VERSION 5.8 ;
BUSBITCHARS "[]" ;
DIVIDERCHAR "/" ;
UNITS
    DATABASE MICRONS 1000 ;
END UNITS

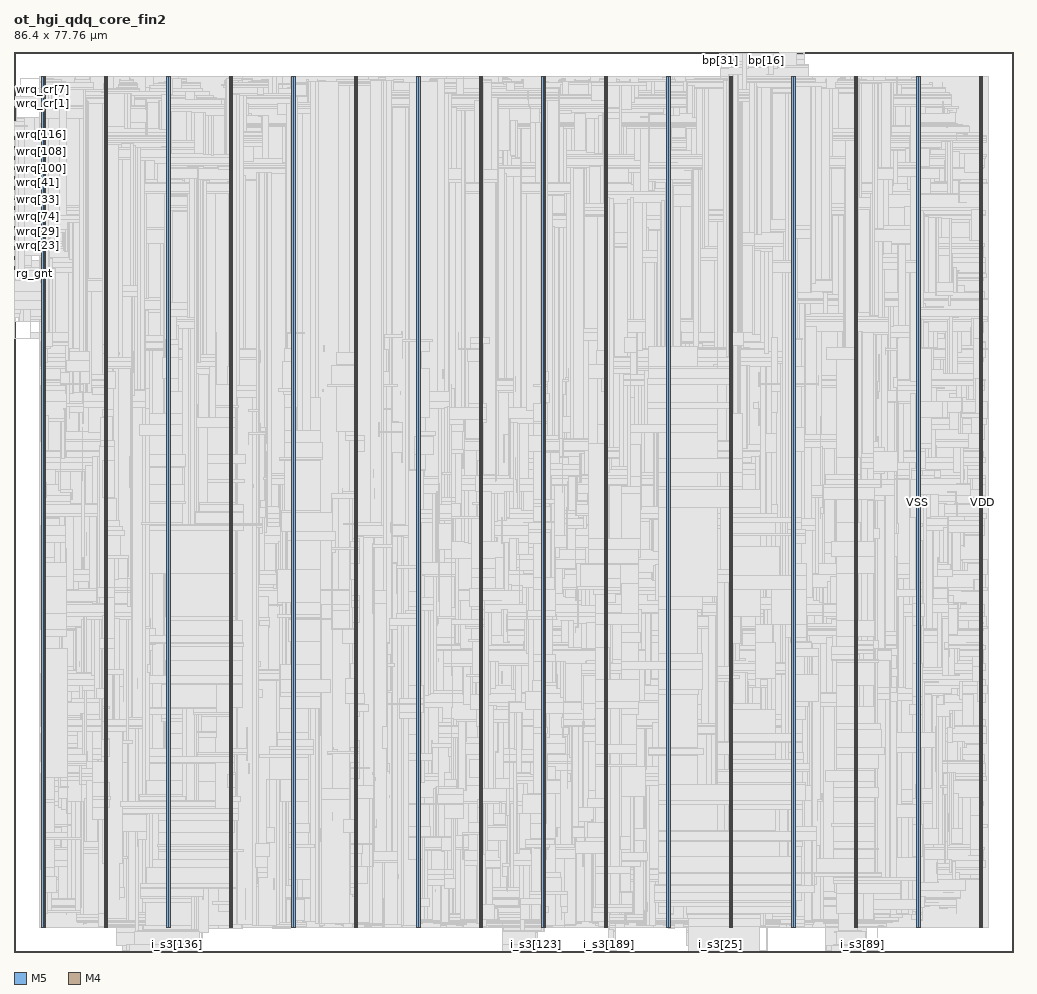
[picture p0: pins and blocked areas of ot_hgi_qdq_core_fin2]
MACRO ot_hgi_qdq_core_fin2
  FOREIGN ot_hgi_qdq_core_fin2 0 0 ;
  CLASS BLOCK ;
  SIZE 86.4 BY 77.76 ;
  PIN asm_rst_n
    DIRECTION OUTPUT ;
    USE SIGNAL ;
    PORT
      LAYER M5 ;
        RECT  63.408 77.676 63.432 77.76 ;
    END
  END asm_rst_n
  PIN bp[0]
    DIRECTION OUTPUT ;
    USE SIGNAL ;
    PORT
      LAYER M5 ;
        RECT  63.504 77.676 63.528 77.76 ;
    END
  END bp[0]
  PIN bp[10]
    DIRECTION OUTPUT ;
    USE SIGNAL ;
    PORT
      LAYER M5 ;
        RECT  64.464 77.676 64.488 77.76 ;
    END
  END bp[10]
  PIN bp[11]
    DIRECTION OUTPUT ;
    USE SIGNAL ;
    PORT
      LAYER M5 ;
        RECT  64.56 77.676 64.584 77.76 ;
    END
  END bp[11]
  PIN bp[12]
    DIRECTION OUTPUT ;
    USE SIGNAL ;
    PORT
      LAYER M5 ;
        RECT  64.656 77.676 64.68 77.76 ;
    END
  END bp[12]
  PIN bp[13]
    DIRECTION OUTPUT ;
    USE SIGNAL ;
    PORT
      LAYER M5 ;
        RECT  64.752 77.676 64.776 77.76 ;
    END
  END bp[13]
  PIN bp[14]
    DIRECTION OUTPUT ;
    USE SIGNAL ;
    PORT
      LAYER M5 ;
        RECT  64.848 77.676 64.872 77.76 ;
    END
  END bp[14]
  PIN bp[15]
    DIRECTION OUTPUT ;
    USE SIGNAL ;
    PORT
      LAYER M5 ;
        RECT  64.944 77.676 64.968 77.76 ;
    END
  END bp[15]
  PIN bp[16]
    DIRECTION OUTPUT ;
    USE SIGNAL ;
    PORT
      LAYER M5 ;
        RECT  65.04 77.676 65.064 77.76 ;
    END
  END bp[16]
  PIN bp[17]
    DIRECTION OUTPUT ;
    USE SIGNAL ;
    PORT
      LAYER M5 ;
        RECT  65.136 77.676 65.16 77.76 ;
    END
  END bp[17]
  PIN bp[18]
    DIRECTION OUTPUT ;
    USE SIGNAL ;
    PORT
      LAYER M5 ;
        RECT  65.232 77.676 65.256 77.76 ;
    END
  END bp[18]
  PIN bp[19]
    DIRECTION OUTPUT ;
    USE SIGNAL ;
    PORT
      LAYER M5 ;
        RECT  65.328 77.676 65.352 77.76 ;
    END
  END bp[19]
  PIN bp[1]
    DIRECTION OUTPUT ;
    USE SIGNAL ;
    PORT
      LAYER M5 ;
        RECT  63.6 77.676 63.624 77.76 ;
    END
  END bp[1]
  PIN bp[20]
    DIRECTION OUTPUT ;
    USE SIGNAL ;
    PORT
      LAYER M5 ;
        RECT  65.424 77.676 65.448 77.76 ;
    END
  END bp[20]
  PIN bp[21]
    DIRECTION OUTPUT ;
    USE SIGNAL ;
    PORT
      LAYER M5 ;
        RECT  65.52 77.676 65.544 77.76 ;
    END
  END bp[21]
  PIN bp[22]
    DIRECTION OUTPUT ;
    USE SIGNAL ;
    PORT
      LAYER M5 ;
        RECT  65.616 77.676 65.64 77.76 ;
    END
  END bp[22]
  PIN bp[23]
    DIRECTION OUTPUT ;
    USE SIGNAL ;
    PORT
      LAYER M5 ;
        RECT  65.712 77.676 65.736 77.76 ;
    END
  END bp[23]
  PIN bp[24]
    DIRECTION OUTPUT ;
    USE SIGNAL ;
    PORT
      LAYER M5 ;
        RECT  65.808 77.676 65.832 77.76 ;
    END
  END bp[24]
  PIN bp[25]
    DIRECTION OUTPUT ;
    USE SIGNAL ;
    PORT
      LAYER M5 ;
        RECT  65.904 77.676 65.928 77.76 ;
    END
  END bp[25]
  PIN bp[26]
    DIRECTION OUTPUT ;
    USE SIGNAL ;
    PORT
      LAYER M5 ;
        RECT  66 77.676 66.024 77.76 ;
    END
  END bp[26]
  PIN bp[27]
    DIRECTION OUTPUT ;
    USE SIGNAL ;
    PORT
      LAYER M5 ;
        RECT  66.096 77.676 66.12 77.76 ;
    END
  END bp[27]
  PIN bp[28]
    DIRECTION OUTPUT ;
    USE SIGNAL ;
    PORT
      LAYER M5 ;
        RECT  66.192 77.676 66.216 77.76 ;
    END
  END bp[28]
  PIN bp[29]
    DIRECTION OUTPUT ;
    USE SIGNAL ;
    PORT
      LAYER M5 ;
        RECT  66.288 77.676 66.312 77.76 ;
    END
  END bp[29]
  PIN bp[2]
    DIRECTION OUTPUT ;
    USE SIGNAL ;
    PORT
      LAYER M5 ;
        RECT  63.696 77.676 63.72 77.76 ;
    END
  END bp[2]
  PIN bp[30]
    DIRECTION OUTPUT ;
    USE SIGNAL ;
    PORT
      LAYER M5 ;
        RECT  66.384 77.676 66.408 77.76 ;
    END
  END bp[30]
  PIN bp[31]
    DIRECTION OUTPUT ;
    USE SIGNAL ;
    PORT
      LAYER M5 ;
        RECT  61.008 77.676 61.032 77.76 ;
    END
  END bp[31]
  PIN bp[32]
    DIRECTION OUTPUT ;
    USE SIGNAL ;
    PORT
      LAYER M5 ;
        RECT  61.104 77.676 61.128 77.76 ;
    END
  END bp[32]
  PIN bp[33]
    DIRECTION OUTPUT ;
    USE SIGNAL ;
    PORT
      LAYER M5 ;
        RECT  61.2 77.676 61.224 77.76 ;
    END
  END bp[33]
  PIN bp[34]
    DIRECTION OUTPUT ;
    USE SIGNAL ;
    PORT
      LAYER M5 ;
        RECT  61.296 77.676 61.32 77.76 ;
    END
  END bp[34]
  PIN bp[35]
    DIRECTION OUTPUT ;
    USE SIGNAL ;
    PORT
      LAYER M5 ;
        RECT  61.392 77.676 61.416 77.76 ;
    END
  END bp[35]
  PIN bp[36]
    DIRECTION OUTPUT ;
    USE SIGNAL ;
    PORT
      LAYER M5 ;
        RECT  61.488 77.676 61.512 77.76 ;
    END
  END bp[36]
  PIN bp[37]
    DIRECTION OUTPUT ;
    USE SIGNAL ;
    PORT
      LAYER M5 ;
        RECT  61.584 77.676 61.608 77.76 ;
    END
  END bp[37]
  PIN bp[38]
    DIRECTION OUTPUT ;
    USE SIGNAL ;
    PORT
      LAYER M5 ;
        RECT  61.68 77.676 61.704 77.76 ;
    END
  END bp[38]
  PIN bp[39]
    DIRECTION OUTPUT ;
    USE SIGNAL ;
    PORT
      LAYER M5 ;
        RECT  61.776 77.676 61.8 77.76 ;
    END
  END bp[39]
  PIN bp[3]
    DIRECTION OUTPUT ;
    USE SIGNAL ;
    PORT
      LAYER M5 ;
        RECT  63.792 77.676 63.816 77.76 ;
    END
  END bp[3]
  PIN bp[4]
    DIRECTION OUTPUT ;
    USE SIGNAL ;
    PORT
      LAYER M5 ;
        RECT  63.888 77.676 63.912 77.76 ;
    END
  END bp[4]
  PIN bp[5]
    DIRECTION OUTPUT ;
    USE SIGNAL ;
    PORT
      LAYER M5 ;
        RECT  63.984 77.676 64.008 77.76 ;
    END
  END bp[5]
  PIN bp[6]
    DIRECTION OUTPUT ;
    USE SIGNAL ;
    PORT
      LAYER M5 ;
        RECT  64.08 77.676 64.104 77.76 ;
    END
  END bp[6]
  PIN bp[7]
    DIRECTION OUTPUT ;
    USE SIGNAL ;
    PORT
      LAYER M5 ;
        RECT  64.176 77.676 64.2 77.76 ;
    END
  END bp[7]
  PIN bp[8]
    DIRECTION OUTPUT ;
    USE SIGNAL ;
    PORT
      LAYER M5 ;
        RECT  64.272 77.676 64.296 77.76 ;
    END
  END bp[8]
  PIN bp[9]
    DIRECTION OUTPUT ;
    USE SIGNAL ;
    PORT
      LAYER M5 ;
        RECT  64.368 77.676 64.392 77.76 ;
    END
  END bp[9]
  PIN bp_v
    DIRECTION OUTPUT ;
    USE SIGNAL ;
    PORT
      LAYER M5 ;
        RECT  61.872 77.676 61.896 77.76 ;
    END
  END bp_v
  PIN clk
    DIRECTION INPUT ;
    USE SIGNAL ;
    PORT
      LAYER M5 ;
        RECT  58.32 0 58.344 0.084 ;
    END
  END clk
  PIN i_abad
    DIRECTION INPUT ;
    USE SIGNAL ;
    PORT
      LAYER M5 ;
        RECT  61.968 77.676 61.992 77.76 ;
    END
  END i_abad
  PIN i_aidle
    DIRECTION INPUT ;
    USE SIGNAL ;
    PORT
      LAYER M5 ;
        RECT  62.064 77.676 62.088 77.76 ;
    END
  END i_aidle
  PIN i_fin
    DIRECTION INPUT ;
    USE SIGNAL ;
    PORT
      LAYER M5 ;
        RECT  62.16 77.676 62.184 77.76 ;
    END
  END i_fin
  PIN i_fire
    DIRECTION INPUT ;
    USE SIGNAL ;
    PORT
      LAYER M5 ;
        RECT  62.256 77.676 62.28 77.76 ;
    END
  END i_fire
  PIN i_nfault
    DIRECTION INPUT ;
    USE SIGNAL ;
    PORT
      LAYER M5 ;
        RECT  58.416 0 58.44 0.084 ;
    END
  END i_nfault
  PIN i_pop[0]
    DIRECTION INPUT ;
    USE SIGNAL ;
    PORT
      LAYER M5 ;
        RECT  62.352 77.676 62.376 77.76 ;
    END
  END i_pop[0]
  PIN i_pop[1]
    DIRECTION INPUT ;
    USE SIGNAL ;
    PORT
      LAYER M5 ;
        RECT  62.448 77.676 62.472 77.76 ;
    END
  END i_pop[1]
  PIN i_pop[2]
    DIRECTION INPUT ;
    USE SIGNAL ;
    PORT
      LAYER M5 ;
        RECT  62.544 77.676 62.568 77.76 ;
    END
  END i_pop[2]
  PIN i_pop[3]
    DIRECTION INPUT ;
    USE SIGNAL ;
    PORT
      LAYER M5 ;
        RECT  62.64 77.676 62.664 77.76 ;
    END
  END i_pop[3]
  PIN i_pop[4]
    DIRECTION INPUT ;
    USE SIGNAL ;
    PORT
      LAYER M5 ;
        RECT  62.736 77.676 62.76 77.76 ;
    END
  END i_pop[4]
  PIN i_pop[5]
    DIRECTION INPUT ;
    USE SIGNAL ;
    PORT
      LAYER M5 ;
        RECT  62.832 77.676 62.856 77.76 ;
    END
  END i_pop[5]
  PIN i_pop[6]
    DIRECTION INPUT ;
    USE SIGNAL ;
    PORT
      LAYER M5 ;
        RECT  62.928 77.676 62.952 77.76 ;
    END
  END i_pop[6]
  PIN i_pop[7]
    DIRECTION INPUT ;
    USE SIGNAL ;
    PORT
      LAYER M5 ;
        RECT  63.024 77.676 63.048 77.76 ;
    END
  END i_pop[7]
  PIN i_s1_v
    DIRECTION INPUT ;
    USE SIGNAL ;
    PORT
      LAYER M5 ;
        RECT  58.512 0 58.536 0.084 ;
    END
  END i_s1_v
  PIN i_s3[0]
    DIRECTION INPUT ;
    USE SIGNAL ;
    PORT
      LAYER M5 ;
        RECT  58.608 0 58.632 0.084 ;
    END
  END i_s3[0]
  PIN i_s3[100]
    DIRECTION INPUT ;
    USE SIGNAL ;
    PORT
      LAYER M5 ;
        RECT  42.864 0 42.888 0.084 ;
    END
  END i_s3[100]
  PIN i_s3[101]
    DIRECTION INPUT ;
    USE SIGNAL ;
    PORT
      LAYER M5 ;
        RECT  42.96 0 42.984 0.084 ;
    END
  END i_s3[101]
  PIN i_s3[102]
    DIRECTION INPUT ;
    USE SIGNAL ;
    PORT
      LAYER M5 ;
        RECT  43.056 0 43.08 0.084 ;
    END
  END i_s3[102]
  PIN i_s3[103]
    DIRECTION INPUT ;
    USE SIGNAL ;
    PORT
      LAYER M5 ;
        RECT  43.152 0 43.176 0.084 ;
    END
  END i_s3[103]
  PIN i_s3[104]
    DIRECTION INPUT ;
    USE SIGNAL ;
    PORT
      LAYER M5 ;
        RECT  43.248 0 43.272 0.084 ;
    END
  END i_s3[104]
  PIN i_s3[105]
    DIRECTION INPUT ;
    USE SIGNAL ;
    PORT
      LAYER M5 ;
        RECT  43.344 0 43.368 0.084 ;
    END
  END i_s3[105]
  PIN i_s3[106]
    DIRECTION INPUT ;
    USE SIGNAL ;
    PORT
      LAYER M5 ;
        RECT  43.44 0 43.464 0.084 ;
    END
  END i_s3[106]
  PIN i_s3[107]
    DIRECTION INPUT ;
    USE SIGNAL ;
    PORT
      LAYER M5 ;
        RECT  43.536 0 43.56 0.084 ;
    END
  END i_s3[107]
  PIN i_s3[108]
    DIRECTION INPUT ;
    USE SIGNAL ;
    PORT
      LAYER M5 ;
        RECT  43.632 0 43.656 0.084 ;
    END
  END i_s3[108]
  PIN i_s3[109]
    DIRECTION INPUT ;
    USE SIGNAL ;
    PORT
      LAYER M5 ;
        RECT  43.728 0 43.752 0.084 ;
    END
  END i_s3[109]
  PIN i_s3[10]
    DIRECTION INPUT ;
    USE SIGNAL ;
    PORT
      LAYER M5 ;
        RECT  59.568 0 59.592 0.084 ;
    END
  END i_s3[10]
  PIN i_s3[110]
    DIRECTION INPUT ;
    USE SIGNAL ;
    PORT
      LAYER M5 ;
        RECT  43.824 0 43.848 0.084 ;
    END
  END i_s3[110]
  PIN i_s3[111]
    DIRECTION INPUT ;
    USE SIGNAL ;
    PORT
      LAYER M5 ;
        RECT  43.92 0 43.944 0.084 ;
    END
  END i_s3[111]
  PIN i_s3[112]
    DIRECTION INPUT ;
    USE SIGNAL ;
    PORT
      LAYER M5 ;
        RECT  44.016 0 44.04 0.084 ;
    END
  END i_s3[112]
  PIN i_s3[113]
    DIRECTION INPUT ;
    USE SIGNAL ;
    PORT
      LAYER M5 ;
        RECT  44.112 0 44.136 0.084 ;
    END
  END i_s3[113]
  PIN i_s3[114]
    DIRECTION INPUT ;
    USE SIGNAL ;
    PORT
      LAYER M5 ;
        RECT  44.208 0 44.232 0.084 ;
    END
  END i_s3[114]
  PIN i_s3[115]
    DIRECTION INPUT ;
    USE SIGNAL ;
    PORT
      LAYER M5 ;
        RECT  44.304 0 44.328 0.084 ;
    END
  END i_s3[115]
  PIN i_s3[116]
    DIRECTION INPUT ;
    USE SIGNAL ;
    PORT
      LAYER M5 ;
        RECT  44.4 0 44.424 0.084 ;
    END
  END i_s3[116]
  PIN i_s3[117]
    DIRECTION INPUT ;
    USE SIGNAL ;
    PORT
      LAYER M5 ;
        RECT  44.496 0 44.52 0.084 ;
    END
  END i_s3[117]
  PIN i_s3[118]
    DIRECTION INPUT ;
    USE SIGNAL ;
    PORT
      LAYER M5 ;
        RECT  44.592 0 44.616 0.084 ;
    END
  END i_s3[118]
  PIN i_s3[119]
    DIRECTION INPUT ;
    USE SIGNAL ;
    PORT
      LAYER M5 ;
        RECT  44.688 0 44.712 0.084 ;
    END
  END i_s3[119]
  PIN i_s3[11]
    DIRECTION INPUT ;
    USE SIGNAL ;
    PORT
      LAYER M5 ;
        RECT  59.664 0 59.688 0.084 ;
    END
  END i_s3[11]
  PIN i_s3[120]
    DIRECTION INPUT ;
    USE SIGNAL ;
    PORT
      LAYER M5 ;
        RECT  44.784 0 44.808 0.084 ;
    END
  END i_s3[120]
  PIN i_s3[121]
    DIRECTION INPUT ;
    USE SIGNAL ;
    PORT
      LAYER M5 ;
        RECT  44.88 0 44.904 0.084 ;
    END
  END i_s3[121]
  PIN i_s3[122]
    DIRECTION INPUT ;
    USE SIGNAL ;
    PORT
      LAYER M5 ;
        RECT  44.976 0 45 0.084 ;
    END
  END i_s3[122]
  PIN i_s3[123]
    DIRECTION INPUT ;
    USE SIGNAL ;
    PORT
      LAYER M5 ;
        RECT  45.072 0 45.096 0.084 ;
    END
  END i_s3[123]
  PIN i_s3[124]
    DIRECTION INPUT ;
    USE SIGNAL ;
    PORT
      LAYER M5 ;
        RECT  45.168 0 45.192 0.084 ;
    END
  END i_s3[124]
  PIN i_s3[125]
    DIRECTION INPUT ;
    USE SIGNAL ;
    PORT
      LAYER M5 ;
        RECT  13.008 0 13.032 0.084 ;
    END
  END i_s3[125]
  PIN i_s3[126]
    DIRECTION INPUT ;
    USE SIGNAL ;
    PORT
      LAYER M5 ;
        RECT  13.104 0 13.128 0.084 ;
    END
  END i_s3[126]
  PIN i_s3[127]
    DIRECTION INPUT ;
    USE SIGNAL ;
    PORT
      LAYER M5 ;
        RECT  13.2 0 13.224 0.084 ;
    END
  END i_s3[127]
  PIN i_s3[128]
    DIRECTION INPUT ;
    USE SIGNAL ;
    PORT
      LAYER M5 ;
        RECT  13.296 0 13.32 0.084 ;
    END
  END i_s3[128]
  PIN i_s3[129]
    DIRECTION INPUT ;
    USE SIGNAL ;
    PORT
      LAYER M5 ;
        RECT  13.392 0 13.416 0.084 ;
    END
  END i_s3[129]
  PIN i_s3[12]
    DIRECTION INPUT ;
    USE SIGNAL ;
    PORT
      LAYER M5 ;
        RECT  59.76 0 59.784 0.084 ;
    END
  END i_s3[12]
  PIN i_s3[130]
    DIRECTION INPUT ;
    USE SIGNAL ;
    PORT
      LAYER M5 ;
        RECT  13.488 0 13.512 0.084 ;
    END
  END i_s3[130]
  PIN i_s3[131]
    DIRECTION INPUT ;
    USE SIGNAL ;
    PORT
      LAYER M5 ;
        RECT  13.584 0 13.608 0.084 ;
    END
  END i_s3[131]
  PIN i_s3[132]
    DIRECTION INPUT ;
    USE SIGNAL ;
    PORT
      LAYER M5 ;
        RECT  13.68 0 13.704 0.084 ;
    END
  END i_s3[132]
  PIN i_s3[133]
    DIRECTION INPUT ;
    USE SIGNAL ;
    PORT
      LAYER M5 ;
        RECT  13.776 0 13.8 0.084 ;
    END
  END i_s3[133]
  PIN i_s3[134]
    DIRECTION INPUT ;
    USE SIGNAL ;
    PORT
      LAYER M5 ;
        RECT  13.872 0 13.896 0.084 ;
    END
  END i_s3[134]
  PIN i_s3[135]
    DIRECTION INPUT ;
    USE SIGNAL ;
    PORT
      LAYER M5 ;
        RECT  13.968 0 13.992 0.084 ;
    END
  END i_s3[135]
  PIN i_s3[136]
    DIRECTION INPUT ;
    USE SIGNAL ;
    PORT
      LAYER M5 ;
        RECT  14.064 0 14.088 0.084 ;
    END
  END i_s3[136]
  PIN i_s3[137]
    DIRECTION INPUT ;
    USE SIGNAL ;
    PORT
      LAYER M5 ;
        RECT  14.16 0 14.184 0.084 ;
    END
  END i_s3[137]
  PIN i_s3[138]
    DIRECTION INPUT ;
    USE SIGNAL ;
    PORT
      LAYER M5 ;
        RECT  14.256 0 14.28 0.084 ;
    END
  END i_s3[138]
  PIN i_s3[139]
    DIRECTION INPUT ;
    USE SIGNAL ;
    PORT
      LAYER M5 ;
        RECT  14.352 0 14.376 0.084 ;
    END
  END i_s3[139]
  PIN i_s3[13]
    DIRECTION INPUT ;
    USE SIGNAL ;
    PORT
      LAYER M5 ;
        RECT  59.856 0 59.88 0.084 ;
    END
  END i_s3[13]
  PIN i_s3[140]
    DIRECTION INPUT ;
    USE SIGNAL ;
    PORT
      LAYER M5 ;
        RECT  14.448 0 14.472 0.084 ;
    END
  END i_s3[140]
  PIN i_s3[141]
    DIRECTION INPUT ;
    USE SIGNAL ;
    PORT
      LAYER M5 ;
        RECT  14.544 0 14.568 0.084 ;
    END
  END i_s3[141]
  PIN i_s3[142]
    DIRECTION INPUT ;
    USE SIGNAL ;
    PORT
      LAYER M5 ;
        RECT  14.64 0 14.664 0.084 ;
    END
  END i_s3[142]
  PIN i_s3[143]
    DIRECTION INPUT ;
    USE SIGNAL ;
    PORT
      LAYER M5 ;
        RECT  14.736 0 14.76 0.084 ;
    END
  END i_s3[143]
  PIN i_s3[144]
    DIRECTION INPUT ;
    USE SIGNAL ;
    PORT
      LAYER M5 ;
        RECT  14.832 0 14.856 0.084 ;
    END
  END i_s3[144]
  PIN i_s3[145]
    DIRECTION INPUT ;
    USE SIGNAL ;
    PORT
      LAYER M5 ;
        RECT  14.928 0 14.952 0.084 ;
    END
  END i_s3[145]
  PIN i_s3[146]
    DIRECTION INPUT ;
    USE SIGNAL ;
    PORT
      LAYER M5 ;
        RECT  15.024 0 15.048 0.084 ;
    END
  END i_s3[146]
  PIN i_s3[147]
    DIRECTION INPUT ;
    USE SIGNAL ;
    PORT
      LAYER M5 ;
        RECT  15.12 0 15.144 0.084 ;
    END
  END i_s3[147]
  PIN i_s3[148]
    DIRECTION INPUT ;
    USE SIGNAL ;
    PORT
      LAYER M5 ;
        RECT  15.216 0 15.24 0.084 ;
    END
  END i_s3[148]
  PIN i_s3[149]
    DIRECTION INPUT ;
    USE SIGNAL ;
    PORT
      LAYER M5 ;
        RECT  15.312 0 15.336 0.084 ;
    END
  END i_s3[149]
  PIN i_s3[14]
    DIRECTION INPUT ;
    USE SIGNAL ;
    PORT
      LAYER M5 ;
        RECT  59.952 0 59.976 0.084 ;
    END
  END i_s3[14]
  PIN i_s3[150]
    DIRECTION INPUT ;
    USE SIGNAL ;
    PORT
      LAYER M5 ;
        RECT  15.408 0 15.432 0.084 ;
    END
  END i_s3[150]
  PIN i_s3[151]
    DIRECTION INPUT ;
    USE SIGNAL ;
    PORT
      LAYER M5 ;
        RECT  15.504 0 15.528 0.084 ;
    END
  END i_s3[151]
  PIN i_s3[152]
    DIRECTION INPUT ;
    USE SIGNAL ;
    PORT
      LAYER M5 ;
        RECT  15.6 0 15.624 0.084 ;
    END
  END i_s3[152]
  PIN i_s3[153]
    DIRECTION INPUT ;
    USE SIGNAL ;
    PORT
      LAYER M5 ;
        RECT  15.696 0 15.72 0.084 ;
    END
  END i_s3[153]
  PIN i_s3[154]
    DIRECTION INPUT ;
    USE SIGNAL ;
    PORT
      LAYER M5 ;
        RECT  15.792 0 15.816 0.084 ;
    END
  END i_s3[154]
  PIN i_s3[155]
    DIRECTION INPUT ;
    USE SIGNAL ;
    PORT
      LAYER M5 ;
        RECT  15.888 0 15.912 0.084 ;
    END
  END i_s3[155]
  PIN i_s3[156]
    DIRECTION INPUT ;
    USE SIGNAL ;
    PORT
      LAYER M5 ;
        RECT  15.984 0 16.008 0.084 ;
    END
  END i_s3[156]
  PIN i_s3[157]
    DIRECTION INPUT ;
    USE SIGNAL ;
    PORT
      LAYER M5 ;
        RECT  9.936 0 9.96 0.084 ;
    END
  END i_s3[157]
  PIN i_s3[158]
    DIRECTION INPUT ;
    USE SIGNAL ;
    PORT
      LAYER M5 ;
        RECT  10.032 0 10.056 0.084 ;
    END
  END i_s3[158]
  PIN i_s3[159]
    DIRECTION INPUT ;
    USE SIGNAL ;
    PORT
      LAYER M5 ;
        RECT  10.128 0 10.152 0.084 ;
    END
  END i_s3[159]
  PIN i_s3[15]
    DIRECTION INPUT ;
    USE SIGNAL ;
    PORT
      LAYER M5 ;
        RECT  60.048 0 60.072 0.084 ;
    END
  END i_s3[15]
  PIN i_s3[160]
    DIRECTION INPUT ;
    USE SIGNAL ;
    PORT
      LAYER M5 ;
        RECT  10.224 0 10.248 0.084 ;
    END
  END i_s3[160]
  PIN i_s3[161]
    DIRECTION INPUT ;
    USE SIGNAL ;
    PORT
      LAYER M5 ;
        RECT  10.32 0 10.344 0.084 ;
    END
  END i_s3[161]
  PIN i_s3[162]
    DIRECTION INPUT ;
    USE SIGNAL ;
    PORT
      LAYER M5 ;
        RECT  10.416 0 10.44 0.084 ;
    END
  END i_s3[162]
  PIN i_s3[163]
    DIRECTION INPUT ;
    USE SIGNAL ;
    PORT
      LAYER M5 ;
        RECT  10.512 0 10.536 0.084 ;
    END
  END i_s3[163]
  PIN i_s3[164]
    DIRECTION INPUT ;
    USE SIGNAL ;
    PORT
      LAYER M5 ;
        RECT  10.608 0 10.632 0.084 ;
    END
  END i_s3[164]
  PIN i_s3[165]
    DIRECTION INPUT ;
    USE SIGNAL ;
    PORT
      LAYER M5 ;
        RECT  10.704 0 10.728 0.084 ;
    END
  END i_s3[165]
  PIN i_s3[166]
    DIRECTION INPUT ;
    USE SIGNAL ;
    PORT
      LAYER M5 ;
        RECT  10.8 0 10.824 0.084 ;
    END
  END i_s3[166]
  PIN i_s3[167]
    DIRECTION INPUT ;
    USE SIGNAL ;
    PORT
      LAYER M5 ;
        RECT  10.896 0 10.92 0.084 ;
    END
  END i_s3[167]
  PIN i_s3[168]
    DIRECTION INPUT ;
    USE SIGNAL ;
    PORT
      LAYER M5 ;
        RECT  10.992 0 11.016 0.084 ;
    END
  END i_s3[168]
  PIN i_s3[169]
    DIRECTION INPUT ;
    USE SIGNAL ;
    PORT
      LAYER M5 ;
        RECT  11.088 0 11.112 0.084 ;
    END
  END i_s3[169]
  PIN i_s3[16]
    DIRECTION INPUT ;
    USE SIGNAL ;
    PORT
      LAYER M5 ;
        RECT  60.144 0 60.168 0.084 ;
    END
  END i_s3[16]
  PIN i_s3[170]
    DIRECTION INPUT ;
    USE SIGNAL ;
    PORT
      LAYER M5 ;
        RECT  11.184 0 11.208 0.084 ;
    END
  END i_s3[170]
  PIN i_s3[171]
    DIRECTION INPUT ;
    USE SIGNAL ;
    PORT
      LAYER M5 ;
        RECT  11.28 0 11.304 0.084 ;
    END
  END i_s3[171]
  PIN i_s3[172]
    DIRECTION INPUT ;
    USE SIGNAL ;
    PORT
      LAYER M5 ;
        RECT  11.376 0 11.4 0.084 ;
    END
  END i_s3[172]
  PIN i_s3[173]
    DIRECTION INPUT ;
    USE SIGNAL ;
    PORT
      LAYER M5 ;
        RECT  11.472 0 11.496 0.084 ;
    END
  END i_s3[173]
  PIN i_s3[174]
    DIRECTION INPUT ;
    USE SIGNAL ;
    PORT
      LAYER M5 ;
        RECT  11.568 0 11.592 0.084 ;
    END
  END i_s3[174]
  PIN i_s3[175]
    DIRECTION INPUT ;
    USE SIGNAL ;
    PORT
      LAYER M5 ;
        RECT  11.664 0 11.688 0.084 ;
    END
  END i_s3[175]
  PIN i_s3[176]
    DIRECTION INPUT ;
    USE SIGNAL ;
    PORT
      LAYER M5 ;
        RECT  11.76 0 11.784 0.084 ;
    END
  END i_s3[176]
  PIN i_s3[177]
    DIRECTION INPUT ;
    USE SIGNAL ;
    PORT
      LAYER M5 ;
        RECT  11.856 0 11.88 0.084 ;
    END
  END i_s3[177]
  PIN i_s3[178]
    DIRECTION INPUT ;
    USE SIGNAL ;
    PORT
      LAYER M5 ;
        RECT  11.952 0 11.976 0.084 ;
    END
  END i_s3[178]
  PIN i_s3[179]
    DIRECTION INPUT ;
    USE SIGNAL ;
    PORT
      LAYER M5 ;
        RECT  12.048 0 12.072 0.084 ;
    END
  END i_s3[179]
  PIN i_s3[17]
    DIRECTION INPUT ;
    USE SIGNAL ;
    PORT
      LAYER M5 ;
        RECT  60.24 0 60.264 0.084 ;
    END
  END i_s3[17]
  PIN i_s3[180]
    DIRECTION INPUT ;
    USE SIGNAL ;
    PORT
      LAYER M5 ;
        RECT  12.144 0 12.168 0.084 ;
    END
  END i_s3[180]
  PIN i_s3[181]
    DIRECTION INPUT ;
    USE SIGNAL ;
    PORT
      LAYER M5 ;
        RECT  12.24 0 12.264 0.084 ;
    END
  END i_s3[181]
  PIN i_s3[182]
    DIRECTION INPUT ;
    USE SIGNAL ;
    PORT
      LAYER M5 ;
        RECT  12.336 0 12.36 0.084 ;
    END
  END i_s3[182]
  PIN i_s3[183]
    DIRECTION INPUT ;
    USE SIGNAL ;
    PORT
      LAYER M5 ;
        RECT  12.432 0 12.456 0.084 ;
    END
  END i_s3[183]
  PIN i_s3[184]
    DIRECTION INPUT ;
    USE SIGNAL ;
    PORT
      LAYER M5 ;
        RECT  12.528 0 12.552 0.084 ;
    END
  END i_s3[184]
  PIN i_s3[185]
    DIRECTION INPUT ;
    USE SIGNAL ;
    PORT
      LAYER M5 ;
        RECT  12.624 0 12.648 0.084 ;
    END
  END i_s3[185]
  PIN i_s3[186]
    DIRECTION INPUT ;
    USE SIGNAL ;
    PORT
      LAYER M5 ;
        RECT  12.72 0 12.744 0.084 ;
    END
  END i_s3[186]
  PIN i_s3[187]
    DIRECTION INPUT ;
    USE SIGNAL ;
    PORT
      LAYER M5 ;
        RECT  12.816 0 12.84 0.084 ;
    END
  END i_s3[187]
  PIN i_s3[188]
    DIRECTION INPUT ;
    USE SIGNAL ;
    PORT
      LAYER M5 ;
        RECT  12.912 0 12.936 0.084 ;
    END
  END i_s3[188]
  PIN i_s3[189]
    DIRECTION INPUT ;
    USE SIGNAL ;
    PORT
      LAYER M5 ;
        RECT  51.408 0 51.432 0.084 ;
    END
  END i_s3[189]
  PIN i_s3[18]
    DIRECTION INPUT ;
    USE SIGNAL ;
    PORT
      LAYER M5 ;
        RECT  60.336 0 60.36 0.084 ;
    END
  END i_s3[18]
  PIN i_s3[19]
    DIRECTION INPUT ;
    USE SIGNAL ;
    PORT
      LAYER M5 ;
        RECT  60.432 0 60.456 0.084 ;
    END
  END i_s3[19]
  PIN i_s3[1]
    DIRECTION INPUT ;
    USE SIGNAL ;
    PORT
      LAYER M5 ;
        RECT  58.704 0 58.728 0.084 ;
    END
  END i_s3[1]
  PIN i_s3[20]
    DIRECTION INPUT ;
    USE SIGNAL ;
    PORT
      LAYER M5 ;
        RECT  60.528 0 60.552 0.084 ;
    END
  END i_s3[20]
  PIN i_s3[21]
    DIRECTION INPUT ;
    USE SIGNAL ;
    PORT
      LAYER M5 ;
        RECT  60.624 0 60.648 0.084 ;
    END
  END i_s3[21]
  PIN i_s3[22]
    DIRECTION INPUT ;
    USE SIGNAL ;
    PORT
      LAYER M5 ;
        RECT  60.72 0 60.744 0.084 ;
    END
  END i_s3[22]
  PIN i_s3[23]
    DIRECTION INPUT ;
    USE SIGNAL ;
    PORT
      LAYER M5 ;
        RECT  60.816 0 60.84 0.084 ;
    END
  END i_s3[23]
  PIN i_s3[24]
    DIRECTION INPUT ;
    USE SIGNAL ;
    PORT
      LAYER M5 ;
        RECT  60.912 0 60.936 0.084 ;
    END
  END i_s3[24]
  PIN i_s3[25]
    DIRECTION INPUT ;
    USE SIGNAL ;
    PORT
      LAYER M5 ;
        RECT  61.008 0 61.032 0.084 ;
    END
  END i_s3[25]
  PIN i_s3[26]
    DIRECTION INPUT ;
    USE SIGNAL ;
    PORT
      LAYER M5 ;
        RECT  61.104 0 61.128 0.084 ;
    END
  END i_s3[26]
  PIN i_s3[27]
    DIRECTION INPUT ;
    USE SIGNAL ;
    PORT
      LAYER M5 ;
        RECT  61.2 0 61.224 0.084 ;
    END
  END i_s3[27]
  PIN i_s3[28]
    DIRECTION INPUT ;
    USE SIGNAL ;
    PORT
      LAYER M5 ;
        RECT  61.296 0 61.32 0.084 ;
    END
  END i_s3[28]
  PIN i_s3[29]
    DIRECTION INPUT ;
    USE SIGNAL ;
    PORT
      LAYER M5 ;
        RECT  61.392 0 61.416 0.084 ;
    END
  END i_s3[29]
  PIN i_s3[2]
    DIRECTION INPUT ;
    USE SIGNAL ;
    PORT
      LAYER M5 ;
        RECT  58.8 0 58.824 0.084 ;
    END
  END i_s3[2]
  PIN i_s3[30]
    DIRECTION INPUT ;
    USE SIGNAL ;
    PORT
      LAYER M5 ;
        RECT  61.488 0 61.512 0.084 ;
    END
  END i_s3[30]
  PIN i_s3[31]
    DIRECTION INPUT ;
    USE SIGNAL ;
    PORT
      LAYER M5 ;
        RECT  61.584 0 61.608 0.084 ;
    END
  END i_s3[31]
  PIN i_s3[32]
    DIRECTION INPUT ;
    USE SIGNAL ;
    PORT
      LAYER M5 ;
        RECT  61.68 0 61.704 0.084 ;
    END
  END i_s3[32]
  PIN i_s3[33]
    DIRECTION INPUT ;
    USE SIGNAL ;
    PORT
      LAYER M5 ;
        RECT  61.776 0 61.8 0.084 ;
    END
  END i_s3[33]
  PIN i_s3[34]
    DIRECTION INPUT ;
    USE SIGNAL ;
    PORT
      LAYER M5 ;
        RECT  61.872 0 61.896 0.084 ;
    END
  END i_s3[34]
  PIN i_s3[35]
    DIRECTION INPUT ;
    USE SIGNAL ;
    PORT
      LAYER M5 ;
        RECT  61.968 0 61.992 0.084 ;
    END
  END i_s3[35]
  PIN i_s3[36]
    DIRECTION INPUT ;
    USE SIGNAL ;
    PORT
      LAYER M5 ;
        RECT  62.064 0 62.088 0.084 ;
    END
  END i_s3[36]
  PIN i_s3[37]
    DIRECTION INPUT ;
    USE SIGNAL ;
    PORT
      LAYER M5 ;
        RECT  62.16 0 62.184 0.084 ;
    END
  END i_s3[37]
  PIN i_s3[38]
    DIRECTION INPUT ;
    USE SIGNAL ;
    PORT
      LAYER M5 ;
        RECT  62.256 0 62.28 0.084 ;
    END
  END i_s3[38]
  PIN i_s3[39]
    DIRECTION INPUT ;
    USE SIGNAL ;
    PORT
      LAYER M5 ;
        RECT  62.352 0 62.376 0.084 ;
    END
  END i_s3[39]
  PIN i_s3[3]
    DIRECTION INPUT ;
    USE SIGNAL ;
    PORT
      LAYER M5 ;
        RECT  58.896 0 58.92 0.084 ;
    END
  END i_s3[3]
  PIN i_s3[40]
    DIRECTION INPUT ;
    USE SIGNAL ;
    PORT
      LAYER M5 ;
        RECT  62.448 0 62.472 0.084 ;
    END
  END i_s3[40]
  PIN i_s3[41]
    DIRECTION INPUT ;
    USE SIGNAL ;
    PORT
      LAYER M5 ;
        RECT  62.544 0 62.568 0.084 ;
    END
  END i_s3[41]
  PIN i_s3[42]
    DIRECTION INPUT ;
    USE SIGNAL ;
    PORT
      LAYER M5 ;
        RECT  62.64 0 62.664 0.084 ;
    END
  END i_s3[42]
  PIN i_s3[43]
    DIRECTION INPUT ;
    USE SIGNAL ;
    PORT
      LAYER M5 ;
        RECT  62.736 0 62.76 0.084 ;
    END
  END i_s3[43]
  PIN i_s3[44]
    DIRECTION INPUT ;
    USE SIGNAL ;
    PORT
      LAYER M5 ;
        RECT  62.832 0 62.856 0.084 ;
    END
  END i_s3[44]
  PIN i_s3[45]
    DIRECTION INPUT ;
    USE SIGNAL ;
    PORT
      LAYER M5 ;
        RECT  62.928 0 62.952 0.084 ;
    END
  END i_s3[45]
  PIN i_s3[46]
    DIRECTION INPUT ;
    USE SIGNAL ;
    PORT
      LAYER M5 ;
        RECT  63.024 0 63.048 0.084 ;
    END
  END i_s3[46]
  PIN i_s3[47]
    DIRECTION INPUT ;
    USE SIGNAL ;
    PORT
      LAYER M5 ;
        RECT  63.12 0 63.144 0.084 ;
    END
  END i_s3[47]
  PIN i_s3[48]
    DIRECTION INPUT ;
    USE SIGNAL ;
    PORT
      LAYER M5 ;
        RECT  63.216 0 63.24 0.084 ;
    END
  END i_s3[48]
  PIN i_s3[49]
    DIRECTION INPUT ;
    USE SIGNAL ;
    PORT
      LAYER M5 ;
        RECT  63.312 0 63.336 0.084 ;
    END
  END i_s3[49]
  PIN i_s3[4]
    DIRECTION INPUT ;
    USE SIGNAL ;
    PORT
      LAYER M5 ;
        RECT  58.992 0 59.016 0.084 ;
    END
  END i_s3[4]
  PIN i_s3[50]
    DIRECTION INPUT ;
    USE SIGNAL ;
    PORT
      LAYER M5 ;
        RECT  63.408 0 63.432 0.084 ;
    END
  END i_s3[50]
  PIN i_s3[51]
    DIRECTION INPUT ;
    USE SIGNAL ;
    PORT
      LAYER M5 ;
        RECT  63.504 0 63.528 0.084 ;
    END
  END i_s3[51]
  PIN i_s3[52]
    DIRECTION INPUT ;
    USE SIGNAL ;
    PORT
      LAYER M5 ;
        RECT  63.6 0 63.624 0.084 ;
    END
  END i_s3[52]
  PIN i_s3[53]
    DIRECTION INPUT ;
    USE SIGNAL ;
    PORT
      LAYER M5 ;
        RECT  63.696 0 63.72 0.084 ;
    END
  END i_s3[53]
  PIN i_s3[54]
    DIRECTION INPUT ;
    USE SIGNAL ;
    PORT
      LAYER M5 ;
        RECT  63.792 0 63.816 0.084 ;
    END
  END i_s3[54]
  PIN i_s3[55]
    DIRECTION INPUT ;
    USE SIGNAL ;
    PORT
      LAYER M5 ;
        RECT  63.888 0 63.912 0.084 ;
    END
  END i_s3[55]
  PIN i_s3[56]
    DIRECTION INPUT ;
    USE SIGNAL ;
    PORT
      LAYER M5 ;
        RECT  63.984 0 64.008 0.084 ;
    END
  END i_s3[56]
  PIN i_s3[57]
    DIRECTION INPUT ;
    USE SIGNAL ;
    PORT
      LAYER M5 ;
        RECT  64.08 0 64.104 0.084 ;
    END
  END i_s3[57]
  PIN i_s3[58]
    DIRECTION INPUT ;
    USE SIGNAL ;
    PORT
      LAYER M5 ;
        RECT  64.176 0 64.2 0.084 ;
    END
  END i_s3[58]
  PIN i_s3[59]
    DIRECTION INPUT ;
    USE SIGNAL ;
    PORT
      LAYER M5 ;
        RECT  64.272 0 64.296 0.084 ;
    END
  END i_s3[59]
  PIN i_s3[5]
    DIRECTION INPUT ;
    USE SIGNAL ;
    PORT
      LAYER M5 ;
        RECT  59.088 0 59.112 0.084 ;
    END
  END i_s3[5]
  PIN i_s3[60]
    DIRECTION INPUT ;
    USE SIGNAL ;
    PORT
      LAYER M5 ;
        RECT  64.368 0 64.392 0.084 ;
    END
  END i_s3[60]
  PIN i_s3[61]
    DIRECTION INPUT ;
    USE SIGNAL ;
    PORT
      LAYER M5 ;
        RECT  70.608 0 70.632 0.084 ;
    END
  END i_s3[61]
  PIN i_s3[62]
    DIRECTION INPUT ;
    USE SIGNAL ;
    PORT
      LAYER M5 ;
        RECT  70.704 0 70.728 0.084 ;
    END
  END i_s3[62]
  PIN i_s3[63]
    DIRECTION INPUT ;
    USE SIGNAL ;
    PORT
      LAYER M5 ;
        RECT  70.8 0 70.824 0.084 ;
    END
  END i_s3[63]
  PIN i_s3[64]
    DIRECTION INPUT ;
    USE SIGNAL ;
    PORT
      LAYER M5 ;
        RECT  70.896 0 70.92 0.084 ;
    END
  END i_s3[64]
  PIN i_s3[65]
    DIRECTION INPUT ;
    USE SIGNAL ;
    PORT
      LAYER M5 ;
        RECT  70.992 0 71.016 0.084 ;
    END
  END i_s3[65]
  PIN i_s3[66]
    DIRECTION INPUT ;
    USE SIGNAL ;
    PORT
      LAYER M5 ;
        RECT  71.088 0 71.112 0.084 ;
    END
  END i_s3[66]
  PIN i_s3[67]
    DIRECTION INPUT ;
    USE SIGNAL ;
    PORT
      LAYER M5 ;
        RECT  71.184 0 71.208 0.084 ;
    END
  END i_s3[67]
  PIN i_s3[68]
    DIRECTION INPUT ;
    USE SIGNAL ;
    PORT
      LAYER M5 ;
        RECT  71.28 0 71.304 0.084 ;
    END
  END i_s3[68]
  PIN i_s3[69]
    DIRECTION INPUT ;
    USE SIGNAL ;
    PORT
      LAYER M5 ;
        RECT  71.376 0 71.4 0.084 ;
    END
  END i_s3[69]
  PIN i_s3[6]
    DIRECTION INPUT ;
    USE SIGNAL ;
    PORT
      LAYER M5 ;
        RECT  59.184 0 59.208 0.084 ;
    END
  END i_s3[6]
  PIN i_s3[70]
    DIRECTION INPUT ;
    USE SIGNAL ;
    PORT
      LAYER M5 ;
        RECT  71.472 0 71.496 0.084 ;
    END
  END i_s3[70]
  PIN i_s3[71]
    DIRECTION INPUT ;
    USE SIGNAL ;
    PORT
      LAYER M5 ;
        RECT  71.568 0 71.592 0.084 ;
    END
  END i_s3[71]
  PIN i_s3[72]
    DIRECTION INPUT ;
    USE SIGNAL ;
    PORT
      LAYER M5 ;
        RECT  71.664 0 71.688 0.084 ;
    END
  END i_s3[72]
  PIN i_s3[73]
    DIRECTION INPUT ;
    USE SIGNAL ;
    PORT
      LAYER M5 ;
        RECT  71.76 0 71.784 0.084 ;
    END
  END i_s3[73]
  PIN i_s3[74]
    DIRECTION INPUT ;
    USE SIGNAL ;
    PORT
      LAYER M5 ;
        RECT  71.856 0 71.88 0.084 ;
    END
  END i_s3[74]
  PIN i_s3[75]
    DIRECTION INPUT ;
    USE SIGNAL ;
    PORT
      LAYER M5 ;
        RECT  71.952 0 71.976 0.084 ;
    END
  END i_s3[75]
  PIN i_s3[76]
    DIRECTION INPUT ;
    USE SIGNAL ;
    PORT
      LAYER M5 ;
        RECT  72.048 0 72.072 0.084 ;
    END
  END i_s3[76]
  PIN i_s3[77]
    DIRECTION INPUT ;
    USE SIGNAL ;
    PORT
      LAYER M5 ;
        RECT  72.144 0 72.168 0.084 ;
    END
  END i_s3[77]
  PIN i_s3[78]
    DIRECTION INPUT ;
    USE SIGNAL ;
    PORT
      LAYER M5 ;
        RECT  72.24 0 72.264 0.084 ;
    END
  END i_s3[78]
  PIN i_s3[79]
    DIRECTION INPUT ;
    USE SIGNAL ;
    PORT
      LAYER M5 ;
        RECT  72.336 0 72.36 0.084 ;
    END
  END i_s3[79]
  PIN i_s3[7]
    DIRECTION INPUT ;
    USE SIGNAL ;
    PORT
      LAYER M5 ;
        RECT  59.28 0 59.304 0.084 ;
    END
  END i_s3[7]
  PIN i_s3[80]
    DIRECTION INPUT ;
    USE SIGNAL ;
    PORT
      LAYER M5 ;
        RECT  72.432 0 72.456 0.084 ;
    END
  END i_s3[80]
  PIN i_s3[81]
    DIRECTION INPUT ;
    USE SIGNAL ;
    PORT
      LAYER M5 ;
        RECT  72.528 0 72.552 0.084 ;
    END
  END i_s3[81]
  PIN i_s3[82]
    DIRECTION INPUT ;
    USE SIGNAL ;
    PORT
      LAYER M5 ;
        RECT  72.624 0 72.648 0.084 ;
    END
  END i_s3[82]
  PIN i_s3[83]
    DIRECTION INPUT ;
    USE SIGNAL ;
    PORT
      LAYER M5 ;
        RECT  72.72 0 72.744 0.084 ;
    END
  END i_s3[83]
  PIN i_s3[84]
    DIRECTION INPUT ;
    USE SIGNAL ;
    PORT
      LAYER M5 ;
        RECT  72.816 0 72.84 0.084 ;
    END
  END i_s3[84]
  PIN i_s3[85]
    DIRECTION INPUT ;
    USE SIGNAL ;
    PORT
      LAYER M5 ;
        RECT  72.912 0 72.936 0.084 ;
    END
  END i_s3[85]
  PIN i_s3[86]
    DIRECTION INPUT ;
    USE SIGNAL ;
    PORT
      LAYER M5 ;
        RECT  73.008 0 73.032 0.084 ;
    END
  END i_s3[86]
  PIN i_s3[87]
    DIRECTION INPUT ;
    USE SIGNAL ;
    PORT
      LAYER M5 ;
        RECT  73.104 0 73.128 0.084 ;
    END
  END i_s3[87]
  PIN i_s3[88]
    DIRECTION INPUT ;
    USE SIGNAL ;
    PORT
      LAYER M5 ;
        RECT  73.2 0 73.224 0.084 ;
    END
  END i_s3[88]
  PIN i_s3[89]
    DIRECTION INPUT ;
    USE SIGNAL ;
    PORT
      LAYER M5 ;
        RECT  73.296 0 73.32 0.084 ;
    END
  END i_s3[89]
  PIN i_s3[8]
    DIRECTION INPUT ;
    USE SIGNAL ;
    PORT
      LAYER M5 ;
        RECT  59.376 0 59.4 0.084 ;
    END
  END i_s3[8]
  PIN i_s3[90]
    DIRECTION INPUT ;
    USE SIGNAL ;
    PORT
      LAYER M5 ;
        RECT  73.392 0 73.416 0.084 ;
    END
  END i_s3[90]
  PIN i_s3[91]
    DIRECTION INPUT ;
    USE SIGNAL ;
    PORT
      LAYER M5 ;
        RECT  73.488 0 73.512 0.084 ;
    END
  END i_s3[91]
  PIN i_s3[92]
    DIRECTION INPUT ;
    USE SIGNAL ;
    PORT
      LAYER M5 ;
        RECT  73.584 0 73.608 0.084 ;
    END
  END i_s3[92]
  PIN i_s3[93]
    DIRECTION INPUT ;
    USE SIGNAL ;
    PORT
      LAYER M5 ;
        RECT  42.192 0 42.216 0.084 ;
    END
  END i_s3[93]
  PIN i_s3[94]
    DIRECTION INPUT ;
    USE SIGNAL ;
    PORT
      LAYER M5 ;
        RECT  42.288 0 42.312 0.084 ;
    END
  END i_s3[94]
  PIN i_s3[95]
    DIRECTION INPUT ;
    USE SIGNAL ;
    PORT
      LAYER M5 ;
        RECT  42.384 0 42.408 0.084 ;
    END
  END i_s3[95]
  PIN i_s3[96]
    DIRECTION INPUT ;
    USE SIGNAL ;
    PORT
      LAYER M5 ;
        RECT  42.48 0 42.504 0.084 ;
    END
  END i_s3[96]
  PIN i_s3[97]
    DIRECTION INPUT ;
    USE SIGNAL ;
    PORT
      LAYER M5 ;
        RECT  42.576 0 42.6 0.084 ;
    END
  END i_s3[97]
  PIN i_s3[98]
    DIRECTION INPUT ;
    USE SIGNAL ;
    PORT
      LAYER M5 ;
        RECT  42.672 0 42.696 0.084 ;
    END
  END i_s3[98]
  PIN i_s3[99]
    DIRECTION INPUT ;
    USE SIGNAL ;
    PORT
      LAYER M5 ;
        RECT  42.768 0 42.792 0.084 ;
    END
  END i_s3[99]
  PIN i_s3[9]
    DIRECTION INPUT ;
    USE SIGNAL ;
    PORT
      LAYER M5 ;
        RECT  59.472 0 59.496 0.084 ;
    END
  END i_s3[9]
  PIN i_s3_v
    DIRECTION INPUT ;
    USE SIGNAL ;
    PORT
      LAYER M5 ;
        RECT  51.504 0 51.528 0.084 ;
    END
  END i_s3_v
  PIN i_wbad
    DIRECTION INPUT ;
    USE SIGNAL ;
    PORT
      LAYER M5 ;
        RECT  63.12 77.676 63.144 77.76 ;
    END
  END i_wbad
  PIN i_widle
    DIRECTION INPUT ;
    USE SIGNAL ;
    PORT
      LAYER M5 ;
        RECT  63.216 77.676 63.24 77.76 ;
    END
  END i_widle
  PIN o_act
    DIRECTION OUTPUT ;
    USE SIGNAL ;
    PORT
      LAYER M5 ;
        RECT  63.312 77.676 63.336 77.76 ;
    END
  END o_act
  PIN ret[0]
    DIRECTION OUTPUT ;
    USE SIGNAL ;
    PORT
      LAYER M5 ;
        RECT  51.6 0 51.624 0.084 ;
    END
  END ret[0]
  PIN ret[1]
    DIRECTION OUTPUT ;
    USE SIGNAL ;
    PORT
      LAYER M5 ;
        RECT  51.696 0 51.72 0.084 ;
    END
  END ret[1]
  PIN ret[2]
    DIRECTION OUTPUT ;
    USE SIGNAL ;
    PORT
      LAYER M5 ;
        RECT  51.792 0 51.816 0.084 ;
    END
  END ret[2]
  PIN rg_gnt
    DIRECTION INPUT ;
    USE SIGNAL ;
    PORT
      LAYER M4 ;
        RECT  0 58.608 0.084 58.632 ;
    END
  END rg_gnt
  PIN rg_req
    DIRECTION OUTPUT ;
    USE SIGNAL ;
    PORT
      LAYER M4 ;
        RECT  0 58.704 0.084 58.728 ;
    END
  END rg_req
  PIN rst_n
    DIRECTION INPUT ;
    USE SIGNAL ;
    PORT
      LAYER M5 ;
        RECT  51.888 0 51.912 0.084 ;
    END
  END rst_n
  PIN wrq[0]
    DIRECTION OUTPUT ;
    USE SIGNAL ;
    PORT
      LAYER M4 ;
        RECT  0 58.8 0.084 58.824 ;
    END
  END wrq[0]
  PIN wrq[100]
    DIRECTION OUTPUT ;
    USE SIGNAL ;
    PORT
      LAYER M4 ;
        RECT  0 68.4 0.084 68.424 ;
    END
  END wrq[100]
  PIN wrq[101]
    DIRECTION OUTPUT ;
    USE SIGNAL ;
    PORT
      LAYER M4 ;
        RECT  0 68.496 0.084 68.52 ;
    END
  END wrq[101]
  PIN wrq[102]
    DIRECTION OUTPUT ;
    USE SIGNAL ;
    PORT
      LAYER M4 ;
        RECT  0 68.592 0.084 68.616 ;
    END
  END wrq[102]
  PIN wrq[103]
    DIRECTION OUTPUT ;
    USE SIGNAL ;
    PORT
      LAYER M4 ;
        RECT  0 68.688 0.084 68.712 ;
    END
  END wrq[103]
  PIN wrq[104]
    DIRECTION OUTPUT ;
    USE SIGNAL ;
    PORT
      LAYER M4 ;
        RECT  0 68.784 0.084 68.808 ;
    END
  END wrq[104]
  PIN wrq[105]
    DIRECTION OUTPUT ;
    USE SIGNAL ;
    PORT
      LAYER M4 ;
        RECT  0 68.88 0.084 68.904 ;
    END
  END wrq[105]
  PIN wrq[106]
    DIRECTION OUTPUT ;
    USE SIGNAL ;
    PORT
      LAYER M4 ;
        RECT  0 68.976 0.084 69 ;
    END
  END wrq[106]
  PIN wrq[107]
    DIRECTION OUTPUT ;
    USE SIGNAL ;
    PORT
      LAYER M4 ;
        RECT  0 69.072 0.084 69.096 ;
    END
  END wrq[107]
  PIN wrq[108]
    DIRECTION OUTPUT ;
    USE SIGNAL ;
    PORT
      LAYER M4 ;
        RECT  0 69.168 0.084 69.192 ;
    END
  END wrq[108]
  PIN wrq[109]
    DIRECTION OUTPUT ;
    USE SIGNAL ;
    PORT
      LAYER M4 ;
        RECT  0 69.264 0.084 69.288 ;
    END
  END wrq[109]
  PIN wrq[10]
    DIRECTION OUTPUT ;
    USE SIGNAL ;
    PORT
      LAYER M4 ;
        RECT  0 59.76 0.084 59.784 ;
    END
  END wrq[10]
  PIN wrq[110]
    DIRECTION OUTPUT ;
    USE SIGNAL ;
    PORT
      LAYER M4 ;
        RECT  0 69.36 0.084 69.384 ;
    END
  END wrq[110]
  PIN wrq[111]
    DIRECTION OUTPUT ;
    USE SIGNAL ;
    PORT
      LAYER M4 ;
        RECT  0 69.456 0.084 69.48 ;
    END
  END wrq[111]
  PIN wrq[112]
    DIRECTION OUTPUT ;
    USE SIGNAL ;
    PORT
      LAYER M4 ;
        RECT  0 69.552 0.084 69.576 ;
    END
  END wrq[112]
  PIN wrq[113]
    DIRECTION OUTPUT ;
    USE SIGNAL ;
    PORT
      LAYER M4 ;
        RECT  0 69.648 0.084 69.672 ;
    END
  END wrq[113]
  PIN wrq[114]
    DIRECTION OUTPUT ;
    USE SIGNAL ;
    PORT
      LAYER M4 ;
        RECT  0 69.744 0.084 69.768 ;
    END
  END wrq[114]
  PIN wrq[115]
    DIRECTION OUTPUT ;
    USE SIGNAL ;
    PORT
      LAYER M4 ;
        RECT  0 69.84 0.084 69.864 ;
    END
  END wrq[115]
  PIN wrq[116]
    DIRECTION OUTPUT ;
    USE SIGNAL ;
    PORT
      LAYER M4 ;
        RECT  0 69.936 0.084 69.96 ;
    END
  END wrq[116]
  PIN wrq[117]
    DIRECTION OUTPUT ;
    USE SIGNAL ;
    PORT
      LAYER M4 ;
        RECT  0 70.032 0.084 70.056 ;
    END
  END wrq[117]
  PIN wrq[118]
    DIRECTION OUTPUT ;
    USE SIGNAL ;
    PORT
      LAYER M4 ;
        RECT  0 70.128 0.084 70.152 ;
    END
  END wrq[118]
  PIN wrq[119]
    DIRECTION OUTPUT ;
    USE SIGNAL ;
    PORT
      LAYER M4 ;
        RECT  0 70.224 0.084 70.248 ;
    END
  END wrq[119]
  PIN wrq[11]
    DIRECTION OUTPUT ;
    USE SIGNAL ;
    PORT
      LAYER M4 ;
        RECT  0 59.856 0.084 59.88 ;
    END
  END wrq[11]
  PIN wrq[120]
    DIRECTION OUTPUT ;
    USE SIGNAL ;
    PORT
      LAYER M4 ;
        RECT  0 70.32 0.084 70.344 ;
    END
  END wrq[120]
  PIN wrq[121]
    DIRECTION OUTPUT ;
    USE SIGNAL ;
    PORT
      LAYER M4 ;
        RECT  0 70.416 0.084 70.44 ;
    END
  END wrq[121]
  PIN wrq[122]
    DIRECTION OUTPUT ;
    USE SIGNAL ;
    PORT
      LAYER M4 ;
        RECT  0 70.512 0.084 70.536 ;
    END
  END wrq[122]
  PIN wrq[123]
    DIRECTION OUTPUT ;
    USE SIGNAL ;
    PORT
      LAYER M4 ;
        RECT  0 70.608 0.084 70.632 ;
    END
  END wrq[123]
  PIN wrq[124]
    DIRECTION OUTPUT ;
    USE SIGNAL ;
    PORT
      LAYER M4 ;
        RECT  0 70.704 0.084 70.728 ;
    END
  END wrq[124]
  PIN wrq[125]
    DIRECTION OUTPUT ;
    USE SIGNAL ;
    PORT
      LAYER M4 ;
        RECT  0 70.8 0.084 70.824 ;
    END
  END wrq[125]
  PIN wrq[126]
    DIRECTION OUTPUT ;
    USE SIGNAL ;
    PORT
      LAYER M4 ;
        RECT  0 73.008 0.084 73.032 ;
    END
  END wrq[126]
  PIN wrq[127]
    DIRECTION OUTPUT ;
    USE SIGNAL ;
    PORT
      LAYER M4 ;
        RECT  0 73.104 0.084 73.128 ;
    END
  END wrq[127]
  PIN wrq[12]
    DIRECTION OUTPUT ;
    USE SIGNAL ;
    PORT
      LAYER M4 ;
        RECT  0 59.952 0.084 59.976 ;
    END
  END wrq[12]
  PIN wrq[13]
    DIRECTION OUTPUT ;
    USE SIGNAL ;
    PORT
      LAYER M4 ;
        RECT  0 60.048 0.084 60.072 ;
    END
  END wrq[13]
  PIN wrq[14]
    DIRECTION OUTPUT ;
    USE SIGNAL ;
    PORT
      LAYER M4 ;
        RECT  0 60.144 0.084 60.168 ;
    END
  END wrq[14]
  PIN wrq[15]
    DIRECTION OUTPUT ;
    USE SIGNAL ;
    PORT
      LAYER M4 ;
        RECT  0 60.24 0.084 60.264 ;
    END
  END wrq[15]
  PIN wrq[16]
    DIRECTION OUTPUT ;
    USE SIGNAL ;
    PORT
      LAYER M4 ;
        RECT  0 60.336 0.084 60.36 ;
    END
  END wrq[16]
  PIN wrq[17]
    DIRECTION OUTPUT ;
    USE SIGNAL ;
    PORT
      LAYER M4 ;
        RECT  0 60.432 0.084 60.456 ;
    END
  END wrq[17]
  PIN wrq[18]
    DIRECTION OUTPUT ;
    USE SIGNAL ;
    PORT
      LAYER M4 ;
        RECT  0 60.528 0.084 60.552 ;
    END
  END wrq[18]
  PIN wrq[19]
    DIRECTION OUTPUT ;
    USE SIGNAL ;
    PORT
      LAYER M4 ;
        RECT  0 60.624 0.084 60.648 ;
    END
  END wrq[19]
  PIN wrq[1]
    DIRECTION OUTPUT ;
    USE SIGNAL ;
    PORT
      LAYER M4 ;
        RECT  0 58.896 0.084 58.92 ;
    END
  END wrq[1]
  PIN wrq[20]
    DIRECTION OUTPUT ;
    USE SIGNAL ;
    PORT
      LAYER M4 ;
        RECT  0 60.72 0.084 60.744 ;
    END
  END wrq[20]
  PIN wrq[21]
    DIRECTION OUTPUT ;
    USE SIGNAL ;
    PORT
      LAYER M4 ;
        RECT  0 60.816 0.084 60.84 ;
    END
  END wrq[21]
  PIN wrq[22]
    DIRECTION OUTPUT ;
    USE SIGNAL ;
    PORT
      LAYER M4 ;
        RECT  0 60.912 0.084 60.936 ;
    END
  END wrq[22]
  PIN wrq[23]
    DIRECTION OUTPUT ;
    USE SIGNAL ;
    PORT
      LAYER M4 ;
        RECT  0 61.008 0.084 61.032 ;
    END
  END wrq[23]
  PIN wrq[24]
    DIRECTION OUTPUT ;
    USE SIGNAL ;
    PORT
      LAYER M4 ;
        RECT  0 61.104 0.084 61.128 ;
    END
  END wrq[24]
  PIN wrq[25]
    DIRECTION OUTPUT ;
    USE SIGNAL ;
    PORT
      LAYER M4 ;
        RECT  0 61.2 0.084 61.224 ;
    END
  END wrq[25]
  PIN wrq[26]
    DIRECTION OUTPUT ;
    USE SIGNAL ;
    PORT
      LAYER M4 ;
        RECT  0 61.296 0.084 61.32 ;
    END
  END wrq[26]
  PIN wrq[27]
    DIRECTION OUTPUT ;
    USE SIGNAL ;
    PORT
      LAYER M4 ;
        RECT  0 61.392 0.084 61.416 ;
    END
  END wrq[27]
  PIN wrq[28]
    DIRECTION OUTPUT ;
    USE SIGNAL ;
    PORT
      LAYER M4 ;
        RECT  0 61.488 0.084 61.512 ;
    END
  END wrq[28]
  PIN wrq[29]
    DIRECTION OUTPUT ;
    USE SIGNAL ;
    PORT
      LAYER M4 ;
        RECT  0 61.584 0.084 61.608 ;
    END
  END wrq[29]
  PIN wrq[2]
    DIRECTION OUTPUT ;
    USE SIGNAL ;
    PORT
      LAYER M4 ;
        RECT  0 58.992 0.084 59.016 ;
    END
  END wrq[2]
  PIN wrq[30]
    DIRECTION OUTPUT ;
    USE SIGNAL ;
    PORT
      LAYER M4 ;
        RECT  0 64.752 0.084 64.776 ;
    END
  END wrq[30]
  PIN wrq[31]
    DIRECTION OUTPUT ;
    USE SIGNAL ;
    PORT
      LAYER M4 ;
        RECT  0 64.848 0.084 64.872 ;
    END
  END wrq[31]
  PIN wrq[32]
    DIRECTION OUTPUT ;
    USE SIGNAL ;
    PORT
      LAYER M4 ;
        RECT  0 64.944 0.084 64.968 ;
    END
  END wrq[32]
  PIN wrq[33]
    DIRECTION OUTPUT ;
    USE SIGNAL ;
    PORT
      LAYER M4 ;
        RECT  0 65.04 0.084 65.064 ;
    END
  END wrq[33]
  PIN wrq[34]
    DIRECTION OUTPUT ;
    USE SIGNAL ;
    PORT
      LAYER M4 ;
        RECT  0 65.136 0.084 65.16 ;
    END
  END wrq[34]
  PIN wrq[35]
    DIRECTION OUTPUT ;
    USE SIGNAL ;
    PORT
      LAYER M4 ;
        RECT  0 65.232 0.084 65.256 ;
    END
  END wrq[35]
  PIN wrq[36]
    DIRECTION OUTPUT ;
    USE SIGNAL ;
    PORT
      LAYER M4 ;
        RECT  0 65.328 0.084 65.352 ;
    END
  END wrq[36]
  PIN wrq[37]
    DIRECTION OUTPUT ;
    USE SIGNAL ;
    PORT
      LAYER M4 ;
        RECT  0 65.424 0.084 65.448 ;
    END
  END wrq[37]
  PIN wrq[38]
    DIRECTION OUTPUT ;
    USE SIGNAL ;
    PORT
      LAYER M4 ;
        RECT  0 65.52 0.084 65.544 ;
    END
  END wrq[38]
  PIN wrq[39]
    DIRECTION OUTPUT ;
    USE SIGNAL ;
    PORT
      LAYER M4 ;
        RECT  0 65.616 0.084 65.64 ;
    END
  END wrq[39]
  PIN wrq[3]
    DIRECTION OUTPUT ;
    USE SIGNAL ;
    PORT
      LAYER M4 ;
        RECT  0 59.088 0.084 59.112 ;
    END
  END wrq[3]
  PIN wrq[40]
    DIRECTION OUTPUT ;
    USE SIGNAL ;
    PORT
      LAYER M4 ;
        RECT  0 65.712 0.084 65.736 ;
    END
  END wrq[40]
  PIN wrq[41]
    DIRECTION OUTPUT ;
    USE SIGNAL ;
    PORT
      LAYER M4 ;
        RECT  0 65.808 0.084 65.832 ;
    END
  END wrq[41]
  PIN wrq[42]
    DIRECTION OUTPUT ;
    USE SIGNAL ;
    PORT
      LAYER M4 ;
        RECT  0 65.904 0.084 65.928 ;
    END
  END wrq[42]
  PIN wrq[43]
    DIRECTION OUTPUT ;
    USE SIGNAL ;
    PORT
      LAYER M4 ;
        RECT  0 66 0.084 66.024 ;
    END
  END wrq[43]
  PIN wrq[44]
    DIRECTION OUTPUT ;
    USE SIGNAL ;
    PORT
      LAYER M4 ;
        RECT  0 66.096 0.084 66.12 ;
    END
  END wrq[44]
  PIN wrq[45]
    DIRECTION OUTPUT ;
    USE SIGNAL ;
    PORT
      LAYER M4 ;
        RECT  0 66.192 0.084 66.216 ;
    END
  END wrq[45]
  PIN wrq[46]
    DIRECTION OUTPUT ;
    USE SIGNAL ;
    PORT
      LAYER M4 ;
        RECT  0 66.288 0.084 66.312 ;
    END
  END wrq[46]
  PIN wrq[47]
    DIRECTION OUTPUT ;
    USE SIGNAL ;
    PORT
      LAYER M4 ;
        RECT  0 66.384 0.084 66.408 ;
    END
  END wrq[47]
  PIN wrq[48]
    DIRECTION OUTPUT ;
    USE SIGNAL ;
    PORT
      LAYER M4 ;
        RECT  0 66.48 0.084 66.504 ;
    END
  END wrq[48]
  PIN wrq[49]
    DIRECTION OUTPUT ;
    USE SIGNAL ;
    PORT
      LAYER M4 ;
        RECT  0 66.576 0.084 66.6 ;
    END
  END wrq[49]
  PIN wrq[4]
    DIRECTION OUTPUT ;
    USE SIGNAL ;
    PORT
      LAYER M4 ;
        RECT  0 59.184 0.084 59.208 ;
    END
  END wrq[4]
  PIN wrq[50]
    DIRECTION OUTPUT ;
    USE SIGNAL ;
    PORT
      LAYER M4 ;
        RECT  0 66.672 0.084 66.696 ;
    END
  END wrq[50]
  PIN wrq[51]
    DIRECTION OUTPUT ;
    USE SIGNAL ;
    PORT
      LAYER M4 ;
        RECT  0 66.768 0.084 66.792 ;
    END
  END wrq[51]
  PIN wrq[52]
    DIRECTION OUTPUT ;
    USE SIGNAL ;
    PORT
      LAYER M4 ;
        RECT  0 66.864 0.084 66.888 ;
    END
  END wrq[52]
  PIN wrq[53]
    DIRECTION OUTPUT ;
    USE SIGNAL ;
    PORT
      LAYER M4 ;
        RECT  0 66.96 0.084 66.984 ;
    END
  END wrq[53]
  PIN wrq[54]
    DIRECTION OUTPUT ;
    USE SIGNAL ;
    PORT
      LAYER M4 ;
        RECT  0 67.056 0.084 67.08 ;
    END
  END wrq[54]
  PIN wrq[55]
    DIRECTION OUTPUT ;
    USE SIGNAL ;
    PORT
      LAYER M4 ;
        RECT  0 67.152 0.084 67.176 ;
    END
  END wrq[55]
  PIN wrq[56]
    DIRECTION OUTPUT ;
    USE SIGNAL ;
    PORT
      LAYER M4 ;
        RECT  0 67.248 0.084 67.272 ;
    END
  END wrq[56]
  PIN wrq[57]
    DIRECTION OUTPUT ;
    USE SIGNAL ;
    PORT
      LAYER M4 ;
        RECT  0 67.344 0.084 67.368 ;
    END
  END wrq[57]
  PIN wrq[58]
    DIRECTION OUTPUT ;
    USE SIGNAL ;
    PORT
      LAYER M4 ;
        RECT  0 67.44 0.084 67.464 ;
    END
  END wrq[58]
  PIN wrq[59]
    DIRECTION OUTPUT ;
    USE SIGNAL ;
    PORT
      LAYER M4 ;
        RECT  0 67.536 0.084 67.56 ;
    END
  END wrq[59]
  PIN wrq[5]
    DIRECTION OUTPUT ;
    USE SIGNAL ;
    PORT
      LAYER M4 ;
        RECT  0 59.28 0.084 59.304 ;
    END
  END wrq[5]
  PIN wrq[60]
    DIRECTION OUTPUT ;
    USE SIGNAL ;
    PORT
      LAYER M4 ;
        RECT  0 67.632 0.084 67.656 ;
    END
  END wrq[60]
  PIN wrq[61]
    DIRECTION OUTPUT ;
    USE SIGNAL ;
    PORT
      LAYER M4 ;
        RECT  0 67.728 0.084 67.752 ;
    END
  END wrq[61]
  PIN wrq[62]
    DIRECTION OUTPUT ;
    USE SIGNAL ;
    PORT
      LAYER M4 ;
        RECT  0 61.68 0.084 61.704 ;
    END
  END wrq[62]
  PIN wrq[63]
    DIRECTION OUTPUT ;
    USE SIGNAL ;
    PORT
      LAYER M4 ;
        RECT  0 61.776 0.084 61.8 ;
    END
  END wrq[63]
  PIN wrq[64]
    DIRECTION OUTPUT ;
    USE SIGNAL ;
    PORT
      LAYER M4 ;
        RECT  0 61.872 0.084 61.896 ;
    END
  END wrq[64]
  PIN wrq[65]
    DIRECTION OUTPUT ;
    USE SIGNAL ;
    PORT
      LAYER M4 ;
        RECT  0 61.968 0.084 61.992 ;
    END
  END wrq[65]
  PIN wrq[66]
    DIRECTION OUTPUT ;
    USE SIGNAL ;
    PORT
      LAYER M4 ;
        RECT  0 62.064 0.084 62.088 ;
    END
  END wrq[66]
  PIN wrq[67]
    DIRECTION OUTPUT ;
    USE SIGNAL ;
    PORT
      LAYER M4 ;
        RECT  0 62.16 0.084 62.184 ;
    END
  END wrq[67]
  PIN wrq[68]
    DIRECTION OUTPUT ;
    USE SIGNAL ;
    PORT
      LAYER M4 ;
        RECT  0 62.256 0.084 62.28 ;
    END
  END wrq[68]
  PIN wrq[69]
    DIRECTION OUTPUT ;
    USE SIGNAL ;
    PORT
      LAYER M4 ;
        RECT  0 62.352 0.084 62.376 ;
    END
  END wrq[69]
  PIN wrq[6]
    DIRECTION OUTPUT ;
    USE SIGNAL ;
    PORT
      LAYER M4 ;
        RECT  0 59.376 0.084 59.4 ;
    END
  END wrq[6]
  PIN wrq[70]
    DIRECTION OUTPUT ;
    USE SIGNAL ;
    PORT
      LAYER M4 ;
        RECT  0 62.448 0.084 62.472 ;
    END
  END wrq[70]
  PIN wrq[71]
    DIRECTION OUTPUT ;
    USE SIGNAL ;
    PORT
      LAYER M4 ;
        RECT  0 62.544 0.084 62.568 ;
    END
  END wrq[71]
  PIN wrq[72]
    DIRECTION OUTPUT ;
    USE SIGNAL ;
    PORT
      LAYER M4 ;
        RECT  0 62.64 0.084 62.664 ;
    END
  END wrq[72]
  PIN wrq[73]
    DIRECTION OUTPUT ;
    USE SIGNAL ;
    PORT
      LAYER M4 ;
        RECT  0 62.736 0.084 62.76 ;
    END
  END wrq[73]
  PIN wrq[74]
    DIRECTION OUTPUT ;
    USE SIGNAL ;
    PORT
      LAYER M4 ;
        RECT  0 62.832 0.084 62.856 ;
    END
  END wrq[74]
  PIN wrq[75]
    DIRECTION OUTPUT ;
    USE SIGNAL ;
    PORT
      LAYER M4 ;
        RECT  0 62.928 0.084 62.952 ;
    END
  END wrq[75]
  PIN wrq[76]
    DIRECTION OUTPUT ;
    USE SIGNAL ;
    PORT
      LAYER M4 ;
        RECT  0 63.024 0.084 63.048 ;
    END
  END wrq[76]
  PIN wrq[77]
    DIRECTION OUTPUT ;
    USE SIGNAL ;
    PORT
      LAYER M4 ;
        RECT  0 63.12 0.084 63.144 ;
    END
  END wrq[77]
  PIN wrq[78]
    DIRECTION OUTPUT ;
    USE SIGNAL ;
    PORT
      LAYER M4 ;
        RECT  0 63.216 0.084 63.24 ;
    END
  END wrq[78]
  PIN wrq[79]
    DIRECTION OUTPUT ;
    USE SIGNAL ;
    PORT
      LAYER M4 ;
        RECT  0 63.312 0.084 63.336 ;
    END
  END wrq[79]
  PIN wrq[7]
    DIRECTION OUTPUT ;
    USE SIGNAL ;
    PORT
      LAYER M4 ;
        RECT  0 59.472 0.084 59.496 ;
    END
  END wrq[7]
  PIN wrq[80]
    DIRECTION OUTPUT ;
    USE SIGNAL ;
    PORT
      LAYER M4 ;
        RECT  0 63.408 0.084 63.432 ;
    END
  END wrq[80]
  PIN wrq[81]
    DIRECTION OUTPUT ;
    USE SIGNAL ;
    PORT
      LAYER M4 ;
        RECT  0 63.504 0.084 63.528 ;
    END
  END wrq[81]
  PIN wrq[82]
    DIRECTION OUTPUT ;
    USE SIGNAL ;
    PORT
      LAYER M4 ;
        RECT  0 63.6 0.084 63.624 ;
    END
  END wrq[82]
  PIN wrq[83]
    DIRECTION OUTPUT ;
    USE SIGNAL ;
    PORT
      LAYER M4 ;
        RECT  0 63.696 0.084 63.72 ;
    END
  END wrq[83]
  PIN wrq[84]
    DIRECTION OUTPUT ;
    USE SIGNAL ;
    PORT
      LAYER M4 ;
        RECT  0 63.792 0.084 63.816 ;
    END
  END wrq[84]
  PIN wrq[85]
    DIRECTION OUTPUT ;
    USE SIGNAL ;
    PORT
      LAYER M4 ;
        RECT  0 63.888 0.084 63.912 ;
    END
  END wrq[85]
  PIN wrq[86]
    DIRECTION OUTPUT ;
    USE SIGNAL ;
    PORT
      LAYER M4 ;
        RECT  0 63.984 0.084 64.008 ;
    END
  END wrq[86]
  PIN wrq[87]
    DIRECTION OUTPUT ;
    USE SIGNAL ;
    PORT
      LAYER M4 ;
        RECT  0 64.08 0.084 64.104 ;
    END
  END wrq[87]
  PIN wrq[88]
    DIRECTION OUTPUT ;
    USE SIGNAL ;
    PORT
      LAYER M4 ;
        RECT  0 64.176 0.084 64.2 ;
    END
  END wrq[88]
  PIN wrq[89]
    DIRECTION OUTPUT ;
    USE SIGNAL ;
    PORT
      LAYER M4 ;
        RECT  0 64.272 0.084 64.296 ;
    END
  END wrq[89]
  PIN wrq[8]
    DIRECTION OUTPUT ;
    USE SIGNAL ;
    PORT
      LAYER M4 ;
        RECT  0 59.568 0.084 59.592 ;
    END
  END wrq[8]
  PIN wrq[90]
    DIRECTION OUTPUT ;
    USE SIGNAL ;
    PORT
      LAYER M4 ;
        RECT  0 64.368 0.084 64.392 ;
    END
  END wrq[90]
  PIN wrq[91]
    DIRECTION OUTPUT ;
    USE SIGNAL ;
    PORT
      LAYER M4 ;
        RECT  0 64.464 0.084 64.488 ;
    END
  END wrq[91]
  PIN wrq[92]
    DIRECTION OUTPUT ;
    USE SIGNAL ;
    PORT
      LAYER M4 ;
        RECT  0 64.56 0.084 64.584 ;
    END
  END wrq[92]
  PIN wrq[93]
    DIRECTION OUTPUT ;
    USE SIGNAL ;
    PORT
      LAYER M4 ;
        RECT  0 64.656 0.084 64.68 ;
    END
  END wrq[93]
  PIN wrq[94]
    DIRECTION OUTPUT ;
    USE SIGNAL ;
    PORT
      LAYER M4 ;
        RECT  0 67.824 0.084 67.848 ;
    END
  END wrq[94]
  PIN wrq[95]
    DIRECTION OUTPUT ;
    USE SIGNAL ;
    PORT
      LAYER M4 ;
        RECT  0 67.92 0.084 67.944 ;
    END
  END wrq[95]
  PIN wrq[96]
    DIRECTION OUTPUT ;
    USE SIGNAL ;
    PORT
      LAYER M4 ;
        RECT  0 68.016 0.084 68.04 ;
    END
  END wrq[96]
  PIN wrq[97]
    DIRECTION OUTPUT ;
    USE SIGNAL ;
    PORT
      LAYER M4 ;
        RECT  0 68.112 0.084 68.136 ;
    END
  END wrq[97]
  PIN wrq[98]
    DIRECTION OUTPUT ;
    USE SIGNAL ;
    PORT
      LAYER M4 ;
        RECT  0 68.208 0.084 68.232 ;
    END
  END wrq[98]
  PIN wrq[99]
    DIRECTION OUTPUT ;
    USE SIGNAL ;
    PORT
      LAYER M4 ;
        RECT  0 68.304 0.084 68.328 ;
    END
  END wrq[99]
  PIN wrq[9]
    DIRECTION OUTPUT ;
    USE SIGNAL ;
    PORT
      LAYER M4 ;
        RECT  0 59.664 0.084 59.688 ;
    END
  END wrq[9]
  PIN wrq_cr[0]
    DIRECTION INPUT ;
    USE SIGNAL ;
    PORT
      LAYER M4 ;
        RECT  0 73.2 0.084 73.224 ;
    END
  END wrq_cr[0]
  PIN wrq_cr[1]
    DIRECTION INPUT ;
    USE SIGNAL ;
    PORT
      LAYER M4 ;
        RECT  0 73.296 0.084 73.32 ;
    END
  END wrq_cr[1]
  PIN wrq_cr[2]
    DIRECTION INPUT ;
    USE SIGNAL ;
    PORT
      LAYER M4 ;
        RECT  0 73.392 0.084 73.416 ;
    END
  END wrq_cr[2]
  PIN wrq_cr[3]
    DIRECTION INPUT ;
    USE SIGNAL ;
    PORT
      LAYER M4 ;
        RECT  0 73.488 0.084 73.512 ;
    END
  END wrq_cr[3]
  PIN wrq_cr[4]
    DIRECTION INPUT ;
    USE SIGNAL ;
    PORT
      LAYER M4 ;
        RECT  0 73.584 0.084 73.608 ;
    END
  END wrq_cr[4]
  PIN wrq_cr[5]
    DIRECTION INPUT ;
    USE SIGNAL ;
    PORT
      LAYER M4 ;
        RECT  0 73.68 0.084 73.704 ;
    END
  END wrq_cr[5]
  PIN wrq_cr[6]
    DIRECTION INPUT ;
    USE SIGNAL ;
    PORT
      LAYER M4 ;
        RECT  0 73.776 0.084 73.8 ;
    END
  END wrq_cr[6]
  PIN wrq_cr[7]
    DIRECTION INPUT ;
    USE SIGNAL ;
    PORT
      LAYER M4 ;
        RECT  0 73.872 0.084 73.896 ;
    END
  END wrq_cr[7]
  PIN VDD
    DIRECTION INOUT ;
    USE POWER ;
    PORT
      LAYER M5 ;
        RECT  83.592 2.151 83.712 75.609 ;
        RECT  78.192 2.151 78.312 75.609 ;
        RECT  72.792 2.151 72.912 75.609 ;
        RECT  67.392 2.151 67.512 75.609 ;
        RECT  61.992 2.151 62.112 75.609 ;
        RECT  56.592 2.151 56.712 75.609 ;
        RECT  51.192 2.151 51.312 75.609 ;
        RECT  45.792 2.151 45.912 75.609 ;
        RECT  40.392 2.151 40.512 75.609 ;
        RECT  34.992 2.151 35.112 75.609 ;
        RECT  29.592 2.151 29.712 75.609 ;
        RECT  24.192 2.151 24.312 75.609 ;
        RECT  18.792 2.151 18.912 75.609 ;
        RECT  13.392 2.151 13.512 75.609 ;
        RECT  7.992 2.151 8.112 75.609 ;
        RECT  2.592 2.151 2.712 75.609 ;
    END
  END VDD
  PIN VSS
    DIRECTION INOUT ;
    USE GROUND ;
    PORT
      LAYER M5 ;
        RECT  83.4 2.137 83.52 75.623 ;
        RECT  78 2.137 78.12 75.623 ;
        RECT  72.6 2.137 72.72 75.623 ;
        RECT  67.2 2.137 67.32 75.623 ;
        RECT  61.8 2.137 61.92 75.623 ;
        RECT  56.4 2.137 56.52 75.623 ;
        RECT  51 2.137 51.12 75.623 ;
        RECT  45.6 2.137 45.72 75.623 ;
        RECT  40.2 2.137 40.32 75.623 ;
        RECT  34.8 2.137 34.92 75.623 ;
        RECT  29.4 2.137 29.52 75.623 ;
        RECT  24 2.137 24.12 75.623 ;
        RECT  18.6 2.137 18.72 75.623 ;
        RECT  13.2 2.137 13.32 75.623 ;
        RECT  7.8 2.137 7.92 75.623 ;
        RECT  2.4 2.137 2.52 75.623 ;
    END
  END VSS
  # OT_OBS_CLOSED layer=M5 d_um=1.536 added=753
  OBS
    LAYER RVTN ;
     RECT  2.16 2.16 84.24 2.295 ;
     RECT  2.16 2.565 84.24 2.835 ;
     RECT  2.16 3.105 84.24 3.375 ;
     RECT  2.16 3.645 84.24 3.915 ;
     RECT  2.16 4.185 84.24 4.455 ;
     RECT  2.16 4.725 84.24 4.995 ;
     RECT  2.16 5.265 84.24 5.535 ;
     RECT  2.16 5.805 84.24 6.075 ;
     RECT  2.16 6.345 84.24 6.615 ;
     RECT  2.16 6.885 84.24 7.155 ;
     RECT  2.16 7.425 84.24 7.695 ;
     RECT  2.16 7.965 84.24 8.235 ;
     RECT  2.16 8.505 84.24 8.775 ;
     RECT  2.16 9.045 84.24 9.315 ;
     RECT  2.16 9.585 84.24 9.855 ;
     RECT  2.16 10.125 84.24 10.395 ;
     RECT  2.16 10.665 84.24 10.935 ;
     RECT  2.16 11.205 84.24 11.475 ;
     RECT  2.16 11.745 84.24 12.015 ;
     RECT  2.16 12.285 84.24 12.555 ;
     RECT  2.16 12.825 84.24 13.095 ;
     RECT  2.16 13.365 84.24 13.635 ;
     RECT  2.16 13.905 84.24 14.175 ;
     RECT  2.16 14.445 84.24 14.715 ;
     RECT  2.16 14.985 84.24 15.255 ;
     RECT  2.16 15.525 84.24 15.795 ;
     RECT  2.16 16.065 84.24 16.335 ;
     RECT  2.16 16.605 84.24 16.875 ;
     RECT  2.16 17.145 84.24 17.415 ;
     RECT  2.16 17.685 84.24 17.955 ;
     RECT  2.16 18.225 84.24 18.495 ;
     RECT  2.16 18.765 84.24 19.035 ;
     RECT  2.16 19.305 84.24 19.575 ;
     RECT  2.16 19.845 84.24 20.115 ;
     RECT  2.16 20.385 84.24 20.655 ;
     RECT  2.16 20.925 84.24 21.195 ;
     RECT  2.16 21.465 84.24 21.735 ;
     RECT  2.16 22.005 84.24 22.275 ;
     RECT  2.16 22.545 84.24 22.815 ;
     RECT  2.16 23.085 84.24 23.355 ;
     RECT  2.16 23.625 84.24 23.895 ;
     RECT  2.16 24.165 84.24 24.435 ;
     RECT  2.16 24.705 84.24 24.975 ;
     RECT  2.16 25.245 84.24 25.515 ;
     RECT  2.16 25.785 84.24 26.055 ;
     RECT  2.16 26.325 84.24 26.595 ;
     RECT  2.16 26.865 84.24 27.135 ;
     RECT  2.16 27.405 84.24 27.675 ;
     RECT  2.16 27.945 84.24 28.215 ;
     RECT  2.16 28.485 84.24 28.755 ;
     RECT  2.16 29.025 84.24 29.295 ;
     RECT  2.16 29.565 84.24 29.835 ;
     RECT  2.16 30.105 84.24 30.375 ;
     RECT  2.16 30.645 84.24 30.915 ;
     RECT  2.16 31.185 84.24 31.455 ;
     RECT  2.16 31.725 84.24 31.995 ;
     RECT  2.16 32.265 84.24 32.535 ;
     RECT  2.16 32.805 84.24 33.075 ;
     RECT  2.16 33.345 84.24 33.615 ;
     RECT  2.16 33.885 84.24 34.155 ;
     RECT  2.16 34.425 84.24 34.695 ;
     RECT  2.16 34.965 84.24 35.235 ;
     RECT  2.16 35.505 84.24 35.775 ;
     RECT  2.16 36.045 84.24 36.315 ;
     RECT  2.16 36.585 84.24 36.855 ;
     RECT  2.16 37.125 84.24 37.395 ;
     RECT  2.16 37.665 84.24 37.935 ;
     RECT  2.16 38.205 84.24 38.475 ;
     RECT  2.16 38.745 84.24 39.015 ;
     RECT  2.16 39.285 84.24 39.555 ;
     RECT  2.16 39.825 84.24 40.095 ;
     RECT  2.16 40.365 84.24 40.635 ;
     RECT  2.16 40.905 84.24 41.175 ;
     RECT  2.16 41.445 84.24 41.715 ;
     RECT  2.16 41.985 84.24 42.255 ;
     RECT  2.16 42.525 84.24 42.795 ;
     RECT  2.16 43.065 84.24 43.335 ;
     RECT  2.16 43.605 84.24 43.875 ;
     RECT  2.16 44.145 84.24 44.415 ;
     RECT  2.16 44.685 84.24 44.955 ;
     RECT  2.16 45.225 84.24 45.495 ;
     RECT  2.16 45.765 84.24 46.035 ;
     RECT  2.16 46.305 84.24 46.575 ;
     RECT  2.16 46.845 84.24 47.115 ;
     RECT  2.16 47.385 84.24 47.655 ;
     RECT  2.16 47.925 84.24 48.195 ;
     RECT  2.16 48.465 84.24 48.735 ;
     RECT  2.16 49.005 84.24 49.275 ;
     RECT  2.16 49.545 84.24 49.815 ;
     RECT  2.16 50.085 84.24 50.355 ;
     RECT  2.16 50.625 84.24 50.895 ;
     RECT  2.16 51.165 84.24 51.435 ;
     RECT  2.16 51.705 84.24 51.975 ;
     RECT  2.16 52.245 84.24 52.515 ;
     RECT  2.16 52.785 84.24 53.055 ;
     RECT  2.16 53.325 84.24 53.595 ;
     RECT  2.16 53.865 84.24 54.135 ;
     RECT  2.16 54.405 84.24 54.675 ;
     RECT  2.16 54.945 84.24 55.215 ;
     RECT  2.16 55.485 84.24 55.755 ;
     RECT  2.16 56.025 84.24 56.295 ;
     RECT  2.16 56.565 84.24 56.835 ;
     RECT  2.16 57.105 84.24 57.375 ;
     RECT  2.16 57.645 84.24 57.915 ;
     RECT  2.16 58.185 84.24 58.455 ;
     RECT  2.16 58.725 84.24 58.995 ;
     RECT  2.16 59.265 84.24 59.535 ;
     RECT  2.16 59.805 84.24 60.075 ;
     RECT  2.16 60.345 84.24 60.615 ;
     RECT  2.16 60.885 84.24 61.155 ;
     RECT  2.16 61.425 84.24 61.695 ;
     RECT  2.16 61.965 84.24 62.235 ;
     RECT  2.16 62.505 84.24 62.775 ;
     RECT  2.16 63.045 84.24 63.315 ;
     RECT  2.16 63.585 84.24 63.855 ;
     RECT  2.16 64.125 84.24 64.395 ;
     RECT  2.16 64.665 84.24 64.935 ;
     RECT  2.16 65.205 84.24 65.475 ;
     RECT  2.16 65.745 84.24 66.015 ;
     RECT  2.16 66.285 84.24 66.555 ;
     RECT  2.16 66.825 84.24 67.095 ;
     RECT  2.16 67.365 84.24 67.635 ;
     RECT  2.16 67.905 84.24 68.175 ;
     RECT  2.16 68.445 84.24 68.715 ;
     RECT  2.16 68.985 84.24 69.255 ;
     RECT  2.16 69.525 84.24 69.795 ;
     RECT  2.16 70.065 84.24 70.335 ;
     RECT  2.16 70.605 84.24 70.875 ;
     RECT  2.16 71.145 84.24 71.415 ;
     RECT  2.16 71.685 84.24 71.955 ;
     RECT  2.16 72.225 84.24 72.495 ;
     RECT  2.16 72.765 84.24 73.035 ;
     RECT  2.16 73.305 84.24 73.575 ;
     RECT  2.16 73.845 84.24 74.115 ;
     RECT  2.16 74.385 84.24 74.655 ;
     RECT  2.16 74.925 84.24 75.195 ;
     RECT  2.16 75.465 84.24 75.6 ;
    LAYER RVTP ;
     RECT  2.16 2.295 84.24 2.565 ;
     RECT  2.16 2.835 84.24 3.105 ;
     RECT  2.16 3.375 84.24 3.645 ;
     RECT  2.16 3.915 84.24 4.185 ;
     RECT  2.16 4.455 84.24 4.725 ;
     RECT  2.16 4.995 84.24 5.265 ;
     RECT  2.16 5.535 84.24 5.805 ;
     RECT  2.16 6.075 84.24 6.345 ;
     RECT  2.16 6.615 84.24 6.885 ;
     RECT  2.16 7.155 84.24 7.425 ;
     RECT  2.16 7.695 84.24 7.965 ;
     RECT  2.16 8.235 84.24 8.505 ;
     RECT  2.16 8.775 84.24 9.045 ;
     RECT  2.16 9.315 84.24 9.585 ;
     RECT  2.16 9.855 84.24 10.125 ;
     RECT  2.16 10.395 84.24 10.665 ;
     RECT  2.16 10.935 84.24 11.205 ;
     RECT  2.16 11.475 84.24 11.745 ;
     RECT  2.16 12.015 84.24 12.285 ;
     RECT  2.16 12.555 84.24 12.825 ;
     RECT  2.16 13.095 84.24 13.365 ;
     RECT  2.16 13.635 84.24 13.905 ;
     RECT  2.16 14.175 84.24 14.445 ;
     RECT  2.16 14.715 84.24 14.985 ;
     RECT  2.16 15.255 84.24 15.525 ;
     RECT  2.16 15.795 84.24 16.065 ;
     RECT  2.16 16.335 84.24 16.605 ;
     RECT  2.16 16.875 84.24 17.145 ;
     RECT  2.16 17.415 84.24 17.685 ;
     RECT  2.16 17.955 84.24 18.225 ;
     RECT  2.16 18.495 84.24 18.765 ;
     RECT  2.16 19.035 84.24 19.305 ;
     RECT  2.16 19.575 84.24 19.845 ;
     RECT  2.16 20.115 84.24 20.385 ;
     RECT  2.16 20.655 84.24 20.925 ;
     RECT  2.16 21.195 84.24 21.465 ;
     RECT  2.16 21.735 84.24 22.005 ;
     RECT  2.16 22.275 84.24 22.545 ;
     RECT  2.16 22.815 84.24 23.085 ;
     RECT  2.16 23.355 84.24 23.625 ;
     RECT  2.16 23.895 84.24 24.165 ;
     RECT  2.16 24.435 84.24 24.705 ;
     RECT  2.16 24.975 84.24 25.245 ;
     RECT  2.16 25.515 84.24 25.785 ;
     RECT  2.16 26.055 84.24 26.325 ;
     RECT  2.16 26.595 84.24 26.865 ;
     RECT  2.16 27.135 84.24 27.405 ;
     RECT  2.16 27.675 84.24 27.945 ;
     RECT  2.16 28.215 84.24 28.485 ;
     RECT  2.16 28.755 84.24 29.025 ;
     RECT  2.16 29.295 84.24 29.565 ;
     RECT  2.16 29.835 84.24 30.105 ;
     RECT  2.16 30.375 84.24 30.645 ;
     RECT  2.16 30.915 84.24 31.185 ;
     RECT  2.16 31.455 84.24 31.725 ;
     RECT  2.16 31.995 84.24 32.265 ;
     RECT  2.16 32.535 84.24 32.805 ;
     RECT  2.16 33.075 84.24 33.345 ;
     RECT  2.16 33.615 84.24 33.885 ;
     RECT  2.16 34.155 84.24 34.425 ;
     RECT  2.16 34.695 84.24 34.965 ;
     RECT  2.16 35.235 84.24 35.505 ;
     RECT  2.16 35.775 84.24 36.045 ;
     RECT  2.16 36.315 84.24 36.585 ;
     RECT  2.16 36.855 84.24 37.125 ;
     RECT  2.16 37.395 84.24 37.665 ;
     RECT  2.16 37.935 84.24 38.205 ;
     RECT  2.16 38.475 84.24 38.745 ;
     RECT  2.16 39.015 84.24 39.285 ;
     RECT  2.16 39.555 84.24 39.825 ;
     RECT  2.16 40.095 84.24 40.365 ;
     RECT  2.16 40.635 84.24 40.905 ;
     RECT  2.16 41.175 84.24 41.445 ;
     RECT  2.16 41.715 84.24 41.985 ;
     RECT  2.16 42.255 84.24 42.525 ;
     RECT  2.16 42.795 84.24 43.065 ;
     RECT  2.16 43.335 84.24 43.605 ;
     RECT  2.16 43.875 84.24 44.145 ;
     RECT  2.16 44.415 84.24 44.685 ;
     RECT  2.16 44.955 84.24 45.225 ;
     RECT  2.16 45.495 84.24 45.765 ;
     RECT  2.16 46.035 84.24 46.305 ;
     RECT  2.16 46.575 84.24 46.845 ;
     RECT  2.16 47.115 84.24 47.385 ;
     RECT  2.16 47.655 84.24 47.925 ;
     RECT  2.16 48.195 84.24 48.465 ;
     RECT  2.16 48.735 84.24 49.005 ;
     RECT  2.16 49.275 84.24 49.545 ;
     RECT  2.16 49.815 84.24 50.085 ;
     RECT  2.16 50.355 84.24 50.625 ;
     RECT  2.16 50.895 84.24 51.165 ;
     RECT  2.16 51.435 84.24 51.705 ;
     RECT  2.16 51.975 84.24 52.245 ;
     RECT  2.16 52.515 84.24 52.785 ;
     RECT  2.16 53.055 84.24 53.325 ;
     RECT  2.16 53.595 84.24 53.865 ;
     RECT  2.16 54.135 84.24 54.405 ;
     RECT  2.16 54.675 84.24 54.945 ;
     RECT  2.16 55.215 84.24 55.485 ;
     RECT  2.16 55.755 84.24 56.025 ;
     RECT  2.16 56.295 84.24 56.565 ;
     RECT  2.16 56.835 84.24 57.105 ;
     RECT  2.16 57.375 84.24 57.645 ;
     RECT  2.16 57.915 84.24 58.185 ;
     RECT  2.16 58.455 84.24 58.725 ;
     RECT  2.16 58.995 84.24 59.265 ;
     RECT  2.16 59.535 84.24 59.805 ;
     RECT  2.16 60.075 84.24 60.345 ;
     RECT  2.16 60.615 84.24 60.885 ;
     RECT  2.16 61.155 84.24 61.425 ;
     RECT  2.16 61.695 84.24 61.965 ;
     RECT  2.16 62.235 84.24 62.505 ;
     RECT  2.16 62.775 84.24 63.045 ;
     RECT  2.16 63.315 84.24 63.585 ;
     RECT  2.16 63.855 84.24 64.125 ;
     RECT  2.16 64.395 84.24 64.665 ;
     RECT  2.16 64.935 84.24 65.205 ;
     RECT  2.16 65.475 84.24 65.745 ;
     RECT  2.16 66.015 84.24 66.285 ;
     RECT  2.16 66.555 84.24 66.825 ;
     RECT  2.16 67.095 84.24 67.365 ;
     RECT  2.16 67.635 84.24 67.905 ;
     RECT  2.16 68.175 84.24 68.445 ;
     RECT  2.16 68.715 84.24 68.985 ;
     RECT  2.16 69.255 84.24 69.525 ;
     RECT  2.16 69.795 84.24 70.065 ;
     RECT  2.16 70.335 84.24 70.605 ;
     RECT  2.16 70.875 84.24 71.145 ;
     RECT  2.16 71.415 84.24 71.685 ;
     RECT  2.16 71.955 84.24 72.225 ;
     RECT  2.16 72.495 84.24 72.765 ;
     RECT  2.16 73.035 84.24 73.305 ;
     RECT  2.16 73.575 84.24 73.845 ;
     RECT  2.16 74.115 84.24 74.385 ;
     RECT  2.16 74.655 84.24 74.925 ;
     RECT  2.16 75.195 84.24 75.465 ;
    LAYER M1 ;
     RECT  2.16 2.151 84.24 75.609 ;
    LAYER M2 ;
     RECT  0.067 59.274 0.103 59.292 ;
     RECT  0.031 71.766 0.103 71.784 ;
     RECT  0.031 68.526 0.131 68.544 ;
     RECT  0.103 58.896 0.139 59.292 ;
     RECT  0.103 60.966 0.139 60.984 ;
     RECT  0.103 62.406 0.139 62.424 ;
     RECT  0.103 63.252 0.139 63.27 ;
     RECT  0.103 64.026 0.139 64.044 ;
     RECT  0.103 69.534 0.139 69.552 ;
     RECT  0.139 60.966 0.175 62.424 ;
     RECT  0.139 63.216 0.175 64.044 ;
     RECT  0.103 65.826 0.203 66.429 ;
     RECT  0.175 56.916 0.211 56.934 ;
     RECT  0.103 71.586 0.211 71.784 ;
     RECT  0.175 60.966 0.239 64.386 ;
     RECT  0.203 65.826 0.239 65.844 ;
     RECT  0.211 56.376 0.247 56.934 ;
     RECT  0.211 71.586 0.247 72.144 ;
     RECT  0.139 58.698 0.319 59.292 ;
     RECT  0.247 56.376 0.355 57.294 ;
     RECT  0.067 54.486 0.427 54.504 ;
     RECT  0.427 54.486 0.499 54.864 ;
     RECT  0.355 55.656 0.499 57.294 ;
     RECT  0.319 58.122 0.535 59.292 ;
     RECT  0.535 58.122 0.571 59.526 ;
     RECT  0.247 71.316 0.571 72.144 ;
     RECT  0.499 54.486 0.859 57.294 ;
     RECT  0.571 58.122 0.859 59.724 ;
     RECT  0.031 52.992 1.435 53.01 ;
     RECT  0.239 60.966 1.723 61.569 ;
     RECT  1.723 68.076 1.759 68.094 ;
     RECT  0.139 69.534 1.759 69.984 ;
     RECT  0.571 70.92 1.759 72.144 ;
     RECT  1.759 68.076 1.867 68.634 ;
     RECT  1.867 67.878 2.155 68.634 ;
     RECT  1.435 52.992 2.16 53.514 ;
     RECT  0.859 54.486 2.16 59.724 ;
     RECT  1.723 60.786 2.16 61.569 ;
     RECT  0.239 62.316 2.16 64.386 ;
     RECT  2.155 67.806 2.16 68.634 ;
     RECT  1.759 69.534 2.16 72.144 ;
     RECT  0.175 72.936 2.16 72.954 ;
     RECT  2.155 74.628 2.16 74.646 ;
     RECT  0.535 75.474 2.16 75.492 ;
     RECT  2.16 2.151 8.563 75.609 ;
     RECT  8.563 2.106 9.959 75.609 ;
     RECT  9.959 2.151 11.371 75.609 ;
     RECT  11.371 2.106 12.047 75.609 ;
     RECT  12.047 2.151 14.215 75.609 ;
     RECT  16.195 1.152 16.295 1.17 ;
     RECT  14.215 2.034 19.715 75.609 ;
     RECT  19.715 2.106 22.315 75.609 ;
     RECT  22.315 2.07 22.675 75.609 ;
     RECT  22.675 2.034 23.171 75.609 ;
     RECT  23.171 2.07 23.855 75.609 ;
     RECT  23.855 2.106 38.795 75.609 ;
     RECT  38.795 2.151 41.827 75.609 ;
     RECT  41.827 2.106 42.187 75.609 ;
     RECT  42.187 2.106 42.287 75.654 ;
     RECT  42.287 2.151 42.647 75.654 ;
     RECT  45.103 1.152 45.203 1.17 ;
     RECT  42.647 2.151 56.371 75.609 ;
     RECT  56.371 2.106 56.551 75.609 ;
     RECT  56.551 2.07 56.587 75.609 ;
     RECT  56.587 2.034 56.903 75.609 ;
     RECT  56.903 2.07 57.083 75.609 ;
     RECT  57.083 2.106 57.983 75.609 ;
     RECT  57.983 2.151 61.735 75.609 ;
     RECT  61.735 2.151 62.203 75.654 ;
     RECT  62.203 2.106 62.555 75.654 ;
     RECT  62.555 2.151 62.843 75.654 ;
     RECT  62.843 2.151 65.731 75.609 ;
     RECT  65.731 2.106 66.119 75.609 ;
     RECT  66.119 2.151 66.775 75.609 ;
     RECT  66.775 2.151 67.919 75.654 ;
     RECT  67.919 2.151 69.007 75.609 ;
     RECT  69.007 2.151 72.247 75.654 ;
     RECT  72.247 2.106 72.563 75.654 ;
     RECT  72.563 2.151 73.247 75.654 ;
     RECT  73.247 2.151 74.299 75.609 ;
     RECT  74.299 2.106 75.335 75.609 ;
     RECT  75.335 2.151 84.24 75.609 ;
    LAYER M3 ;
     RECT  13.68 0.091 13.698 0.139 ;
     RECT  14.688 0.091 14.706 0.139 ;
     RECT  45.108 0.091 45.126 0.139 ;
     RECT  58.716 0.091 59.31 0.139 ;
     RECT  72.936 0.091 73.638 0.187 ;
     RECT  70.128 0.139 70.146 0.427 ;
     RECT  71.388 0.091 71.982 0.427 ;
     RECT  9.36 0.091 9.378 0.475 ;
     RECT  10.26 0.427 10.278 0.475 ;
     RECT  11.016 0.091 11.034 0.475 ;
     RECT  9.36 0.475 10.278 0.523 ;
     RECT  11.016 0.475 11.574 0.523 ;
     RECT  12.348 0.091 12.582 0.523 ;
     RECT  58.716 0.139 59.382 0.523 ;
     RECT  60.696 0.091 61.038 0.523 ;
     RECT  62.028 0.091 62.046 0.523 ;
     RECT  62.892 0.091 63.27 0.523 ;
     RECT  8.856 0.523 10.278 0.571 ;
     RECT  11.016 0.523 12.942 0.571 ;
     RECT  13.68 0.139 14.706 0.571 ;
     RECT  43.308 0.091 43.65 0.571 ;
     RECT  44.82 0.139 45.126 0.571 ;
     RECT  51.984 0.091 52.002 0.571 ;
     RECT  60.516 0.523 63.27 0.571 ;
     RECT  70.128 0.427 71.982 0.571 ;
     RECT  72.9 0.187 73.638 0.571 ;
     RECT  44.82 0.571 45.162 1.099 ;
     RECT  16.2 0.091 16.218 1.147 ;
     RECT  44.424 1.099 45.162 1.147 ;
     RECT  8.856 0.571 12.942 1.723 ;
     RECT  13.68 0.571 15.426 1.723 ;
     RECT  16.2 1.147 16.29 1.723 ;
     RECT  42.264 0.571 43.65 1.723 ;
     RECT  44.424 1.147 45.198 1.723 ;
     RECT  58.14 0.523 59.382 1.723 ;
     RECT  60.444 0.571 63.27 1.723 ;
     RECT  42.264 1.723 45.198 1.771 ;
     RECT  42.264 1.771 45.846 1.819 ;
     RECT  58.14 1.723 64.098 1.819 ;
     RECT  22.68 2.029 23.166 2.065 ;
     RECT  56.592 2.029 56.898 2.065 ;
     RECT  8.856 1.723 16.83 2.101 ;
     RECT  19.692 2.029 19.71 2.101 ;
     RECT  42.192 1.819 45.846 2.101 ;
     RECT  56.556 2.065 57.078 2.101 ;
     RECT  58.14 1.819 64.134 2.101 ;
     RECT  65.052 0.091 65.07 2.101 ;
     RECT  70.128 0.571 73.638 2.101 ;
     RECT  74.592 0.139 74.61 2.101 ;
     RECT  8.568 2.101 16.83 2.143 ;
     RECT  22.32 2.065 23.85 2.143 ;
     RECT  51.48 0.571 52.002 2.143 ;
     RECT  17.64 2.101 17.658 2.191 ;
     RECT  41.832 2.101 45.846 2.191 ;
     RECT  57.96 2.101 64.134 2.191 ;
     RECT  65.052 2.101 66.114 2.191 ;
     RECT  7.815 2.143 16.83 2.227 ;
     RECT  22.32 2.143 24.105 2.227 ;
     RECT  25.236 2.191 25.254 2.227 ;
     RECT  29.415 2.143 29.505 2.227 ;
     RECT  41.04 2.191 41.058 2.227 ;
     RECT  41.832 2.191 46.134 2.227 ;
     RECT  57.96 2.191 66.114 2.227 ;
     RECT  70.128 2.101 75.33 2.227 ;
     RECT  7.704 2.227 16.83 2.251 ;
     RECT  34.815 2.143 34.905 2.251 ;
     RECT  37.368 2.191 37.386 2.251 ;
     RECT  40.215 2.143 40.305 2.251 ;
     RECT  41.04 2.227 46.494 2.251 ;
     RECT  51.015 2.143 52.002 2.251 ;
     RECT  55.26 2.227 55.278 2.251 ;
     RECT  7.308 2.251 16.83 2.263 ;
     RECT  17.64 2.191 17.694 2.263 ;
     RECT  18.615 2.143 18.705 2.263 ;
     RECT  26.424 2.227 26.694 2.263 ;
     RECT  28.44 2.191 28.458 2.263 ;
     RECT  38.772 2.101 38.79 2.263 ;
     RECT  40.215 2.251 46.782 2.263 ;
     RECT  47.556 2.227 47.574 2.263 ;
     RECT  50.616 2.251 52.002 2.263 ;
     RECT  56.376 2.101 57.078 2.263 ;
     RECT  67.215 2.143 67.305 2.263 ;
     RECT  30.276 2.227 30.906 2.299 ;
     RECT  32.004 2.227 32.022 2.299 ;
     RECT  40.215 2.263 47.898 2.299 ;
     RECT  54.612 2.251 55.386 2.299 ;
     RECT  19.62 2.101 19.71 2.335 ;
     RECT  20.592 2.299 20.61 2.335 ;
     RECT  28.332 2.263 28.458 2.335 ;
     RECT  52.74 2.191 52.758 2.335 ;
     RECT  19.62 2.335 19.818 2.347 ;
     RECT  20.592 2.335 20.718 2.347 ;
     RECT  7.308 2.263 18.705 2.371 ;
     RECT  19.62 2.347 20.718 2.371 ;
     RECT  21.456 2.263 21.474 2.371 ;
     RECT  22.32 2.227 25.254 2.371 ;
     RECT  30.276 2.299 32.022 2.371 ;
     RECT  33.516 2.227 33.534 2.371 ;
     RECT  34.38 2.251 34.905 2.371 ;
     RECT  36.9 2.251 37.386 2.371 ;
     RECT  38.196 2.263 38.79 2.371 ;
     RECT  52.74 2.335 52.794 2.371 ;
     RECT  53.82 2.299 55.386 2.371 ;
     RECT  56.16 2.263 57.078 2.371 ;
     RECT  57.852 2.227 66.114 2.371 ;
     RECT  67.032 2.263 67.305 2.371 ;
     RECT  68.22 2.251 68.238 2.371 ;
     RECT  2.415 2.143 2.505 2.413 ;
     RECT  29.232 2.227 29.505 2.413 ;
     RECT  30.276 2.371 34.905 2.413 ;
     RECT  57.852 2.371 67.305 2.413 ;
     RECT  78.015 2.143 78.105 2.413 ;
     RECT  83.415 2.143 83.505 2.413 ;
     RECT  26.424 2.263 26.838 2.443 ;
     RECT  27.756 2.335 28.458 2.443 ;
     RECT  27.756 2.443 28.494 2.461 ;
     RECT  29.232 2.413 35.097 2.461 ;
     RECT  36.828 2.371 39.078 2.461 ;
     RECT  40.215 2.299 48.546 2.461 ;
     RECT  50.22 2.263 52.002 2.461 ;
     RECT  52.74 2.371 53.082 2.461 ;
     RECT  53.82 2.371 57.078 2.461 ;
     RECT  57.852 2.413 67.497 2.461 ;
     RECT  70.128 2.227 75.402 2.461 ;
     RECT  26.388 2.443 26.838 2.491 ;
     RECT  40.215 2.461 49.014 2.491 ;
     RECT  6.012 2.371 6.03 2.497 ;
     RECT  27.612 2.461 28.494 2.497 ;
     RECT  29.232 2.461 35.298 2.497 ;
     RECT  50.22 2.461 53.082 2.497 ;
     RECT  27.612 2.497 35.298 2.533 ;
     RECT  36.252 2.461 39.078 2.533 ;
     RECT  49.968 2.497 53.082 2.533 ;
     RECT  53.82 2.461 67.497 2.533 ;
     RECT  6.012 2.497 6.246 2.569 ;
     RECT  7.308 2.371 25.254 2.569 ;
     RECT  27.612 2.533 39.078 2.569 ;
     RECT  39.996 2.491 49.014 2.569 ;
     RECT  68.22 2.371 69.066 2.569 ;
     RECT  69.984 2.461 75.402 2.569 ;
     RECT  26.028 2.491 26.838 2.587 ;
     RECT  27.612 2.569 49.014 2.587 ;
     RECT  26.028 2.587 49.014 2.605 ;
     RECT  49.752 2.533 67.497 2.605 ;
     RECT  68.22 2.569 69.174 2.605 ;
     RECT  69.984 2.569 75.906 2.605 ;
     RECT  5.508 2.569 25.254 2.641 ;
     RECT  26.028 2.605 67.497 2.641 ;
     RECT  68.22 2.605 75.906 2.641 ;
     RECT  5.4 2.641 25.254 2.731 ;
     RECT  26.028 2.641 76.446 2.731 ;
     RECT  78.015 2.413 78.297 2.731 ;
     RECT  78.015 2.731 78.534 2.767 ;
     RECT  5.4 2.731 76.446 3.001 ;
     RECT  5.4 3.001 76.806 3.211 ;
     RECT  77.58 2.767 78.534 3.211 ;
     RECT  2.415 2.413 2.697 3.451 ;
     RECT  4.5 3.271 4.518 3.451 ;
     RECT  5.4 3.211 78.534 3.451 ;
     RECT  79.992 3.721 80.622 3.811 ;
     RECT  2.415 3.451 78.534 3.847 ;
     RECT  79.992 3.811 80.658 3.847 ;
     RECT  81.396 3.343 81.414 3.847 ;
     RECT  2.415 3.847 78.642 3.919 ;
     RECT  2.415 3.919 78.678 3.955 ;
     RECT  2.415 3.955 79.11 3.991 ;
     RECT  79.992 3.847 81.414 3.991 ;
     RECT  2.415 3.991 81.414 4.531 ;
     RECT  2.415 4.531 81.45 4.621 ;
     RECT  2.415 4.621 81.774 4.747 ;
     RECT  2.376 4.747 81.774 5.341 ;
     RECT  2.376 5.341 82.17 6.283 ;
     RECT  2.376 6.283 82.674 6.691 ;
     RECT  83.415 2.413 83.697 6.691 ;
     RECT  2.376 6.691 83.697 7.123 ;
     RECT  2.304 7.123 83.697 7.321 ;
     RECT  2.304 7.321 83.97 7.889 ;
     RECT  2.304 7.889 83.862 7.925 ;
     RECT  2.304 7.925 83.79 8.851 ;
     RECT  2.304 8.851 83.862 9.005 ;
     RECT  2.304 9.005 83.697 10.741 ;
     RECT  2.304 10.741 84.114 11.003 ;
     RECT  2.304 11.003 83.697 12.631 ;
     RECT  2.304 12.631 83.754 13.019 ;
     RECT  2.304 13.019 83.697 14.791 ;
     RECT  2.304 14.791 84.042 15.179 ;
     RECT  2.304 15.179 83.934 15.449 ;
     RECT  2.34 15.449 83.934 16.259 ;
     RECT  2.34 16.259 83.862 16.501 ;
     RECT  2.304 16.501 83.862 17.105 ;
     RECT  2.304 17.105 83.697 18.031 ;
     RECT  2.304 18.031 84.042 18.841 ;
     RECT  2.232 18.841 84.042 19.499 ;
     RECT  2.232 19.499 83.934 19.571 ;
     RECT  2.304 19.571 83.934 20.075 ;
     RECT  2.304 20.075 83.697 21.541 ;
     RECT  2.304 21.541 83.97 22.315 ;
     RECT  2.304 22.315 84.114 23.009 ;
     RECT  2.304 23.009 83.934 23.585 ;
     RECT  2.304 23.585 83.697 24.089 ;
     RECT  2.376 24.089 83.697 24.331 ;
     RECT  2.376 24.331 83.934 24.899 ;
     RECT  2.376 24.899 83.826 24.935 ;
     RECT  2.376 24.935 83.754 26.015 ;
     RECT  2.415 26.015 83.754 26.131 ;
     RECT  2.415 26.131 83.934 26.519 ;
     RECT  2.415 26.519 83.79 26.555 ;
     RECT  2.415 26.555 83.697 27.373 ;
     RECT  2.376 27.373 83.697 27.751 ;
     RECT  2.376 27.751 83.754 27.877 ;
     RECT  2.34 27.877 83.754 27.917 ;
     RECT  2.415 27.917 83.754 27.985 ;
     RECT  2.415 27.985 84.114 28.139 ;
     RECT  2.415 28.139 84.042 28.949 ;
     RECT  2.415 28.949 83.898 28.985 ;
     RECT  2.415 28.985 83.862 29.371 ;
     RECT  2.304 29.371 83.862 30.029 ;
     RECT  2.304 30.029 83.754 30.065 ;
     RECT  2.304 30.065 83.697 31.261 ;
     RECT  2.304 31.261 84.114 31.523 ;
     RECT  2.304 31.523 83.97 32.575 ;
     RECT  2.304 32.575 84.114 33.881 ;
     RECT  2.304 33.881 83.697 36.013 ;
     RECT  2.304 36.013 83.826 36.815 ;
     RECT  2.34 36.815 83.826 37.471 ;
     RECT  2.34 37.471 84.042 37.859 ;
     RECT  2.34 37.859 83.898 37.895 ;
     RECT  2.34 37.895 83.697 38.669 ;
     RECT  2.415 38.669 83.697 38.911 ;
     RECT  2.415 38.911 83.97 39.479 ;
     RECT  2.415 39.479 83.934 40.369 ;
     RECT  2.34 40.369 83.934 40.937 ;
     RECT  2.376 40.937 83.934 41.135 ;
     RECT  2.376 41.135 83.697 41.698 ;
     RECT  2.415 41.698 83.697 42.331 ;
     RECT  2.415 42.331 83.97 42.719 ;
     RECT  2.415 42.719 83.862 42.755 ;
     RECT  2.415 42.755 83.79 43.259 ;
     RECT  2.415 43.259 83.697 43.339 ;
     RECT  2.376 43.339 83.697 44.149 ;
     RECT  2.304 44.149 83.697 44.311 ;
     RECT  2.304 44.311 83.826 45.535 ;
     RECT  2.304 45.535 84.006 46.075 ;
     RECT  2.304 46.075 84.114 47.579 ;
     RECT  2.304 47.579 83.697 48.541 ;
     RECT  2.304 48.541 83.862 48.929 ;
     RECT  2.34 48.929 83.862 49.351 ;
     RECT  2.34 49.351 83.898 49.505 ;
     RECT  2.34 49.505 83.697 50.431 ;
     RECT  2.232 50.431 83.697 50.549 ;
     RECT  2.304 50.549 83.697 51.061 ;
     RECT  2.304 51.061 83.754 51.367 ;
     RECT  2.304 51.367 83.898 52.015 ;
     RECT  2.304 52.015 84.114 52.169 ;
     RECT  2.304 52.169 83.934 52.681 ;
     RECT  2.232 52.681 83.934 52.745 ;
     RECT  2.232 52.745 83.697 53.563 ;
     RECT  2.232 53.563 83.79 54.445 ;
     RECT  0.036 52.987 0.054 54.481 ;
     RECT  1.44 53.491 1.458 54.643 ;
     RECT  2.232 54.445 84.114 54.643 ;
     RECT  0.036 54.481 0.09 54.841 ;
     RECT  1.44 54.643 84.114 54.869 ;
     RECT  0.036 54.841 0.45 55.183 ;
     RECT  0.036 55.183 0.522 55.489 ;
     RECT  1.44 54.869 83.697 55.489 ;
     RECT  0.036 55.489 83.697 56.285 ;
     RECT  50.508 56.285 83.697 56.335 ;
     RECT  50.508 56.335 84.114 56.489 ;
     RECT  50.508 56.489 83.862 57.065 ;
     RECT  0.036 56.285 49.77 57.073 ;
     RECT  50.508 57.065 83.697 57.073 ;
     RECT  0.036 57.073 83.697 57.991 ;
     RECT  0.036 57.991 83.79 58.157 ;
     RECT  0.072 58.157 83.79 58.253 ;
     RECT  48.852 58.253 83.79 58.261 ;
     RECT  48.852 58.261 84.042 58.649 ;
     RECT  48.852 58.649 83.898 58.721 ;
     RECT  0.072 58.253 48.114 59.117 ;
     RECT  2.304 59.117 48.114 59.161 ;
     RECT  0.072 59.117 1.494 59.297 ;
     RECT  2.304 59.161 48.294 59.539 ;
     RECT  49.032 58.721 83.898 59.539 ;
     RECT  2.304 59.539 83.898 59.971 ;
     RECT  2.232 59.971 83.898 60.035 ;
     RECT  0.108 59.297 1.494 60.781 ;
     RECT  2.232 60.035 83.754 60.781 ;
     RECT  0.108 60.781 83.754 60.961 ;
     RECT  0.108 60.961 83.826 61.223 ;
     RECT  0.108 61.223 83.697 61.229 ;
     RECT  0.144 61.229 83.697 62.401 ;
     RECT  0.108 62.401 83.697 63.245 ;
     RECT  1.44 63.245 83.697 63.275 ;
     RECT  2.268 63.275 83.697 63.661 ;
     RECT  2.268 63.661 83.898 63.725 ;
     RECT  1.44 63.275 1.458 63.917 ;
     RECT  2.304 63.725 83.898 64.049 ;
     RECT  2.304 64.049 83.826 64.085 ;
     RECT  0.108 63.245 0.234 64.123 ;
     RECT  0.108 64.123 0.306 64.301 ;
     RECT  2.304 64.085 83.697 64.355 ;
     RECT  2.304 64.355 14.994 64.499 ;
     RECT  0.108 64.301 0.234 64.589 ;
     RECT  0.108 64.589 0.198 64.781 ;
     RECT  0.144 64.781 0.198 64.877 ;
     RECT  0.18 64.877 0.198 64.973 ;
     RECT  2.34 64.499 14.994 65.281 ;
     RECT  2.34 65.281 15.03 65.323 ;
     RECT  2.268 65.323 15.03 65.407 ;
     RECT  15.804 64.355 83.697 65.407 ;
     RECT  2.268 65.407 83.697 65.669 ;
     RECT  0.324 65.419 0.342 65.707 ;
     RECT  0.144 65.707 0.342 65.803 ;
     RECT  0.144 65.803 0.378 65.821 ;
     RECT  0.108 65.821 0.378 65.851 ;
     RECT  0.108 65.851 0.45 65.981 ;
     RECT  0.108 65.981 0.378 66.029 ;
     RECT  0.108 66.029 0.342 66.317 ;
     RECT  2.304 65.669 83.697 66.361 ;
     RECT  2.304 66.361 84.114 66.427 ;
     RECT  0.108 66.317 0.198 66.434 ;
     RECT  1.728 66.427 84.114 66.479 ;
     RECT  1.728 66.479 84.042 66.749 ;
     RECT  1.728 66.749 83.898 66.785 ;
     RECT  0.108 66.434 0.126 67.243 ;
     RECT  1.728 66.785 83.697 67.711 ;
     RECT  1.728 67.711 83.754 67.801 ;
     RECT  1.728 67.801 83.826 67.937 ;
     RECT  42.948 67.937 83.826 67.945 ;
     RECT  0.108 67.243 0.342 68.011 ;
     RECT  1.728 67.937 42.21 68.099 ;
     RECT  0.108 68.011 0.594 68.521 ;
     RECT  42.948 67.945 83.862 68.521 ;
     RECT  1.764 68.099 42.21 68.639 ;
     RECT  42.948 68.521 83.898 68.755 ;
     RECT  42.948 68.755 84.006 68.909 ;
     RECT  42.948 68.909 83.898 68.945 ;
     RECT  1.8 68.639 42.21 69.295 ;
     RECT  42.948 68.945 83.697 69.295 ;
     RECT  1.8 69.295 83.697 69.529 ;
     RECT  1.764 69.529 83.697 69.961 ;
     RECT  0.036 68.521 0.594 70.027 ;
     RECT  0.036 70.027 0.882 70.123 ;
     RECT  1.764 69.961 84.042 70.123 ;
     RECT  0.036 70.123 84.042 70.301 ;
     RECT  1.764 70.301 84.042 70.439 ;
     RECT  2.232 70.439 84.042 70.529 ;
     RECT  2.232 70.529 83.898 70.565 ;
     RECT  2.232 70.565 83.697 70.835 ;
     RECT  0.036 70.301 0.882 71.311 ;
     RECT  2.232 70.835 82.566 71.339 ;
     RECT  2.232 71.339 82.494 71.375 ;
     RECT  2.232 71.375 81.918 71.383 ;
     RECT  0.036 71.311 1.17 71.447 ;
     RECT  2.196 71.383 81.918 71.519 ;
     RECT  2.196 71.519 81.486 71.609 ;
     RECT  45.396 71.609 81.378 71.645 ;
     RECT  0.036 71.447 0.882 71.789 ;
     RECT  0.18 71.789 0.882 71.987 ;
     RECT  0.18 71.987 0.234 72.149 ;
     RECT  45.396 71.645 81.342 72.571 ;
     RECT  2.196 71.609 44.658 72.841 ;
     RECT  45.396 72.571 81.45 72.841 ;
     RECT  2.196 72.841 81.63 73.031 ;
     RECT  0.18 72.149 0.198 73.099 ;
     RECT  0.144 73.099 0.198 73.147 ;
     RECT  0.144 73.147 0.234 73.195 ;
     RECT  2.196 73.031 81.018 73.229 ;
     RECT  0.144 73.195 0.342 73.277 ;
     RECT  0.216 73.277 0.342 73.325 ;
     RECT  2.196 73.229 80.982 73.769 ;
     RECT  2.196 73.769 17.514 73.805 ;
     RECT  18.252 73.769 80.982 73.841 ;
     RECT  2.196 73.805 17.226 73.867 ;
     RECT  2.16 73.867 17.226 74.039 ;
     RECT  18.288 73.841 80.982 74.039 ;
     RECT  25.272 74.039 80.982 74.075 ;
     RECT  18.288 74.039 24.354 74.183 ;
     RECT  25.272 74.075 80.802 74.219 ;
     RECT  2.16 74.039 16.866 74.309 ;
     RECT  2.16 74.309 10.854 74.489 ;
     RECT  22.824 74.183 24.354 74.579 ;
     RECT  25.272 74.219 80.478 74.579 ;
     RECT  7.776 74.489 10.854 74.615 ;
     RECT  11.736 74.309 16.326 74.615 ;
     RECT  25.272 74.579 44.55 74.615 ;
     RECT  45.576 74.579 80.478 74.615 ;
     RECT  2.16 74.489 6.858 74.651 ;
     RECT  45.576 74.615 70.182 74.651 ;
     RECT  70.956 74.615 80.478 74.651 ;
     RECT  8.856 74.615 10.674 74.687 ;
     RECT  70.956 74.651 80.262 74.687 ;
     RECT  23.616 74.579 24.354 74.723 ;
     RECT  18.288 74.183 21.978 74.731 ;
     RECT  25.272 74.615 44.01 74.821 ;
     RECT  11.736 74.615 16.11 74.849 ;
     RECT  18.072 74.731 21.978 74.857 ;
     RECT  9 74.687 10.674 74.885 ;
     RECT  11.736 74.849 16.074 74.885 ;
     RECT  23.94 74.723 24.354 74.885 ;
     RECT  17.964 74.857 21.978 74.929 ;
     RECT  17.964 74.929 22.014 74.957 ;
     RECT  70.956 74.687 79.362 74.957 ;
     RECT  9.072 74.885 10.674 74.993 ;
     RECT  23.976 74.885 24.354 75.001 ;
     RECT  25.236 74.821 44.01 75.001 ;
     RECT  22.824 74.579 22.842 75.005 ;
     RECT  7.776 74.615 8.097 75.029 ;
     RECT  9.108 74.993 10.674 75.029 ;
     RECT  12.024 74.885 16.074 75.029 ;
     RECT  23.976 75.001 44.01 75.029 ;
     RECT  2.196 74.651 6.858 75.119 ;
     RECT  12.492 75.029 16.074 75.119 ;
     RECT  18.18 74.957 22.014 75.119 ;
     RECT  24.015 75.029 44.01 75.119 ;
     RECT  45.615 74.651 70.182 75.119 ;
     RECT  70.956 74.957 78.297 75.119 ;
     RECT  79.092 74.957 79.362 75.119 ;
     RECT  80.244 74.687 80.262 75.119 ;
     RECT  9.108 75.029 10.602 75.155 ;
     RECT  12.492 75.119 14.886 75.155 ;
     RECT  16.056 75.119 16.074 75.155 ;
     RECT  20.196 75.119 21.978 75.155 ;
     RECT  34.815 75.119 41.238 75.155 ;
     RECT  47.052 75.119 69.282 75.155 ;
     RECT  79.092 75.119 79.11 75.155 ;
     RECT  20.268 75.155 21.978 75.191 ;
     RECT  25.308 75.119 33.678 75.191 ;
     RECT  42.192 75.119 44.01 75.191 ;
     RECT  45.615 75.119 46.206 75.191 ;
     RECT  52.02 75.155 53.226 75.191 ;
     RECT  2.196 75.119 4.41 75.227 ;
     RECT  13.032 75.155 14.886 75.227 ;
     RECT  20.376 75.191 21.978 75.227 ;
     RECT  47.052 75.155 51.297 75.227 ;
     RECT  52.056 75.191 53.226 75.227 ;
     RECT  26.244 75.191 32.058 75.245 ;
     RECT  53.964 75.155 69.282 75.245 ;
     RECT  20.556 75.227 21.978 75.263 ;
     RECT  26.244 75.245 26.91 75.263 ;
     RECT  47.052 75.227 47.646 75.263 ;
     RECT  71.136 75.119 78.297 75.263 ;
     RECT  18.18 75.119 19.422 75.293 ;
     RECT  9.108 75.155 10.35 75.299 ;
     RECT  35.892 75.155 41.238 75.299 ;
     RECT  43.812 75.191 44.01 75.299 ;
     RECT  48.456 75.227 49.842 75.299 ;
     RECT  74.664 75.263 78.297 75.299 ;
     RECT  7.815 75.029 8.097 75.347 ;
     RECT  24.015 75.119 24.297 75.347 ;
     RECT  34.815 75.155 35.097 75.347 ;
     RECT  45.615 75.191 45.897 75.347 ;
     RECT  50.616 75.227 51.297 75.347 ;
     RECT  75.348 75.299 78.297 75.347 ;
     RECT  83.415 70.835 83.697 75.347 ;
     RECT  2.376 75.227 4.122 75.389 ;
     RECT  5.184 75.119 6.57 75.389 ;
     RECT  9.108 75.299 9.234 75.389 ;
     RECT  9.972 75.299 10.35 75.389 ;
     RECT  21.348 75.263 21.978 75.389 ;
     RECT  25.308 75.191 25.47 75.389 ;
     RECT  26.244 75.263 26.262 75.389 ;
     RECT  27.9 75.245 32.058 75.389 ;
     RECT  32.796 75.191 33.678 75.389 ;
     RECT  35.928 75.299 39.042 75.389 ;
     RECT  39.816 75.299 41.238 75.389 ;
     RECT  43.884 75.299 44.01 75.389 ;
     RECT  47.16 75.263 47.646 75.389 ;
     RECT  48.456 75.299 48.474 75.389 ;
     RECT  52.056 75.227 52.29 75.389 ;
     RECT  53.208 75.227 53.226 75.389 ;
     RECT  53.964 75.245 57.15 75.389 ;
     RECT  70.128 75.119 70.182 75.389 ;
     RECT  71.136 75.263 73.674 75.389 ;
     RECT  75.348 75.347 78.174 75.389 ;
     RECT  2.376 75.389 3.51 75.425 ;
     RECT  9.972 75.389 10.026 75.425 ;
     RECT  13.215 75.227 14.886 75.425 ;
     RECT  18.288 75.293 19.422 75.425 ;
     RECT  21.852 75.389 21.87 75.425 ;
     RECT  25.308 75.389 25.326 75.425 ;
     RECT  27.9 75.389 27.918 75.425 ;
     RECT  29.196 75.389 29.505 75.425 ;
     RECT  30.42 75.389 30.654 75.425 ;
     RECT  32.796 75.389 32.814 75.425 ;
     RECT  35.964 75.389 37.674 75.425 ;
     RECT  42.192 75.191 42.966 75.425 ;
     RECT  43.884 75.389 43.902 75.425 ;
     RECT  47.268 75.389 47.646 75.425 ;
     RECT  49.68 75.299 49.842 75.425 ;
     RECT  53.964 75.389 55.062 75.425 ;
     RECT  55.8 75.389 56.862 75.425 ;
     RECT  58.14 75.245 69.282 75.425 ;
     RECT  71.136 75.389 73.242 75.425 ;
     RECT  14.868 75.425 14.886 75.437 ;
     RECT  18.54 75.425 19.422 75.437 ;
     RECT  20.556 75.263 20.574 75.437 ;
     RECT  36 75.425 37.674 75.437 ;
     RECT  38.844 75.389 38.862 75.437 ;
     RECT  40.104 75.389 40.554 75.437 ;
     RECT  2.415 75.425 3.438 75.461 ;
     RECT  10.008 75.425 10.026 75.461 ;
     RECT  13.215 75.425 13.806 75.461 ;
     RECT  36 75.437 36.486 75.461 ;
     RECT  47.34 75.425 47.646 75.461 ;
     RECT  52.056 75.389 52.074 75.461 ;
     RECT  53.964 75.425 53.982 75.461 ;
     RECT  58.752 75.425 69.282 75.461 ;
     RECT  70.164 75.389 70.182 75.461 ;
     RECT  71.208 75.425 71.802 75.461 ;
     RECT  0.54 73.387 0.558 75.497 ;
     RECT  2.415 75.461 3.042 75.497 ;
     RECT  5.184 75.389 5.31 75.497 ;
     RECT  36 75.461 36.234 75.497 ;
     RECT  37.332 75.437 37.674 75.497 ;
     RECT  40.215 75.437 40.554 75.497 ;
     RECT  42.192 75.425 42.822 75.497 ;
     RECT  50.616 75.347 51.105 75.497 ;
     RECT  59.904 75.461 59.922 75.497 ;
     RECT  5.292 75.497 5.31 75.533 ;
     RECT  30.636 75.425 30.654 75.533 ;
     RECT  31.464 75.389 32.058 75.533 ;
     RECT  49.824 75.425 49.842 75.533 ;
     RECT  56.016 75.425 56.505 75.533 ;
     RECT  71.424 75.461 71.802 75.533 ;
     RECT  6.552 75.389 6.57 75.569 ;
     RECT  18.54 75.437 18.705 75.569 ;
     RECT  31.464 75.533 31.482 75.569 ;
     RECT  37.332 75.497 37.35 75.569 ;
     RECT  42.192 75.497 42.678 75.569 ;
     RECT  76.284 75.389 76.302 75.569 ;
     RECT  77.508 75.389 78.105 75.569 ;
     RECT  2.415 75.497 2.505 75.617 ;
     RECT  7.815 75.347 7.905 75.617 ;
     RECT  13.215 75.461 13.305 75.617 ;
     RECT  18.615 75.569 18.705 75.617 ;
     RECT  24.015 75.347 24.105 75.617 ;
     RECT  29.415 75.425 29.505 75.617 ;
     RECT  34.815 75.347 34.905 75.617 ;
     RECT  40.215 75.497 40.305 75.617 ;
     RECT  45.615 75.347 45.705 75.617 ;
     RECT  51.015 75.497 51.105 75.617 ;
     RECT  56.415 75.533 56.505 75.617 ;
     RECT  72.615 75.425 73.242 75.617 ;
     RECT  78.015 75.569 78.105 75.617 ;
     RECT  83.415 75.347 83.505 75.617 ;
     RECT  42.192 75.569 42.642 75.659 ;
     RECT  61.02 75.461 69.03 75.659 ;
     RECT  73.224 75.617 73.242 75.659 ;
     RECT  61.02 75.659 68.634 76.397 ;
     RECT  61.956 76.397 68.634 76.637 ;
     RECT  61.956 76.637 68.274 77.069 ;
     RECT  64.08 77.069 68.274 77.501 ;
     RECT  64.08 77.501 67.122 77.549 ;
     RECT  61.02 76.397 61.146 77.597 ;
     RECT  61.956 77.069 63.342 77.597 ;
     RECT  65.592 77.549 67.122 77.597 ;
     RECT  61.02 77.597 61.038 77.645 ;
     RECT  62.64 77.597 63.342 77.645 ;
     RECT  64.08 77.549 64.818 77.645 ;
     RECT  65.592 77.597 66.15 77.645 ;
     RECT  67.104 77.597 67.122 77.645 ;
     RECT  66.132 77.645 66.15 77.741 ;
     RECT  68.256 77.501 68.274 77.741 ;
    LAYER M4 ;
     RECT  0.025 58.128 0.06 58.152 ;
     RECT  0.06 58.128 0.137 70.824 ;
     RECT  0.137 58.704 0.389 70.824 ;
     RECT  0.389 58.896 0.893 70.824 ;
     RECT  0.893 58.896 2.185 59.112 ;
     RECT  2.185 58.128 2.257 59.112 ;
     RECT  2.252 12.96 2.285 12.984 ;
     RECT  2.365 4.752 2.408 4.776 ;
     RECT  2.401 7.344 2.408 7.368 ;
     RECT  2.285 12.96 2.408 13.128 ;
     RECT  2.329 16.896 2.408 16.92 ;
     RECT  2.365 19.632 2.408 19.656 ;
     RECT  2.293 27.888 2.408 27.912 ;
     RECT  2.293 29.232 2.408 29.256 ;
     RECT  2.252 32.448 2.408 32.472 ;
     RECT  2.293 34.32 2.408 35.448 ;
     RECT  2.365 37.584 2.408 37.608 ;
     RECT  2.365 41.664 2.408 41.688 ;
     RECT  2.365 46.32 2.408 46.344 ;
     RECT  2.365 49.2 2.408 49.224 ;
     RECT  2.365 50.928 2.408 50.952 ;
     RECT  2.365 52.272 2.408 52.296 ;
     RECT  2.257 57.84 2.408 59.112 ;
     RECT  0.893 60.144 2.408 70.824 ;
     RECT  0.06 73.008 2.408 73.896 ;
     RECT  2.408 2.148 2.512 75.612 ;
     RECT  2.512 2.418 2.704 75.342 ;
     RECT  2.704 6.48 2.801 9.192 ;
     RECT  2.704 11.952 2.819 11.976 ;
     RECT  2.704 16.896 2.819 21.672 ;
     RECT  2.704 13.104 2.837 14.28 ;
     RECT  2.704 3.36 2.845 5.448 ;
     RECT  2.704 39.312 2.845 39.336 ;
     RECT  2.845 3.36 2.867 5.16 ;
     RECT  2.704 31.152 2.909 35.4 ;
     RECT  2.704 50.928 2.909 52.44 ;
     RECT  2.704 73.248 2.953 74.712 ;
     RECT  2.704 53.52 2.981 72.024 ;
     RECT  2.704 10.224 3.011 10.872 ;
     RECT  2.704 43.296 3.017 46.344 ;
     RECT  2.801 8.352 3.053 9.192 ;
     RECT  2.981 53.52 3.089 62.568 ;
     RECT  3.089 60.864 3.161 62.568 ;
     RECT  2.867 3.552 3.197 5.16 ;
     RECT  2.953 73.248 3.233 74.664 ;
     RECT  3.089 53.52 3.313 59.88 ;
     RECT  3.161 61.392 3.521 62.568 ;
     RECT  2.819 16.896 3.539 19.656 ;
     RECT  2.704 40.416 3.557 41.688 ;
     RECT  3.313 53.52 3.557 59.016 ;
     RECT  3.539 18.672 3.635 19.656 ;
     RECT  2.837 13.872 3.805 14.28 ;
     RECT  2.704 15.504 3.805 15.528 ;
     RECT  3.557 40.416 3.805 41.544 ;
     RECT  3.805 12.528 3.809 15.72 ;
     RECT  2.819 20.64 3.841 21.672 ;
     RECT  3.197 4.608 3.877 5.16 ;
     RECT  2.801 6.48 3.877 7.368 ;
     RECT  2.704 22.704 3.913 23.784 ;
     RECT  2.704 24.912 3.913 28.296 ;
     RECT  2.704 37.584 3.913 37.656 ;
     RECT  3.913 22.704 3.923 28.296 ;
     RECT  3.923 22.704 3.953 27.912 ;
     RECT  2.981 63.648 3.973 72.024 ;
     RECT  3.233 73.248 3.973 74.52 ;
     RECT  3.805 39.888 3.98 41.544 ;
     RECT  2.704 49.2 3.98 49.224 ;
     RECT  3.809 14.256 3.989 15.72 ;
     RECT  3.539 16.896 3.989 17.64 ;
     RECT  3.841 20.304 3.989 21.672 ;
     RECT  3.989 15.504 4.021 15.72 ;
     RECT  3.017 43.296 4.021 45.864 ;
     RECT  3.98 49.008 4.021 49.224 ;
     RECT  3.841 50.4 4.021 50.424 ;
     RECT  3.989 20.304 4.025 20.664 ;
     RECT  3.053 9.024 4.057 9.192 ;
     RECT  2.909 31.392 4.057 35.4 ;
     RECT  3.809 12.528 4.093 13.272 ;
     RECT  4.057 9.024 4.129 9.624 ;
     RECT  3.011 10.848 4.129 10.872 ;
     RECT  3.989 21.648 4.129 21.672 ;
     RECT  3.953 22.704 4.129 27.768 ;
     RECT  4.021 42.864 4.129 45.864 ;
     RECT  4.129 21.648 4.169 27.768 ;
     RECT  3.521 61.392 4.201 62.184 ;
     RECT  4.201 60.96 4.273 62.184 ;
     RECT  4.169 21.648 4.277 23.016 ;
     RECT  4.277 21.648 4.349 22.728 ;
     RECT  4.129 42.624 4.349 45.864 ;
     RECT  4.349 42.768 4.381 45.864 ;
     RECT  4.237 46.896 4.381 46.92 ;
     RECT  4.273 60.624 4.381 62.184 ;
     RECT  3.913 36.816 4.385 37.656 ;
     RECT  4.021 49.008 4.417 50.424 ;
     RECT  2.909 51.744 4.417 52.44 ;
     RECT  4.381 42.768 4.421 46.92 ;
     RECT  4.417 49.008 4.453 52.44 ;
     RECT  4.057 31.344 4.489 35.4 ;
     RECT  4.385 36.816 4.489 37.608 ;
     RECT  4.381 60.528 4.489 62.184 ;
     RECT  4.093 12.288 4.493 13.272 ;
     RECT  4.349 21.648 4.493 22.584 ;
     RECT  4.421 42.768 4.493 43.368 ;
     RECT  3.973 63.648 4.493 74.52 ;
     RECT  4.493 12.288 4.525 13.032 ;
     RECT  3.635 18.672 4.529 19.32 ;
     RECT  4.421 44.976 4.549 46.92 ;
     RECT  4.021 15.504 4.565 16.344 ;
     RECT  3.877 4.608 4.597 7.368 ;
     RECT  4.129 9.024 4.597 10.872 ;
     RECT  4.529 18.672 4.601 19.128 ;
     RECT  4.597 4.608 4.633 10.872 ;
     RECT  4.489 60.528 4.633 62.424 ;
     RECT  4.453 48.24 4.705 52.44 ;
     RECT  3.557 53.52 4.705 58.68 ;
     RECT  4.633 60.528 4.705 63 ;
     RECT  3.989 14.256 4.745 14.28 ;
     RECT  4.705 60.048 4.813 63 ;
     RECT  3.98 39.696 4.889 41.544 ;
     RECT  4.493 43.296 4.889 43.368 ;
     RECT  4.889 39.696 4.921 41.496 ;
     RECT  4.633 4.608 4.957 10.968 ;
     RECT  4.525 11.952 4.957 13.032 ;
     RECT  4.493 21.648 4.997 22.536 ;
     RECT  4.705 48.24 5.029 58.68 ;
     RECT  4.813 59.808 5.029 63 ;
     RECT  4.169 24.672 5.137 27.768 ;
     RECT  4.489 31.344 5.177 37.608 ;
     RECT  5.029 48.24 5.177 63 ;
     RECT  3.989 17.616 5.281 17.64 ;
     RECT  3.197 3.552 5.353 3.576 ;
     RECT  4.957 4.608 5.353 13.032 ;
     RECT  5.137 24.432 5.353 27.768 ;
     RECT  5.353 24.432 5.425 28.008 ;
     RECT  5.281 17.568 5.461 17.64 ;
     RECT  4.601 18.672 5.461 19.08 ;
     RECT  5.177 31.344 5.537 31.992 ;
     RECT  4.549 44.976 5.605 47.208 ;
     RECT  4.565 15.504 5.641 16.104 ;
     RECT  5.177 48.384 5.641 63 ;
     RECT  4.493 64.464 5.641 72.024 ;
     RECT  4.997 21.936 5.677 22.536 ;
     RECT  5.605 44.976 5.699 47.352 ;
     RECT  5.353 3.552 5.713 13.032 ;
     RECT  4.025 20.304 5.713 20.472 ;
     RECT  4.501 30.24 5.713 30.264 ;
     RECT  5.713 20.304 5.749 20.568 ;
     RECT  5.641 14.496 5.789 16.104 ;
     RECT  5.425 24.192 5.821 28.008 ;
     RECT  5.177 33.024 5.821 37.608 ;
     RECT  4.921 38.736 5.821 41.496 ;
     RECT  5.749 20.112 5.857 20.568 ;
     RECT  5.677 21.936 5.897 23.016 ;
     RECT  5.461 17.568 5.929 19.08 ;
     RECT  5.857 20.064 5.929 20.568 ;
     RECT  5.821 24.192 6.001 28.728 ;
     RECT  5.641 48.384 6.001 72.024 ;
     RECT  4.493 73.104 6.001 74.52 ;
     RECT  5.713 3.264 6.005 13.032 ;
     RECT  6.001 24.192 6.073 29.016 ;
     RECT  6.005 9.552 6.109 13.032 ;
     RECT  5.929 17.088 6.109 20.568 ;
     RECT  5.897 21.936 6.109 22.584 ;
     RECT  5.821 33.024 6.113 41.496 ;
     RECT  6.001 48.384 6.149 74.52 ;
     RECT  6.113 38.736 6.181 41.496 ;
     RECT  6.109 17.088 6.221 22.584 ;
     RECT  6.073 24.144 6.221 29.016 ;
     RECT  6.109 9.552 6.253 13.272 ;
     RECT  5.789 15.84 6.277 16.104 ;
     RECT  6.221 17.088 6.277 20.52 ;
     RECT  6.253 9.552 6.289 13.416 ;
     RECT  5.789 14.496 6.289 14.808 ;
     RECT  6.277 15.84 6.293 20.52 ;
     RECT  6.149 48.384 6.293 73.752 ;
     RECT  6.293 48.384 6.323 73.608 ;
     RECT  6.323 58.176 6.365 73.608 ;
     RECT  5.537 31.44 6.397 31.992 ;
     RECT  5.699 44.976 6.433 47.064 ;
     RECT  4.889 43.296 6.437 43.32 ;
     RECT  6.365 58.176 6.473 73.464 ;
     RECT  6.397 31.44 6.505 32.04 ;
     RECT  6.113 33.024 6.505 37.608 ;
     RECT  6.323 48.384 6.689 57.048 ;
     RECT  6.221 24.144 6.721 28.728 ;
     RECT  5.713 30.192 6.757 30.264 ;
     RECT  6.181 38.736 6.757 42.072 ;
     RECT  6.293 15.84 6.761 19.08 ;
     RECT  6.689 48.384 6.793 48.792 ;
     RECT  6.221 21.936 6.937 22.584 ;
     RECT  6.721 23.856 6.937 28.728 ;
     RECT  6.757 30.096 7.148 30.264 ;
     RECT  6.505 31.44 7.148 37.608 ;
     RECT  6.289 9.552 7.189 14.808 ;
     RECT  6.761 15.84 7.189 16.632 ;
     RECT  7.148 30.096 7.189 37.608 ;
     RECT  6.757 38.736 7.189 42.792 ;
     RECT  6.005 3.264 7.261 8.472 ;
     RECT  7.189 9.552 7.261 16.632 ;
     RECT  7.261 3.264 7.285 16.632 ;
     RECT  6.293 20.064 7.405 20.52 ;
     RECT  6.937 21.936 7.405 28.728 ;
     RECT  7.189 30.096 7.429 42.792 ;
     RECT  6.761 17.616 7.58 19.08 ;
     RECT  7.405 20.064 7.58 28.728 ;
     RECT  7.58 17.616 7.621 28.728 ;
     RECT  6.689 49.872 7.657 57.048 ;
     RECT  6.473 58.176 7.657 73.272 ;
     RECT  7.285 2.256 7.808 16.632 ;
     RECT  7.621 17.616 7.808 29.064 ;
     RECT  7.429 30.096 7.808 43.752 ;
     RECT  6.433 44.928 7.808 47.064 ;
     RECT  6.793 48.144 7.808 48.792 ;
     RECT  7.657 49.872 7.808 73.272 ;
     RECT  7.573 74.304 7.808 74.328 ;
     RECT  7.808 2.148 7.912 75.612 ;
     RECT  7.912 2.418 8.104 75.342 ;
     RECT  8.104 20.064 8.531 50.376 ;
     RECT  8.531 20.064 8.633 31.032 ;
     RECT  8.531 32.016 8.633 50.376 ;
     RECT  8.633 20.064 8.669 28.824 ;
     RECT  8.104 51.36 8.993 69.768 ;
     RECT  8.633 32.16 9.029 50.376 ;
     RECT  8.669 20.064 9.101 28.776 ;
     RECT  8.993 69.504 9.277 69.768 ;
     RECT  8.845 0.528 9.349 0.552 ;
     RECT  8.993 51.36 9.389 68.472 ;
     RECT  8.104 71.328 9.529 74.184 ;
     RECT  8.104 2.88 9.709 19.08 ;
     RECT  9.349 0.096 9.745 0.552 ;
     RECT  9.709 2.736 9.745 19.08 ;
     RECT  9.101 20.064 9.745 28.728 ;
     RECT  8.633 30.096 9.781 31.032 ;
     RECT  9.529 71.184 9.821 74.184 ;
     RECT  9.745 2.736 9.929 28.728 ;
     RECT  9.821 71.184 10.037 74.136 ;
     RECT  9.745 0.096 10.067 0.648 ;
     RECT  9.781 29.856 10.069 31.032 ;
     RECT  9.029 32.256 10.069 50.376 ;
     RECT  9.389 57.6 10.105 68.472 ;
     RECT  9.277 69.504 10.105 69.816 ;
     RECT  10.037 73.104 10.109 74.136 ;
     RECT  9.929 20.304 10.141 28.728 ;
     RECT  10.069 29.856 10.141 50.376 ;
     RECT  9.389 51.36 10.141 56.616 ;
     RECT  10.141 20.304 10.253 56.616 ;
     RECT  10.105 57.6 10.325 69.816 ;
     RECT  10.253 48.048 10.397 56.616 ;
     RECT  10.109 73.104 10.433 73.992 ;
     RECT  10.405 1.728 10.501 1.752 ;
     RECT  9.929 2.736 10.501 19.32 ;
     RECT  10.325 57.6 10.505 69.72 ;
     RECT  10.397 48.624 10.681 56.616 ;
     RECT  10.505 57.6 10.681 69.528 ;
     RECT  10.501 1.728 10.793 19.32 ;
     RECT  10.681 48.624 10.901 69.528 ;
     RECT  10.067 0.096 11.045 0.6 ;
     RECT  11.045 0.48 11.077 0.6 ;
     RECT  10.793 1.728 11.077 2.28 ;
     RECT  10.793 3.456 11.077 19.32 ;
     RECT  10.253 20.304 11.077 47.064 ;
     RECT  11.077 0.48 11.161 2.28 ;
     RECT  10.901 48.624 11.267 68.376 ;
     RECT  11.267 48.624 11.297 65.592 ;
     RECT  11.297 56.496 11.305 65.592 ;
     RECT  10.037 71.184 11.329 71.64 ;
     RECT  11.297 48.624 11.333 55.464 ;
     RECT  11.077 3.456 11.365 47.064 ;
     RECT  10.433 73.104 11.365 73.656 ;
     RECT  11.267 66.576 11.369 68.376 ;
     RECT  11.365 72.768 11.411 73.656 ;
     RECT  11.329 70.608 11.473 71.64 ;
     RECT  11.411 72.768 11.473 73.368 ;
     RECT  11.305 56.496 11.477 65.496 ;
     RECT  11.473 70.608 11.513 73.368 ;
     RECT  11.333 53.28 11.585 55.464 ;
     RECT  11.477 56.496 11.657 61.224 ;
     RECT  11.365 3.456 11.689 47.352 ;
     RECT  11.333 48.624 11.689 51.96 ;
     RECT  10.901 69.504 11.765 69.528 ;
     RECT  11.365 74.688 11.765 74.712 ;
     RECT  11.161 1.728 11.941 2.28 ;
     RECT  11.689 3.456 11.941 51.96 ;
     RECT  11.369 66.72 12.161 68.376 ;
     RECT  11.161 0.48 12.293 0.6 ;
     RECT  12.161 66.72 12.409 68.136 ;
     RECT  11.513 71.136 12.517 73.368 ;
     RECT  12.517 71.136 12.589 73.56 ;
     RECT  11.585 53.28 12.62 55.272 ;
     RECT  11.657 56.544 12.62 61.224 ;
     RECT  12.293 0.096 12.673 0.6 ;
     RECT  12.589 71.088 12.769 73.56 ;
     RECT  11.941 1.728 12.949 51.96 ;
     RECT  12.62 53.28 12.949 61.224 ;
     RECT  12.949 1.728 12.985 61.224 ;
     RECT  11.477 62.592 12.985 65.496 ;
     RECT  12.985 1.728 13.208 65.496 ;
     RECT  12.409 66.48 13.208 68.136 ;
     RECT  12.769 69.552 13.208 69.576 ;
     RECT  12.769 71.088 13.208 74.088 ;
     RECT  13.093 75.12 13.208 75.144 ;
     RECT  13.208 1.728 13.312 75.612 ;
     RECT  13.312 1.728 13.504 75.432 ;
     RECT  13.504 68.976 13.565 72.6 ;
     RECT  12.673 0.096 13.661 0.552 ;
     RECT  13.504 56.16 13.667 64.104 ;
     RECT  13.504 74.064 13.709 75.432 ;
     RECT  13.661 0.096 13.745 0.6 ;
     RECT  13.504 52.176 13.997 54.888 ;
     RECT  13.997 52.176 14.249 54.168 ;
     RECT  13.709 74.64 14.465 75.432 ;
     RECT  13.504 28.896 14.569 51.192 ;
     RECT  14.249 52.176 14.569 53.88 ;
     RECT  13.504 66.768 14.569 66.792 ;
     RECT  14.569 66.672 14.713 66.792 ;
     RECT  13.745 0.096 14.821 0.552 ;
     RECT  13.504 1.728 14.866 27.624 ;
     RECT  14.465 75.408 14.897 75.432 ;
     RECT  13.565 70.128 14.929 72.6 ;
     RECT  13.667 56.16 14.965 64.008 ;
     RECT  13.504 65.472 14.965 65.496 ;
     RECT  14.965 54.864 15.001 55.128 ;
     RECT  14.965 56.16 15.001 65.496 ;
     RECT  14.569 28.896 15.037 53.88 ;
     RECT  15.001 54.864 15.181 65.496 ;
     RECT  14.713 66.528 15.181 66.792 ;
     RECT  15.037 28.8 15.289 53.88 ;
     RECT  14.929 70.08 15.293 72.6 ;
     RECT  14.821 0.096 15.481 0.6 ;
     RECT  14.866 1.728 15.577 27.672 ;
     RECT  15.289 28.656 15.577 53.88 ;
     RECT  15.181 54.864 15.577 66.792 ;
     RECT  13.565 68.976 15.577 69 ;
     RECT  15.293 70.08 15.577 72.552 ;
     RECT  14.857 73.632 15.617 74.328 ;
     RECT  15.577 1.728 15.725 66.792 ;
     RECT  15.617 73.632 15.761 74.04 ;
     RECT  15.001 67.824 15.793 67.848 ;
     RECT  15.725 50.928 15.857 66.792 ;
     RECT  15.793 67.824 15.857 67.896 ;
     RECT  15.725 1.728 15.905 49.944 ;
     RECT  15.857 50.928 15.941 67.896 ;
     RECT  15.941 50.928 16.085 66.744 ;
     RECT  15.481 0.096 16.229 0.12 ;
     RECT  16.085 51.648 16.265 66.744 ;
     RECT  15.941 67.728 16.337 67.896 ;
     RECT  16.265 51.648 16.373 66.696 ;
     RECT  15.577 68.976 16.405 72.552 ;
     RECT  16.405 68.928 16.553 72.552 ;
     RECT  16.373 51.648 16.589 66.648 ;
     RECT  15.905 1.728 16.805 49.896 ;
     RECT  16.553 68.928 16.837 72.264 ;
     RECT  16.805 1.728 16.841 23.688 ;
     RECT  16.805 24.72 16.873 49.896 ;
     RECT  16.589 66.48 16.913 66.648 ;
     RECT  16.837 68.88 17.077 72.264 ;
     RECT  17.077 68.832 17.219 72.264 ;
     RECT  16.873 24.72 17.381 50.616 ;
     RECT  17.381 36 17.449 50.616 ;
     RECT  16.589 51.648 17.449 65.496 ;
     RECT  16.337 67.728 17.557 67.752 ;
     RECT  17.557 67.728 17.701 67.896 ;
     RECT  15.761 73.632 17.953 73.656 ;
     RECT  17.219 68.928 18.169 72.264 ;
     RECT  17.953 73.248 18.169 73.656 ;
     RECT  18.169 68.928 18.277 73.656 ;
     RECT  18.169 75.264 18.277 75.288 ;
     RECT  18.277 68.928 18.325 75.288 ;
     RECT  16.913 66.48 18.457 66.504 ;
     RECT  17.381 24.72 18.565 35.016 ;
     RECT  17.449 36 18.565 65.496 ;
     RECT  16.841 2.304 18.608 23.688 ;
     RECT  18.565 24.72 18.608 65.496 ;
     RECT  18.457 66.48 18.608 66.6 ;
     RECT  17.701 67.632 18.608 67.896 ;
     RECT  18.325 68.928 18.608 75.432 ;
     RECT  18.608 2.148 18.712 75.612 ;
     RECT  18.712 2.352 18.904 75.432 ;
     RECT  18.904 2.352 19.181 74.088 ;
     RECT  19.181 2.352 19.289 47.928 ;
     RECT  19.181 48.912 19.505 74.088 ;
     RECT  18.904 75.264 19.667 75.432 ;
     RECT  19.505 52.176 19.829 74.04 ;
     RECT  19.829 52.176 20.009 67.128 ;
     RECT  19.829 70.896 20.045 74.04 ;
     RECT  20.045 70.896 20.081 73.32 ;
     RECT  20.081 72.288 20.225 73.32 ;
     RECT  20.225 72.288 20.531 72.408 ;
     RECT  19.289 2.352 20.581 47.88 ;
     RECT  19.667 75.408 20.585 75.432 ;
     RECT  19.829 68.304 20.693 69.576 ;
     RECT  20.581 2.304 20.941 47.88 ;
     RECT  19.505 48.912 20.941 51.192 ;
     RECT  20.009 52.176 20.941 66.696 ;
     RECT  20.941 2.304 20.977 66.696 ;
     RECT  21.013 74.688 21.049 74.712 ;
     RECT  20.531 72.288 21.121 72.312 ;
     RECT  20.977 2.304 21.125 67.368 ;
     RECT  21.125 2.304 21.155 30.744 ;
     RECT  21.125 31.728 21.233 67.368 ;
     RECT  20.081 70.896 21.409 71.208 ;
     RECT  21.121 72.192 21.409 72.312 ;
     RECT  20.693 68.544 21.445 69.576 ;
     RECT  21.409 70.896 21.445 72.312 ;
     RECT  21.049 74.064 21.593 74.712 ;
     RECT  21.233 32.976 21.665 67.368 ;
     RECT  21.593 74.688 21.809 74.712 ;
     RECT  21.665 36.288 21.845 67.368 ;
     RECT  21.845 36.768 21.881 67.368 ;
     RECT  21.445 68.544 21.953 72.312 ;
     RECT  21.155 24.432 22.025 30.744 ;
     RECT  21.881 38.496 22.241 67.368 ;
     RECT  22.241 38.496 22.277 67.224 ;
     RECT  21.233 31.728 22.381 31.752 ;
     RECT  21.665 32.976 22.633 35.304 ;
     RECT  21.155 2.304 22.673 23.448 ;
     RECT  22.381 31.392 22.7 31.752 ;
     RECT  22.633 32.784 22.7 35.304 ;
     RECT  22.7 31.392 22.813 35.304 ;
     RECT  22.277 38.496 22.885 40.392 ;
     RECT  22.673 2.352 22.925 23.448 ;
     RECT  22.925 2.544 22.957 23.448 ;
     RECT  22.025 24.432 22.957 29.928 ;
     RECT  21.881 36.768 22.957 37.08 ;
     RECT  22.885 38.4 22.957 40.392 ;
     RECT  22.813 31.392 23.029 35.448 ;
     RECT  22.957 36.768 23.029 40.392 ;
     RECT  22.957 2.544 23.209 29.928 ;
     RECT  23.029 31.392 23.209 40.392 ;
     RECT  21.953 68.544 23.209 71.304 ;
     RECT  23.209 2.544 23.42 40.392 ;
     RECT  22.277 41.376 23.42 67.224 ;
     RECT  23.42 2.544 23.497 67.224 ;
     RECT  23.209 68.208 23.497 71.304 ;
     RECT  23.497 2.544 23.569 71.304 ;
     RECT  22.741 72.336 23.569 73.272 ;
     RECT  23.569 2.544 23.893 73.272 ;
     RECT  23.893 2.544 24.008 73.896 ;
     RECT  22.813 74.976 24.008 75 ;
     RECT  24.008 2.148 24.112 75.612 ;
     RECT  24.112 2.418 24.304 75.342 ;
     RECT  24.304 2.544 24.473 73.896 ;
     RECT  24.473 2.544 24.941 72.456 ;
     RECT  24.473 73.44 25.369 73.896 ;
     RECT  24.304 74.976 25.369 75 ;
     RECT  25.369 73.44 25.405 75 ;
     RECT  24.941 2.64 25.657 72.456 ;
     RECT  25.405 73.44 25.657 75.24 ;
     RECT  25.657 2.64 26.017 75.24 ;
     RECT  26.017 2.496 26.273 75.24 ;
     RECT  26.273 2.496 26.309 30.312 ;
     RECT  26.309 2.496 26.377 30.024 ;
     RECT  26.377 2.448 26.597 30.024 ;
     RECT  26.597 14.16 27.533 30.024 ;
     RECT  26.273 31.344 28.037 75.24 ;
     RECT  27.533 14.16 28.969 29.496 ;
     RECT  28.037 31.344 28.969 74.904 ;
     RECT  26.597 2.448 28.972 13.176 ;
     RECT  28.969 14.16 28.972 74.904 ;
     RECT  28.972 2.448 29.408 74.904 ;
     RECT  29.408 2.148 29.512 75.612 ;
     RECT  29.512 2.418 29.704 75.342 ;
     RECT  29.704 14.352 30.197 35.88 ;
     RECT  29.704 2.544 30.697 13.272 ;
     RECT  29.704 37.104 30.769 74.904 ;
     RECT  30.697 2.448 30.953 13.272 ;
     RECT  30.953 8.688 31.093 13.272 ;
     RECT  30.197 14.352 31.093 35.784 ;
     RECT  31.093 8.688 31.133 35.784 ;
     RECT  30.769 37.104 31.777 75.288 ;
     RECT  30.953 2.448 31.849 7.704 ;
     RECT  31.849 2.352 31.861 7.704 ;
     RECT  31.133 31.248 31.885 35.784 ;
     RECT  31.777 36.816 31.885 75.288 ;
     RECT  31.861 2.256 32.033 7.704 ;
     RECT  31.133 8.688 32.209 30.12 ;
     RECT  31.885 31.248 32.209 75.288 ;
     RECT  32.209 8.688 32.645 75.288 ;
     RECT  32.645 8.688 32.675 72.984 ;
     RECT  32.645 74.4 32.825 75.288 ;
     RECT  32.033 2.4 33.145 7.704 ;
     RECT  32.675 8.688 33.145 35.88 ;
     RECT  33.145 2.4 33.505 35.88 ;
     RECT  33.505 2.256 33.689 35.88 ;
     RECT  32.675 36.96 33.829 72.984 ;
     RECT  33.829 36.864 34.045 72.984 ;
     RECT  34.045 36.864 34.117 73.032 ;
     RECT  34.117 36.816 34.153 73.032 ;
     RECT  32.825 74.4 34.153 75.144 ;
     RECT  33.689 2.256 34.808 35.784 ;
     RECT  34.153 36.816 34.808 75.144 ;
     RECT  34.808 2.148 34.912 75.612 ;
     RECT  34.912 2.418 35.104 75.342 ;
     RECT  35.104 14.64 35.129 75.192 ;
     RECT  35.129 14.64 35.201 37.08 ;
     RECT  35.201 14.64 35.219 32.52 ;
     RECT  35.129 38.256 35.345 47.352 ;
     RECT  35.345 40.848 35.417 47.352 ;
     RECT  35.219 14.64 35.453 29.544 ;
     RECT  35.219 30.672 35.453 32.52 ;
     RECT  35.104 2.784 35.489 13.32 ;
     RECT  35.417 41.088 35.507 47.352 ;
     RECT  35.489 2.784 35.741 8.808 ;
     RECT  35.453 15.456 35.849 21.144 ;
     RECT  35.453 22.176 35.849 29.544 ;
     RECT  35.849 22.272 35.993 29.544 ;
     RECT  35.741 7.104 36.029 8.808 ;
     RECT  35.741 2.784 36.169 5.736 ;
     RECT  35.201 33.648 36.169 37.08 ;
     RECT  35.345 38.256 36.169 39.576 ;
     RECT  35.993 22.368 36.209 29.544 ;
     RECT  35.489 9.936 36.277 13.32 ;
     RECT  36.209 22.464 36.277 29.544 ;
     RECT  35.453 30.672 36.277 32.472 ;
     RECT  36.277 22.464 36.281 32.472 ;
     RECT  36.277 9.936 36.457 14.088 ;
     RECT  36.169 33.648 36.457 39.576 ;
     RECT  36.281 22.56 36.461 32.472 ;
     RECT  36.457 33.648 36.493 39.624 ;
     RECT  36.457 9.936 36.529 14.232 ;
     RECT  35.129 48.432 36.601 75.192 ;
     RECT  36.493 33.648 36.605 39.768 ;
     RECT  35.849 15.456 36.641 21.096 ;
     RECT  36.605 38.688 36.673 39.768 ;
     RECT  35.507 41.088 36.673 46.92 ;
     RECT  36.529 9.936 36.709 14.28 ;
     RECT  36.641 15.456 36.709 18.552 ;
     RECT  36.169 2.736 36.853 5.736 ;
     RECT  36.673 38.688 36.893 46.92 ;
     RECT  36.853 2.256 36.94 5.736 ;
     RECT  36.641 19.824 37.037 21.096 ;
     RECT  36.461 22.56 37.109 26.04 ;
     RECT  36.893 39.264 37.213 46.92 ;
     RECT  37.109 26.016 37.217 26.04 ;
     RECT  36.605 33.648 37.217 37.32 ;
     RECT  36.601 48.432 37.217 75.432 ;
     RECT  37.213 39.264 37.429 47.064 ;
     RECT  36.029 7.152 37.465 8.808 ;
     RECT  37.217 48.432 37.505 74.136 ;
     RECT  36.94 2.592 37.537 5.736 ;
     RECT  37.429 39.264 37.609 47.16 ;
     RECT  37.505 48.432 37.609 66.504 ;
     RECT  37.537 2.592 37.613 5.88 ;
     RECT  37.465 7.152 37.765 8.856 ;
     RECT  36.709 9.936 37.765 18.552 ;
     RECT  37.037 19.824 37.789 20.136 ;
     RECT  37.505 67.728 37.829 74.136 ;
     RECT  37.613 3.36 37.861 5.88 ;
     RECT  37.217 35.472 37.861 37.32 ;
     RECT  37.765 21.12 37.907 21.144 ;
     RECT  37.861 3.36 37.933 6.12 ;
     RECT  37.765 7.152 37.933 18.552 ;
     RECT  37.789 19.536 37.973 20.136 ;
     RECT  37.861 35.472 38.005 37.752 ;
     RECT  36.461 27.216 38.077 32.472 ;
     RECT  37.933 3.36 38.117 18.552 ;
     RECT  38.077 26.688 38.149 32.472 ;
     RECT  37.217 33.648 38.149 33.96 ;
     RECT  38.005 35.472 38.156 37.896 ;
     RECT  38.156 35.472 38.185 38.184 ;
     RECT  37.609 39.264 38.185 66.504 ;
     RECT  37.829 67.728 38.189 72.936 ;
     RECT  37.829 74.064 38.221 74.136 ;
     RECT  37.217 75.168 38.221 75.432 ;
     RECT  37.973 19.536 38.225 20.088 ;
     RECT  38.117 10.032 38.291 18.552 ;
     RECT  38.291 13.968 38.365 18.552 ;
     RECT  38.225 19.536 38.365 19.944 ;
     RECT  38.149 26.688 38.369 33.96 ;
     RECT  38.369 26.688 38.545 30.36 ;
     RECT  38.117 3.36 38.617 8.856 ;
     RECT  38.185 35.472 38.653 66.504 ;
     RECT  38.189 67.728 38.653 72.744 ;
     RECT  38.653 35.472 38.657 72.744 ;
     RECT  37.109 22.56 38.761 24.696 ;
     RECT  38.761 22.224 38.869 24.696 ;
     RECT  38.221 74.064 38.873 75.432 ;
     RECT  38.657 35.472 38.905 39.912 ;
     RECT  38.657 41.136 38.909 72.744 ;
     RECT  38.617 2.832 38.945 8.856 ;
     RECT  38.909 41.136 38.945 43.416 ;
     RECT  38.909 44.4 38.981 72.744 ;
     RECT  38.365 13.968 39.017 19.944 ;
     RECT  39.017 18.192 39.053 19.944 ;
     RECT  39.017 13.968 39.125 17.064 ;
     RECT  38.945 8.736 39.229 8.856 ;
     RECT  38.905 35.424 39.229 39.912 ;
     RECT  39.229 8.736 39.301 9 ;
     RECT  38.291 10.032 39.301 12.792 ;
     RECT  38.869 21.36 39.445 24.696 ;
     RECT  39.445 20.976 39.637 24.696 ;
     RECT  38.981 66.48 39.805 72.744 ;
     RECT  39.637 20.976 39.877 25.032 ;
     RECT  38.545 26.208 39.877 30.36 ;
     RECT  39.877 20.976 39.925 30.36 ;
     RECT  38.369 31.344 39.925 33.96 ;
     RECT  39.925 20.976 39.949 33.96 ;
     RECT  39.229 35.328 39.973 39.912 ;
     RECT  38.945 41.136 39.973 43.368 ;
     RECT  38.945 2.832 39.985 7.464 ;
     RECT  39.053 18.528 40.021 19.944 ;
     RECT  39.949 20.928 40.021 33.96 ;
     RECT  39.985 2.496 40.057 7.464 ;
     RECT  39.301 8.736 40.057 12.792 ;
     RECT  40.057 2.496 40.069 12.792 ;
     RECT  40.069 2.496 40.208 13.128 ;
     RECT  39.125 14.4 40.208 17.064 ;
     RECT  40.021 18.528 40.208 33.96 ;
     RECT  39.973 35.328 40.208 43.368 ;
     RECT  38.981 44.4 40.208 65.496 ;
     RECT  39.805 66.48 40.208 73.608 ;
     RECT  38.873 74.592 40.208 75.432 ;
     RECT  40.208 2.148 40.312 75.612 ;
     RECT  40.312 2.256 40.504 75.342 ;
     RECT  40.504 8.256 40.565 12.84 ;
     RECT  40.504 41.232 40.601 75.096 ;
     RECT  40.504 14.112 40.643 30.36 ;
     RECT  40.565 8.4 40.739 12.84 ;
     RECT  40.504 2.256 40.835 7.176 ;
     RECT  40.739 8.736 40.925 12.84 ;
     RECT  40.643 14.112 40.997 29.304 ;
     RECT  40.997 14.112 41.033 25.128 ;
     RECT  41.033 22.272 41.141 25.128 ;
     RECT  40.997 26.496 41.249 29.304 ;
     RECT  40.601 67.584 41.249 75.096 ;
     RECT  41.249 26.784 41.285 29.304 ;
     RECT  40.504 35.472 41.285 39.816 ;
     RECT  40.835 2.832 41.321 7.176 ;
     RECT  40.925 10.896 41.429 12.84 ;
     RECT  41.033 14.112 41.465 21.288 ;
     RECT  41.285 35.472 41.501 39.624 ;
     RECT  41.321 2.832 41.507 4.104 ;
     RECT  40.504 31.392 41.605 33.96 ;
     RECT  40.601 41.232 41.605 66.504 ;
     RECT  41.141 22.752 41.609 25.128 ;
     RECT  41.465 20.976 41.645 21.288 ;
     RECT  41.501 35.472 41.681 35.832 ;
     RECT  41.605 40.704 41.692 66.504 ;
     RECT  41.692 41.136 41.717 66.504 ;
     RECT  41.507 2.832 41.753 3.72 ;
     RECT  41.681 35.472 41.753 35.784 ;
     RECT  41.501 37.2 41.753 39.624 ;
     RECT  41.717 49.536 41.797 66.504 ;
     RECT  41.249 67.584 41.797 73.848 ;
     RECT  41.797 49.536 41.843 73.848 ;
     RECT  41.609 23.04 41.861 25.128 ;
     RECT  41.843 69.264 41.861 73.848 ;
     RECT  40.925 8.736 41.893 9.672 ;
     RECT  41.753 2.832 41.897 3.672 ;
     RECT  41.717 41.136 41.897 48.504 ;
     RECT  41.429 12 41.965 12.84 ;
     RECT  41.897 2.832 41.969 2.856 ;
     RECT  41.321 5.568 42.037 7.176 ;
     RECT  41.893 8.208 42.037 9.672 ;
     RECT  41.965 12 42.113 12.888 ;
     RECT  40.643 30.336 42.113 30.36 ;
     RECT  41.285 27.312 42.145 29.304 ;
     RECT  41.249 75.024 42.253 75.096 ;
     RECT  42.181 1.824 42.265 2.328 ;
     RECT  42.145 27.312 42.289 29.592 ;
     RECT  41.605 31.392 42.289 34.104 ;
     RECT  42.101 35.328 42.289 35.352 ;
     RECT  41.465 14.112 42.293 19.848 ;
     RECT  42.265 1.824 42.361 1.848 ;
     RECT  41.753 37.296 42.361 39.624 ;
     RECT  42.289 31.392 42.397 35.352 ;
     RECT  41.843 49.536 42.401 67.656 ;
     RECT  41.429 10.896 42.469 11.016 ;
     RECT  42.113 12 42.469 12.84 ;
     RECT  42.401 49.536 42.509 67.272 ;
     RECT  42.253 74.928 42.541 75.096 ;
     RECT  42.361 37.296 42.545 39.816 ;
     RECT  42.037 5.568 42.572 9.672 ;
     RECT  42.289 26.784 42.625 29.592 ;
     RECT  42.625 26.784 42.652 28.728 ;
     RECT  42.572 5.28 42.659 9.672 ;
     RECT  42.293 17.616 42.721 19.848 ;
     RECT  41.645 20.976 42.721 21.192 ;
     RECT  42.659 5.568 42.757 9.672 ;
     RECT  42.397 31.248 42.761 35.352 ;
     RECT  41.897 41.136 42.761 48.36 ;
     RECT  42.253 0.576 42.793 0.6 ;
     RECT  42.361 1.728 42.793 1.848 ;
     RECT  42.761 41.136 42.793 46.056 ;
     RECT  42.652 26.784 42.797 26.808 ;
     RECT  42.761 32.976 42.829 35.352 ;
     RECT  42.721 17.616 42.833 21.672 ;
     RECT  42.545 37.536 42.833 39.816 ;
     RECT  41.861 69.264 42.833 72.84 ;
     RECT  42.793 0.576 42.841 1.848 ;
     RECT  42.793 40.944 42.869 46.056 ;
     RECT  42.757 5.568 42.937 9.912 ;
     RECT  42.469 10.896 42.937 12.84 ;
     RECT  42.833 69.264 42.937 71.88 ;
     RECT  41.861 23.04 42.973 24.744 ;
     RECT  42.761 31.248 42.977 31.752 ;
     RECT  42.833 38.304 43.117 39.816 ;
     RECT  42.869 40.944 43.117 45.72 ;
     RECT  42.761 47.04 43.117 48.36 ;
     RECT  42.509 49.536 43.117 67.032 ;
     RECT  42.937 5.568 43.157 12.84 ;
     RECT  43.157 8.544 43.189 12.84 ;
     RECT  42.293 14.112 43.189 16.344 ;
     RECT  42.973 22.656 43.189 24.744 ;
     RECT  42.541 74.4 43.229 75.096 ;
     RECT  42.833 17.616 43.261 20.664 ;
     RECT  42.833 21.648 43.333 21.672 ;
     RECT  43.189 22.656 43.333 24.792 ;
     RECT  42.937 68.832 43.333 71.88 ;
     RECT  43.189 8.544 43.373 16.344 ;
     RECT  42.829 32.976 43.409 35.736 ;
     RECT  42.841 1.152 43.417 1.848 ;
     RECT  43.373 15.552 43.441 16.344 ;
     RECT  43.261 17.52 43.441 20.664 ;
     RECT  43.373 8.544 43.481 14.52 ;
     RECT  43.117 38.304 43.481 45.72 ;
     RECT  43.333 68.64 43.481 71.88 ;
     RECT  43.369 4.56 43.549 4.584 ;
     RECT  43.409 34.32 43.553 35.736 ;
     RECT  43.549 3.84 43.657 4.584 ;
     RECT  43.157 5.568 43.657 7.464 ;
     RECT  43.481 8.544 43.661 11.976 ;
     RECT  43.481 38.304 43.661 45.624 ;
     RECT  43.417 1.728 43.667 1.848 ;
     RECT  43.297 30 43.669 30.024 ;
     RECT  43.409 32.976 43.715 33.24 ;
     RECT  43.117 47.04 43.765 67.032 ;
     RECT  43.765 47.04 43.801 67.56 ;
     RECT  43.481 68.64 43.801 71.16 ;
     RECT  43.441 15.552 43.805 20.664 ;
     RECT  43.333 21.648 43.805 24.792 ;
     RECT  43.801 47.04 43.811 71.16 ;
     RECT  43.661 38.304 43.837 39.816 ;
     RECT  43.811 66.48 43.852 71.16 ;
     RECT  43.805 17.52 43.907 20.664 ;
     RECT  42.977 31.248 43.913 31.704 ;
     RECT  43.669 30 43.945 30.168 ;
     RECT  43.913 31.248 43.945 31.512 ;
     RECT  43.873 26.016 43.981 26.04 ;
     RECT  43.837 38.16 43.981 39.816 ;
     RECT  43.657 3.84 44.017 7.464 ;
     RECT  43.715 32.976 44.017 33 ;
     RECT  44.017 32.736 44.021 33 ;
     RECT  43.481 13.008 44.044 14.52 ;
     RECT  43.981 26.016 44.089 26.856 ;
     RECT  42.652 27.888 44.089 28.728 ;
     RECT  44.089 26.016 44.269 28.728 ;
     RECT  44.269 25.776 44.3 28.728 ;
     RECT  43.945 30 44.3 31.512 ;
     RECT  43.811 47.04 44.305 65.496 ;
     RECT  44.197 20.976 44.309 21.096 ;
     RECT  44.044 13.584 44.381 14.52 ;
     RECT  44.309 20.976 44.381 21 ;
     RECT  43.229 74.4 44.396 74.424 ;
     RECT  43.667 1.728 44.413 1.8 ;
     RECT  43.661 40.944 44.417 45.624 ;
     RECT  44.396 73.632 44.437 74.424 ;
     RECT  43.553 34.32 44.483 35.352 ;
     RECT  44.437 73.104 44.483 74.424 ;
     RECT  43.805 22.464 44.485 24.792 ;
     RECT  44.3 25.776 44.485 31.512 ;
     RECT  44.417 40.944 44.489 43.32 ;
     RECT  44.483 73.104 44.521 73.128 ;
     RECT  44.413 1.104 44.531 1.8 ;
     RECT  44.017 3.408 44.533 7.464 ;
     RECT  44.521 72.96 44.561 73.128 ;
     RECT  44.531 1.728 44.629 1.8 ;
     RECT  43.661 8.928 44.629 11.976 ;
     RECT  43.805 15.552 44.629 16.344 ;
     RECT  43.852 68.208 44.629 71.16 ;
     RECT  44.561 72.96 44.633 72.984 ;
     RECT  44.053 37.104 44.701 37.128 ;
     RECT  44.533 2.832 44.737 7.464 ;
     RECT  44.629 8.544 44.737 11.976 ;
     RECT  43.045 0.096 44.765 0.12 ;
     RECT  44.629 15.36 45.013 16.344 ;
     RECT  43.907 17.52 45.013 19.512 ;
     RECT  43.852 66.48 45.025 67.032 ;
     RECT  44.629 68.208 45.025 71.688 ;
     RECT  44.765 0.096 45.137 0.6 ;
     RECT  44.629 1.728 45.145 1.848 ;
     RECT  45.137 0.576 45.217 0.6 ;
     RECT  44.021 32.736 45.313 32.952 ;
     RECT  44.483 34.32 45.313 34.92 ;
     RECT  45.013 15.36 45.421 19.512 ;
     RECT  45.313 21.072 45.421 21.096 ;
     RECT  44.489 42.672 45.452 43.32 ;
     RECT  44.417 44.592 45.452 45.624 ;
     RECT  44.489 40.944 45.457 41.688 ;
     RECT  45.452 42.672 45.457 45.624 ;
     RECT  44.305 46.8 45.493 65.496 ;
     RECT  45.025 66.48 45.493 71.688 ;
     RECT  44.737 2.832 45.529 11.976 ;
     RECT  45.457 40.944 45.529 45.624 ;
     RECT  45.493 46.8 45.529 71.688 ;
     RECT  44.485 22.464 45.565 31.512 ;
     RECT  45.313 32.736 45.565 34.92 ;
     RECT  45.421 15.36 45.601 21.096 ;
     RECT  45.145 1.776 45.608 1.848 ;
     RECT  45.529 2.832 45.608 12.504 ;
     RECT  44.381 13.584 45.608 13.704 ;
     RECT  45.601 14.976 45.608 21.096 ;
     RECT  45.565 22.464 45.608 34.92 ;
     RECT  44.701 36.672 45.608 37.128 ;
     RECT  43.981 38.112 45.608 39.816 ;
     RECT  45.529 40.944 45.608 71.688 ;
     RECT  44.483 74.4 45.608 74.424 ;
     RECT  45.608 1.776 45.712 75.612 ;
     RECT  45.712 1.776 45.857 75.342 ;
     RECT  45.857 2.256 45.904 75.342 ;
     RECT  45.904 18.432 46.001 20.616 ;
     RECT  45.904 14.928 46.109 17.112 ;
     RECT  45.904 44.64 46.115 73.56 ;
     RECT  46.001 18.528 46.253 20.616 ;
     RECT  45.904 31.008 46.325 43.128 ;
     RECT  46.325 31.008 46.433 41.16 ;
     RECT  45.904 28.704 46.469 29.352 ;
     RECT  46.433 31.008 46.469 40.968 ;
     RECT  46.469 28.704 46.505 29.256 ;
     RECT  46.115 44.64 46.505 65.352 ;
     RECT  45.904 23.28 46.547 27.384 ;
     RECT  46.469 31.008 46.721 40.296 ;
     RECT  46.505 44.64 46.721 62.712 ;
     RECT  46.721 31.008 46.757 34.968 ;
     RECT  46.547 23.28 46.787 25.656 ;
     RECT  45.904 2.256 46.793 13.704 ;
     RECT  46.109 14.928 46.793 16.056 ;
     RECT  46.505 28.704 46.829 29.16 ;
     RECT  46.829 28.704 46.835 29.064 ;
     RECT  46.787 23.28 46.892 25.128 ;
     RECT  46.835 28.704 46.937 28.728 ;
     RECT  46.115 66.48 47.041 73.56 ;
     RECT  45.904 74.688 47.041 74.712 ;
     RECT  46.721 44.64 47.084 62.616 ;
     RECT  47.041 66.48 47.123 74.712 ;
     RECT  46.325 42.192 47.125 43.128 ;
     RECT  47.084 44.304 47.125 62.616 ;
     RECT  46.757 34.08 47.153 34.92 ;
     RECT  47.123 72.48 47.164 74.712 ;
     RECT  47.164 74.064 47.221 74.712 ;
     RECT  46.793 9.264 47.257 13.704 ;
     RECT  46.793 14.928 47.257 15.72 ;
     RECT  46.892 22.752 47.257 25.128 ;
     RECT  46.547 26.736 47.329 27.384 ;
     RECT  47.185 28.656 47.329 28.68 ;
     RECT  46.253 18.816 47.365 20.616 ;
     RECT  47.221 74.064 47.365 74.952 ;
     RECT  46.757 31.008 47.369 33.096 ;
     RECT  47.123 66.48 47.441 71.304 ;
     RECT  47.257 22.032 47.461 25.128 ;
     RECT  47.369 31.008 47.473 31.32 ;
     RECT  47.125 42.192 47.477 62.616 ;
     RECT  47.365 18.576 47.507 20.616 ;
     RECT  46.505 63.84 47.545 65.352 ;
     RECT  46.721 36 47.549 40.296 ;
     RECT  46.793 2.256 47.585 8.088 ;
     RECT  47.369 32.304 47.585 33.096 ;
     RECT  46.109 17.088 47.653 17.112 ;
     RECT  47.507 18.576 47.653 19.464 ;
     RECT  47.461 21.648 47.657 25.128 ;
     RECT  47.473 30.72 47.689 31.32 ;
     RECT  47.153 34.8 47.725 34.92 ;
     RECT  47.549 36 47.725 36.984 ;
     RECT  47.441 66.48 47.729 71.16 ;
     RECT  47.477 44.352 47.761 62.616 ;
     RECT  47.545 63.84 47.761 65.496 ;
     RECT  47.725 34.8 47.795 36.984 ;
     RECT  47.549 38.16 47.797 40.296 ;
     RECT  47.329 26.736 47.869 28.68 ;
     RECT  47.797 38.16 47.869 40.632 ;
     RECT  47.477 42.192 47.893 42.84 ;
     RECT  47.365 74.064 47.945 75.192 ;
     RECT  47.653 17.088 48.013 19.464 ;
     RECT  47.761 44.352 48.044 65.496 ;
     RECT  47.729 66.48 48.044 67.8 ;
     RECT  47.729 69.216 48.125 71.16 ;
     RECT  47.257 9.264 48.157 15.72 ;
     RECT  48.013 16.848 48.157 19.464 ;
     RECT  47.164 72.48 48.197 72.744 ;
     RECT  48.157 9.264 48.233 19.464 ;
     RECT  47.869 26.304 48.377 28.68 ;
     RECT  48.044 44.352 48.377 67.8 ;
     RECT  48.233 9.264 48.409 9.864 ;
     RECT  48.125 69.264 48.445 71.16 ;
     RECT  47.795 34.8 48.485 36.6 ;
     RECT  47.585 2.352 48.517 8.088 ;
     RECT  48.409 9.072 48.517 9.864 ;
     RECT  47.689 30.672 48.517 31.32 ;
     RECT  47.585 33.072 48.517 33.096 ;
     RECT  47.869 38.16 48.553 41.112 ;
     RECT  48.517 2.352 48.557 9.864 ;
     RECT  48.553 37.68 48.557 41.112 ;
     RECT  48.517 30.336 48.589 31.32 ;
     RECT  48.485 36.48 48.601 36.6 ;
     RECT  48.589 30.336 48.625 32.04 ;
     RECT  48.517 33.072 48.625 33.576 ;
     RECT  48.557 39.024 48.665 41.112 ;
     RECT  48.233 10.848 48.737 19.464 ;
     RECT  48.737 12.48 48.773 19.464 ;
     RECT  48.557 37.68 48.805 37.704 ;
     RECT  48.665 40.608 48.841 41.112 ;
     RECT  47.893 42.144 48.841 42.84 ;
     RECT  48.841 40.608 48.877 42.84 ;
     RECT  48.877 40.608 48.949 43.032 ;
     RECT  47.657 21.648 48.989 24.936 ;
     RECT  48.625 30.336 49.021 33.576 ;
     RECT  47.507 20.592 49.025 20.616 ;
     RECT  48.989 21.648 49.057 23.928 ;
     RECT  48.377 26.304 49.057 28.392 ;
     RECT  48.949 40.608 49.061 43.08 ;
     RECT  48.773 12.528 49.129 19.464 ;
     RECT  49.129 12.528 49.169 19.944 ;
     RECT  48.601 36.576 49.237 36.6 ;
     RECT  48.805 37.584 49.237 37.704 ;
     RECT  49.057 20.928 49.241 23.928 ;
     RECT  48.377 44.352 49.241 67.656 ;
     RECT  48.557 2.64 49.273 9.864 ;
     RECT  48.737 10.848 49.273 11.256 ;
     RECT  49.169 19.392 49.277 19.944 ;
     RECT  49.241 53.856 49.283 67.656 ;
     RECT  49.061 41.28 49.309 43.08 ;
     RECT  48.445 69.264 49.349 72.408 ;
     RECT  49.021 29.904 49.381 33.576 ;
     RECT  48.485 34.8 49.381 34.968 ;
     RECT  48.989 24.912 49.417 24.936 ;
     RECT  49.237 36.576 49.421 37.704 ;
     RECT  49.417 24.912 49.453 25.08 ;
     RECT  49.057 26.208 49.453 28.392 ;
     RECT  49.283 64.656 49.489 67.656 ;
     RECT  49.349 69.264 49.489 72.024 ;
     RECT  48.665 39.024 49.58 39.624 ;
     RECT  47.945 74.064 49.597 74.952 ;
     RECT  49.169 12.528 49.619 18.216 ;
     RECT  49.309 41.28 49.621 43.32 ;
     RECT  49.241 44.352 49.621 52.872 ;
     RECT  49.381 29.904 49.717 34.968 ;
     RECT  49.717 29.904 49.763 35.4 ;
     RECT  49.489 64.656 49.765 67.8 ;
     RECT  49.763 34.608 49.777 35.4 ;
     RECT  49.58 38.688 49.885 39.624 ;
     RECT  49.597 74.064 49.889 75.144 ;
     RECT  49.273 2.64 49.921 11.256 ;
     RECT  49.889 74.064 49.921 74.856 ;
     RECT  49.921 2.64 49.957 11.448 ;
     RECT  49.421 36.912 49.993 37.704 ;
     RECT  49.885 38.688 49.993 40.056 ;
     RECT  49.957 2.592 50.029 11.448 ;
     RECT  49.619 12.528 50.029 12.552 ;
     RECT  49.777 34.608 50.137 35.544 ;
     RECT  49.489 69.072 50.173 72.024 ;
     RECT  50.137 20.16 50.245 20.184 ;
     RECT  49.241 21.504 50.245 23.928 ;
     RECT  49.453 24.912 50.245 25.176 ;
     RECT  49.993 36.912 50.281 40.056 ;
     RECT  49.619 13.92 50.317 18.216 ;
     RECT  50.281 36.912 50.417 40.152 ;
     RECT  49.621 41.28 50.417 52.872 ;
     RECT  50.417 36.912 50.437 52.872 ;
     RECT  49.283 53.856 50.437 63.528 ;
     RECT  50.029 2.592 50.533 12.552 ;
     RECT  50.245 20.16 50.533 25.176 ;
     RECT  49.453 26.208 50.533 28.44 ;
     RECT  50.173 68.976 50.533 72.024 ;
     RECT  50.137 34.608 50.677 35.736 ;
     RECT  49.765 64.656 50.677 67.896 ;
     RECT  50.533 68.976 50.821 72.312 ;
     RECT  50.677 34.608 50.857 35.784 ;
     RECT  49.763 29.904 50.869 33.576 ;
     RECT  50.677 64.656 50.893 67.944 ;
     RECT  50.821 68.976 50.893 72.456 ;
     RECT  50.533 20.16 50.965 28.44 ;
     RECT  50.533 2.256 51.008 12.552 ;
     RECT  50.317 13.92 51.008 18.648 ;
     RECT  50.965 20.064 51.008 28.728 ;
     RECT  50.869 29.808 51.008 33.576 ;
     RECT  50.857 34.608 51.008 35.88 ;
     RECT  50.437 36.912 51.008 63.528 ;
     RECT  50.893 64.656 51.008 72.456 ;
     RECT  49.921 73.536 51.008 74.856 ;
     RECT  51.008 2.148 51.112 75.612 ;
     RECT  51.112 2.148 51.304 75.342 ;
     RECT  51.304 34.656 51.329 40.392 ;
     RECT  51.304 43.632 51.437 65.16 ;
     RECT  51.329 34.656 51.473 40.344 ;
     RECT  51.304 41.472 51.473 42.6 ;
     RECT  51.304 3.264 51.545 29.208 ;
     RECT  51.469 0.576 51.553 0.6 ;
     RECT  51.473 41.712 51.581 42.6 ;
     RECT  51.545 25.008 51.689 29.208 ;
     RECT  51.589 1.728 51.725 1.896 ;
     RECT  51.437 43.632 51.761 65.112 ;
     RECT  51.761 43.632 51.797 64.68 ;
     RECT  51.725 1.776 51.869 1.896 ;
     RECT  51.797 51.456 51.923 64.68 ;
     RECT  51.304 30.192 51.941 30.984 ;
     RECT  51.877 0.096 52.013 0.12 ;
     RECT  51.545 3.264 52.293 24.024 ;
     RECT  51.581 41.952 52.297 42.6 ;
     RECT  51.797 43.632 52.297 49.944 ;
     RECT  51.304 68.928 52.297 72.024 ;
     RECT  51.304 73.008 52.297 74.904 ;
     RECT  51.941 30.864 52.405 30.984 ;
     RECT  51.304 32.304 52.405 33.576 ;
     RECT  52.297 68.928 52.445 74.904 ;
     RECT  52.293 3.264 52.451 6.312 ;
     RECT  52.445 68.928 52.481 71.352 ;
     RECT  52.405 30.864 52.517 33.576 ;
     RECT  51.689 25.248 52.585 29.208 ;
     RECT  52.293 7.344 52.621 24.024 ;
     RECT  52.297 41.952 52.661 49.944 ;
     RECT  52.481 68.928 52.693 71.304 ;
     RECT  52.517 32.256 52.729 33.576 ;
     RECT  51.473 34.752 52.729 40.344 ;
     RECT  52.451 3.264 52.789 6.072 ;
     RECT  52.693 68.88 52.913 71.304 ;
     RECT  52.789 2.64 52.949 6.072 ;
     RECT  52.729 32.256 52.981 40.344 ;
     RECT  52.661 41.952 52.981 48.936 ;
     RECT  51.923 51.456 52.985 60.888 ;
     RECT  52.985 54.672 53.017 60.888 ;
     RECT  51.923 62.16 53.017 64.68 ;
     RECT  53.017 54.672 53.029 64.68 ;
     RECT  52.621 7.344 53.057 24.168 ;
     RECT  51.304 66.48 53.057 67.656 ;
     RECT  53.057 20.496 53.161 24.168 ;
     RECT  52.585 25.248 53.161 29.592 ;
     RECT  53.161 20.496 53.201 29.592 ;
     RECT  52.517 30.864 53.201 31.224 ;
     RECT  53.201 30.864 53.237 31.128 ;
     RECT  53.057 7.344 53.273 19.32 ;
     RECT  53.029 54.672 53.305 65.016 ;
     RECT  53.201 21.648 53.309 29.592 ;
     RECT  53.237 30.864 53.309 30.984 ;
     RECT  52.445 72.816 53.363 74.904 ;
     RECT  53.057 66.48 53.377 67.368 ;
     RECT  53.305 54.672 53.489 65.208 ;
     RECT  52.949 3.264 53.521 6.072 ;
     RECT  53.273 7.344 53.521 14.136 ;
     RECT  52.661 49.92 53.521 49.944 ;
     RECT  53.377 66.336 53.521 67.368 ;
     RECT  52.913 68.88 53.629 71.16 ;
     RECT  53.521 3.264 53.633 14.136 ;
     RECT  53.273 15.792 53.633 19.32 ;
     RECT  52.981 32.256 53.633 48.936 ;
     RECT  53.363 73.392 53.633 74.904 ;
     RECT  53.521 49.92 53.749 50.184 ;
     RECT  52.985 51.456 53.749 53.544 ;
     RECT  53.749 49.92 53.836 53.544 ;
     RECT  53.633 34.128 53.921 48.936 ;
     RECT  53.633 73.872 53.921 74.904 ;
     RECT  53.201 20.496 53.993 20.52 ;
     RECT  53.921 73.968 53.993 74.904 ;
     RECT  53.309 21.648 54.035 25.032 ;
     RECT  53.921 34.128 54.101 37.224 ;
     RECT  53.521 65.712 54.133 67.368 ;
     RECT  53.629 68.352 54.133 71.16 ;
     RECT  53.309 26.112 54.173 29.592 ;
     RECT  53.921 38.256 54.245 48.936 ;
     RECT  53.836 51.984 54.317 53.544 ;
     RECT  53.489 54.672 54.317 64.728 ;
     RECT  53.633 3.264 54.349 9.624 ;
     RECT  53.633 10.656 54.385 14.136 ;
     RECT  54.385 10.656 54.457 14.232 ;
     RECT  54.457 10.656 54.476 14.424 ;
     RECT  53.633 15.792 54.476 19.272 ;
     RECT  54.245 41.424 54.493 48.936 ;
     RECT  53.836 49.92 54.493 50.28 ;
     RECT  54.035 21.696 54.497 25.032 ;
     RECT  54.476 10.656 54.563 19.272 ;
     RECT  54.497 23.088 54.565 25.032 ;
     RECT  54.173 26.112 54.565 29.256 ;
     RECT  54.349 2.784 54.601 9.624 ;
     RECT  54.317 52.176 54.601 53.544 ;
     RECT  54.317 54.672 54.601 59.544 ;
     RECT  54.563 15.792 54.641 19.272 ;
     RECT  54.317 60.576 54.641 64.728 ;
     RECT  54.601 2.256 54.673 9.624 ;
     RECT  54.563 10.656 54.673 14.424 ;
     RECT  53.993 74.448 54.673 74.904 ;
     RECT  53.309 30.864 54.745 30.888 ;
     RECT  54.133 65.712 54.812 71.16 ;
     RECT  54.097 72.144 54.812 72.168 ;
     RECT  54.812 65.712 54.821 72.168 ;
     RECT  54.821 68.208 54.853 72.168 ;
     RECT  54.641 60.576 54.857 62.568 ;
     RECT  54.853 68.208 54.899 72.408 ;
     RECT  54.101 34.752 54.925 37.224 ;
     RECT  54.673 2.256 54.929 14.424 ;
     RECT  54.565 23.088 54.965 29.256 ;
     RECT  54.965 23.616 55.037 29.256 ;
     RECT  54.673 74.448 55.069 75.24 ;
     RECT  53.633 32.256 55.105 32.76 ;
     RECT  54.925 34.752 55.105 37.368 ;
     RECT  55.105 32.208 55.141 32.76 ;
     RECT  54.641 16.032 55.177 19.272 ;
     RECT  55.105 34.704 55.177 37.368 ;
     RECT  54.821 65.808 55.181 66.6 ;
     RECT  54.245 38.496 55.213 40.344 ;
     RECT  54.493 41.424 55.213 50.28 ;
     RECT  55.141 32.064 55.249 32.76 ;
     RECT  55.177 34.656 55.249 37.368 ;
     RECT  55.181 65.808 55.325 66.552 ;
     RECT  55.069 74.064 55.325 75.24 ;
     RECT  55.213 38.496 55.357 50.28 ;
     RECT  54.601 52.176 55.357 59.544 ;
     RECT  54.745 30.384 55.393 30.888 ;
     RECT  55.249 32.064 55.393 33.384 ;
     RECT  54.929 2.256 55.397 6.12 ;
     RECT  54.899 72.384 55.429 72.408 ;
     RECT  55.325 66 55.433 66.552 ;
     RECT  55.393 30.384 55.465 33.384 ;
     RECT  55.357 38.496 55.501 59.544 ;
     RECT  55.501 38.496 55.637 59.592 ;
     RECT  54.857 60.576 55.637 62.328 ;
     RECT  54.497 21.696 55.645 21.72 ;
     RECT  55.249 34.608 55.861 37.368 ;
     RECT  55.637 38.496 55.889 62.328 ;
     RECT  54.641 63.6 55.889 64.728 ;
     RECT  54.929 7.2 55.969 14.424 ;
     RECT  55.889 38.496 55.969 64.728 ;
     RECT  55.177 16.032 56.005 19.848 ;
     RECT  55.429 72.384 56.149 72.456 ;
     RECT  55.861 34.608 56.185 37.416 ;
     RECT  55.969 38.496 56.185 64.968 ;
     RECT  55.037 27.744 56.221 29.256 ;
     RECT  55.465 30.384 56.221 33.48 ;
     RECT  56.221 27.744 56.293 33.48 ;
     RECT  56.185 34.608 56.293 64.968 ;
     RECT  55.433 66 56.293 66.504 ;
     RECT  55.037 23.616 56.329 26.712 ;
     RECT  56.293 27.744 56.329 66.504 ;
     RECT  55.325 74.448 56.329 75.24 ;
     RECT  55.645 21.696 56.365 22.344 ;
     RECT  56.329 23.616 56.365 66.504 ;
     RECT  56.365 21.696 56.401 66.504 ;
     RECT  55.397 2.88 56.408 6.12 ;
     RECT  55.969 7.152 56.408 14.424 ;
     RECT  56.005 15.84 56.408 19.848 ;
     RECT  56.401 21.696 56.408 66.84 ;
     RECT  54.899 68.208 56.408 71.16 ;
     RECT  56.149 72.384 56.408 72.84 ;
     RECT  56.329 73.872 56.408 75.24 ;
     RECT  56.408 2.148 56.512 75.612 ;
     RECT  56.512 2.418 56.704 75.342 ;
     RECT  56.704 15.696 56.819 32.616 ;
     RECT  56.704 69.264 56.819 71.256 ;
     RECT  56.704 52.272 56.917 66.744 ;
     RECT  56.917 52.272 56.981 66.264 ;
     RECT  56.704 72.24 56.981 72.936 ;
     RECT  56.819 20.928 57.017 32.616 ;
     RECT  57.017 20.928 57.053 27.96 ;
     RECT  56.704 43.104 57.089 51.144 ;
     RECT  56.819 15.696 57.269 19.944 ;
     RECT  56.704 68.208 57.305 68.232 ;
     RECT  56.981 72.288 57.485 72.936 ;
     RECT  56.981 52.272 57.593 64.392 ;
     RECT  57.089 43.104 57.629 44.904 ;
     RECT  57.089 45.984 57.629 51.144 ;
     RECT  57.593 52.272 57.629 53.592 ;
     RECT  57.017 29.04 57.701 32.616 ;
     RECT  57.701 29.76 57.737 32.616 ;
     RECT  56.704 2.88 57.805 14.424 ;
     RECT  57.269 15.696 57.805 19.464 ;
     RECT  56.704 74.352 57.841 74.904 ;
     RECT  56.704 34.08 57.877 37.128 ;
     RECT  56.704 38.496 57.877 42.072 ;
     RECT  57.629 45.984 57.917 50.904 ;
     RECT  57.629 52.272 57.985 52.536 ;
     RECT  56.819 70.368 57.989 71.256 ;
     RECT  57.737 30.672 58.021 32.616 ;
     RECT  57.877 34.08 58.021 42.072 ;
     RECT  58.021 30.672 58.069 42.072 ;
     RECT  57.485 72.432 58.079 72.936 ;
     RECT  57.841 74.352 58.079 75.24 ;
     RECT  57.989 70.368 58.093 71.16 ;
     RECT  57.629 43.92 58.129 44.904 ;
     RECT  57.917 45.984 58.129 50.184 ;
     RECT  56.819 69.264 58.129 69.288 ;
     RECT  58.093 70.32 58.129 71.16 ;
     RECT  58.079 72.432 58.169 75.24 ;
     RECT  57.053 20.928 58.309 27.912 ;
     RECT  57.805 2.88 58.345 19.464 ;
     RECT  58.309 20.448 58.345 27.912 ;
     RECT  57.985 51.936 58.349 52.536 ;
     RECT  58.345 2.88 58.421 27.912 ;
     RECT  58.129 0.528 58.451 0.552 ;
     RECT  57.593 54.768 58.525 64.392 ;
     RECT  56.981 65.472 58.525 66.264 ;
     RECT  58.129 69.264 58.525 71.16 ;
     RECT  58.525 54.768 58.561 66.264 ;
     RECT  57.949 67.488 58.561 67.512 ;
     RECT  58.421 2.88 58.565 20.088 ;
     RECT  58.169 72.432 58.597 74.904 ;
     RECT  58.129 43.92 58.601 50.184 ;
     RECT  58.561 54.768 58.633 67.512 ;
     RECT  58.633 54.72 58.645 67.512 ;
     RECT  58.349 52.272 58.705 52.536 ;
     RECT  57.629 53.52 58.705 53.544 ;
     RECT  58.069 30.672 58.741 42.792 ;
     RECT  58.705 52.272 58.741 53.544 ;
     RECT  58.645 54.72 58.741 67.608 ;
     RECT  58.741 30.672 58.777 43.368 ;
     RECT  58.597 72.144 58.78 74.904 ;
     RECT  58.78 72.144 58.817 74.808 ;
     RECT  58.565 2.88 58.949 12.552 ;
     RECT  58.525 68.88 58.957 71.16 ;
     RECT  58.817 72.144 58.957 74.616 ;
     RECT  58.565 13.536 58.961 20.088 ;
     RECT  58.949 2.832 59.033 12.552 ;
     RECT  58.741 52.272 59.177 67.608 ;
     RECT  59.033 2.88 59.219 12.552 ;
     RECT  58.777 30.24 59.285 43.368 ;
     RECT  58.693 0.096 59.321 0.216 ;
     RECT  59.285 30.24 59.321 36.888 ;
     RECT  59.177 53.52 59.321 67.608 ;
     RECT  58.601 44.4 59.4 50.184 ;
     RECT  58.813 29.04 59.42 29.064 ;
     RECT  59.321 30.24 59.42 32.04 ;
     RECT  58.961 19.776 59.425 20.088 ;
     RECT  58.421 21.36 59.425 27.912 ;
     RECT  59.321 33.024 59.429 36.888 ;
     RECT  59.4 44.4 59.429 50.376 ;
     RECT  59.321 0.144 59.437 0.216 ;
     RECT  59.321 60.768 59.461 67.608 ;
     RECT  58.957 68.88 59.461 74.616 ;
     RECT  59.177 52.272 59.501 52.536 ;
     RECT  59.42 29.04 59.507 32.04 ;
     RECT  59.429 33.024 59.609 36.696 ;
     RECT  59.429 45.696 59.641 50.376 ;
     RECT  59.219 2.88 59.645 4.008 ;
     RECT  59.461 60.768 59.681 74.616 ;
     RECT  59.641 45.696 59.756 50.424 ;
     RECT  59.219 5.136 59.821 12.552 ;
     RECT  58.961 13.536 59.821 18.792 ;
     RECT  59.285 37.872 59.861 43.368 ;
     RECT  59.861 37.872 59.933 42.696 ;
     RECT  59.425 19.776 59.965 27.912 ;
     RECT  59.507 29.04 59.965 29.064 ;
     RECT  59.429 44.4 59.965 44.712 ;
     RECT  59.681 60.96 59.969 74.616 ;
     RECT  58.453 1.728 60.001 1.752 ;
     RECT  59.645 3.36 60.229 4.008 ;
     RECT  59.821 5.136 60.229 18.792 ;
     RECT  60.001 1.728 60.371 2.28 ;
     RECT  59.507 30.192 60.373 32.04 ;
     RECT  59.609 33.024 60.373 36.6 ;
     RECT  59.437 0.192 60.421 0.216 ;
     RECT  59.756 45.696 60.421 50.616 ;
     RECT  60.421 0.096 60.433 0.216 ;
     RECT  59.965 44.16 60.469 44.712 ;
     RECT  60.421 45.696 60.469 50.76 ;
     RECT  59.501 52.272 60.541 52.44 ;
     RECT  59.321 53.52 60.541 59.784 ;
     RECT  60.373 30.192 60.545 36.6 ;
     RECT  60.469 44.16 60.545 50.76 ;
     RECT  60.229 3.36 60.649 18.792 ;
     RECT  59.965 19.776 60.649 29.064 ;
     RECT  60.545 30.192 60.653 32.04 ;
     RECT  60.433 0.096 60.659 0.6 ;
     RECT  60.649 3.36 60.685 29.064 ;
     RECT  60.653 30.192 60.685 31.896 ;
     RECT  60.541 52.272 60.793 59.784 ;
     RECT  59.969 60.96 60.793 63.144 ;
     RECT  59.933 37.872 61.009 42.552 ;
     RECT  60.545 33.072 61.045 36.6 ;
     RECT  61.009 37.872 61.045 42.648 ;
     RECT  60.965 77.616 61.048 77.64 ;
     RECT  60.659 0.096 61.049 0.552 ;
     RECT  60.793 52.272 61.297 63.144 ;
     RECT  59.969 64.128 61.297 74.616 ;
     RECT  60.371 1.728 61.33 1.848 ;
     RECT  60.685 3.36 61.369 31.896 ;
     RECT  61.33 1.68 61.453 1.848 ;
     RECT  60.545 44.16 61.573 50.184 ;
     RECT  61.297 52.272 61.585 75.288 ;
     RECT  61.153 76.368 61.715 76.392 ;
     RECT  61.453 1.728 61.765 1.848 ;
     RECT  61.369 2.832 61.765 31.896 ;
     RECT  61.585 51.456 61.765 75.288 ;
     RECT  61.765 1.728 61.808 31.896 ;
     RECT  61.045 33.072 61.808 42.648 ;
     RECT  61.573 44.16 61.808 50.424 ;
     RECT  61.765 51.456 61.808 75.816 ;
     RECT  61.049 0.144 62.017 0.552 ;
     RECT  61.808 1.728 62.104 75.816 ;
     RECT  61.048 77.568 62.149 77.64 ;
     RECT  62.104 2.88 62.165 35.112 ;
     RECT  62.104 36.096 62.165 75.816 ;
     RECT  62.165 25.2 62.345 35.112 ;
     RECT  62.165 36.528 62.489 75.816 ;
     RECT  62.489 37.104 62.561 75.816 ;
     RECT  62.561 37.104 62.597 73.512 ;
     RECT  62.345 25.2 62.705 29.592 ;
     RECT  62.597 43.44 62.705 73.512 ;
     RECT  62.705 43.536 62.777 73.512 ;
     RECT  62.705 26.496 62.813 29.592 ;
     RECT  62.777 52.176 62.819 73.512 ;
     RECT  62.017 0.096 62.845 0.552 ;
     RECT  62.813 26.496 62.921 27.912 ;
     RECT  62.597 37.104 62.921 42.312 ;
     RECT  62.819 53.52 62.921 73.512 ;
     RECT  62.561 74.496 62.953 75.816 ;
     RECT  62.149 76.944 62.953 77.64 ;
     RECT  62.819 52.176 63.059 52.44 ;
     RECT  62.845 0.096 63.155 0.6 ;
     RECT  62.104 1.728 63.164 1.8 ;
     RECT  62.165 2.88 63.164 24.12 ;
     RECT  62.705 25.2 63.209 25.32 ;
     RECT  62.345 30.816 63.241 35.112 ;
     RECT  62.777 43.536 63.245 50.712 ;
     RECT  62.953 74.496 63.251 77.64 ;
     RECT  63.241 30.816 63.308 35.448 ;
     RECT  63.164 1.728 63.353 24.12 ;
     RECT  63.308 30.816 63.353 35.976 ;
     RECT  63.245 43.536 63.353 50.664 ;
     RECT  63.353 1.728 63.389 23.832 ;
     RECT  63.251 76.368 63.443 77.64 ;
     RECT  63.389 1.728 63.461 23.4 ;
     RECT  63.461 1.728 63.484 22.824 ;
     RECT  63.353 30.816 63.493 32.088 ;
     RECT  63.353 33.312 63.497 35.976 ;
     RECT  63.353 43.872 63.533 50.664 ;
     RECT  62.813 29.04 63.539 29.592 ;
     RECT  62.921 62.208 63.557 73.512 ;
     RECT  63.251 74.496 63.557 75.144 ;
     RECT  63.497 33.312 63.569 34.392 ;
     RECT  63.059 52.176 63.569 52.2 ;
     RECT  63.484 1.728 63.605 13.944 ;
     RECT  63.493 30.576 63.605 32.088 ;
     RECT  62.921 42.24 63.709 42.312 ;
     RECT  62.921 53.52 63.781 61.032 ;
     RECT  63.569 33.312 63.857 34.344 ;
     RECT  63.497 35.424 63.893 35.976 ;
     RECT  63.781 53.376 63.997 61.032 ;
     RECT  63.557 62.208 63.997 75.144 ;
     RECT  63.997 53.376 64.001 75.144 ;
     RECT  62.921 37.104 64.033 41.256 ;
     RECT  63.709 42.24 64.033 42.84 ;
     RECT  62.921 26.496 64.141 27.48 ;
     RECT  64.001 61.968 64.145 75.144 ;
     RECT  63.605 1.728 64.211 13.128 ;
     RECT  64.145 61.968 64.259 74.76 ;
     RECT  64.141 26.496 64.321 27.912 ;
     RECT  64.211 1.824 64.403 13.128 ;
     RECT  64.033 37.104 64.453 42.84 ;
     RECT  64.453 37.104 64.465 42.888 ;
     RECT  63.533 43.872 64.465 50.568 ;
     RECT  64.001 53.376 64.465 60.6 ;
     RECT  64.403 2.208 64.499 13.128 ;
     RECT  63.893 35.952 64.501 35.976 ;
     RECT  64.465 52.704 64.505 60.6 ;
     RECT  63.493 25.104 64.537 25.128 ;
     RECT  63.484 15.024 64.547 22.824 ;
     RECT  64.259 61.968 64.613 74.664 ;
     RECT  64.499 2.304 64.717 13.128 ;
     RECT  63.605 30.624 64.717 32.088 ;
     RECT  63.857 33.312 64.717 34.2 ;
     RECT  64.321 26.256 64.789 27.912 ;
     RECT  63.539 29.232 64.789 29.592 ;
     RECT  64.501 35.952 64.789 36.024 ;
     RECT  64.537 24.912 64.861 25.128 ;
     RECT  64.789 26.256 64.861 29.592 ;
     RECT  64.505 52.704 64.861 60.552 ;
     RECT  64.717 2.304 64.897 13.608 ;
     RECT  64.547 20.496 64.897 22.824 ;
     RECT  64.897 2.304 64.901 13.704 ;
     RECT  64.547 15.024 64.933 19.416 ;
     RECT  64.717 30.624 64.933 34.2 ;
     RECT  64.789 35.952 64.933 36.12 ;
     RECT  64.465 37.104 64.933 50.568 ;
     RECT  64.933 30.624 64.981 34.632 ;
     RECT  64.933 35.952 64.981 50.568 ;
     RECT  64.897 20.496 65.077 22.872 ;
     RECT  64.861 24.096 65.077 29.592 ;
     RECT  63.155 0.096 65.081 0.12 ;
     RECT  64.933 14.688 65.153 19.416 ;
     RECT  65.153 15.024 65.189 19.416 ;
     RECT  65.029 75.792 65.221 75.816 ;
     RECT  63.443 76.896 65.221 77.64 ;
     RECT  64.861 51.744 65.225 60.552 ;
     RECT  64.613 62.16 65.369 74.664 ;
     RECT  65.369 63.264 65.461 74.664 ;
     RECT  64.981 30.624 65.509 50.568 ;
     RECT  65.225 51.888 65.509 60.552 ;
     RECT  65.509 51.888 65.549 60.984 ;
     RECT  65.461 63.264 65.549 74.712 ;
     RECT  65.077 20.496 65.603 29.592 ;
     RECT  65.221 75.792 65.657 77.64 ;
     RECT  65.657 76.368 65.981 77.64 ;
     RECT  64.901 2.832 66.121 13.704 ;
     RECT  65.981 76.608 66.121 77.64 ;
     RECT  66.121 2.832 66.157 13.944 ;
     RECT  65.603 25.008 66.229 29.592 ;
     RECT  65.509 30.624 66.229 50.856 ;
     RECT  65.189 15.264 66.337 19.416 ;
     RECT  65.603 20.496 66.337 23.976 ;
     RECT  66.229 25.008 66.373 50.856 ;
     RECT  65.549 51.888 66.373 58.68 ;
     RECT  65.549 59.712 66.517 60.984 ;
     RECT  65.369 62.16 66.517 62.232 ;
     RECT  66.517 59.712 66.625 62.232 ;
     RECT  65.549 63.264 66.625 74.136 ;
     RECT  66.337 15.264 66.661 23.976 ;
     RECT  66.373 25.008 66.661 58.68 ;
     RECT  66.157 2.496 66.805 13.944 ;
     RECT  66.625 59.712 66.877 74.136 ;
     RECT  66.805 2.496 66.949 14.136 ;
     RECT  66.661 15.264 66.949 58.68 ;
     RECT  66.949 2.496 67.208 58.68 ;
     RECT  66.877 59.712 67.208 74.184 ;
     RECT  67.208 2.148 67.312 75.612 ;
     RECT  67.312 2.256 67.504 75.342 ;
     RECT  66.121 76.608 67.601 77.736 ;
     RECT  67.504 30.624 67.709 61.656 ;
     RECT  67.504 14.352 67.853 29.256 ;
     RECT  67.709 30.624 67.853 55.992 ;
     RECT  67.601 77.712 68.285 77.736 ;
     RECT  67.504 2.256 68.291 13.128 ;
     RECT  67.853 37.44 68.291 55.992 ;
     RECT  68.291 44.736 68.428 55.992 ;
     RECT  67.853 14.352 68.524 29.064 ;
     RECT  67.601 76.608 68.645 76.632 ;
     RECT  68.524 14.352 68.717 27.384 ;
     RECT  67.709 57.024 68.785 61.656 ;
     RECT  67.504 62.736 68.785 74.76 ;
     RECT  68.428 55.104 68.789 55.992 ;
     RECT  68.291 37.44 68.861 43.608 ;
     RECT  68.785 57.024 68.897 74.76 ;
     RECT  68.291 2.736 68.929 13.128 ;
     RECT  68.717 14.352 68.929 26.808 ;
     RECT  68.929 2.736 68.933 26.808 ;
     RECT  67.853 30.624 68.969 36.456 ;
     RECT  68.933 2.736 69.005 26.616 ;
     RECT  68.969 30.624 69.073 31.512 ;
     RECT  68.524 28.416 69.145 29.064 ;
     RECT  68.969 32.688 69.217 36.456 ;
     RECT  68.861 37.44 69.217 39.24 ;
     RECT  68.897 57.792 69.251 74.76 ;
     RECT  68.428 44.736 69.293 54.072 ;
     RECT  69.073 30.384 69.329 31.512 ;
     RECT  69.217 32.688 69.473 39.24 ;
     RECT  69.329 30.384 69.613 31.464 ;
     RECT  69.005 2.832 69.653 26.616 ;
     RECT  68.861 40.32 69.685 43.608 ;
     RECT  69.251 58.128 69.761 74.76 ;
     RECT  69.293 44.736 69.797 53.64 ;
     RECT  69.685 40.32 69.869 43.704 ;
     RECT  69.473 33.552 69.884 39.24 ;
     RECT  69.869 40.32 69.884 43.512 ;
     RECT  69.145 28.416 69.893 29.112 ;
     RECT  69.613 30.192 69.893 31.464 ;
     RECT  68.789 55.2 69.901 55.992 ;
     RECT  69.865 56.976 69.901 57 ;
     RECT  69.653 2.832 69.905 21.24 ;
     RECT  69.893 28.416 69.977 31.464 ;
     RECT  69.884 33.552 70.013 43.512 ;
     RECT  70.117 0.144 70.189 0.168 ;
     RECT  69.977 28.416 70.193 29.016 ;
     RECT  69.653 22.416 70.225 26.616 ;
     RECT  69.977 30.096 70.297 31.464 ;
     RECT  69.901 55.2 70.301 57 ;
     RECT  69.761 58.128 70.445 74.568 ;
     RECT  70.297 30.096 70.513 31.992 ;
     RECT  70.193 28.416 70.589 28.824 ;
     RECT  70.445 58.128 70.625 67.704 ;
     RECT  70.225 22.416 70.729 27.144 ;
     RECT  70.301 56.832 70.729 57 ;
     RECT  70.625 58.128 70.729 63.672 ;
     RECT  70.445 68.736 70.733 74.568 ;
     RECT  70.189 0.144 70.765 0.552 ;
     RECT  69.905 5.232 70.873 21.24 ;
     RECT  70.013 35.424 70.877 43.512 ;
     RECT  70.013 33.552 71.017 34.44 ;
     RECT  70.877 35.424 71.017 39.096 ;
     RECT  70.513 30.096 71.089 32.424 ;
     RECT  69.797 49.824 71.129 53.592 ;
     RECT  70.729 22.416 71.221 27.384 ;
     RECT  70.733 71.136 71.237 74.568 ;
     RECT  69.905 2.832 71.261 3.96 ;
     RECT  70.873 5.136 71.261 21.24 ;
     RECT  70.589 28.752 71.267 28.824 ;
     RECT  71.261 2.832 71.269 21.24 ;
     RECT  71.221 22.416 71.269 27.624 ;
     RECT  70.301 55.2 71.269 55.848 ;
     RECT  70.729 56.832 71.269 63.672 ;
     RECT  69.797 44.736 71.273 48.744 ;
     RECT  71.267 28.8 71.305 28.824 ;
     RECT  71.089 30.096 71.305 32.472 ;
     RECT  70.765 0.144 71.333 0.6 ;
     RECT  71.305 28.8 71.341 32.472 ;
     RECT  71.017 33.552 71.341 39.096 ;
     RECT  70.877 40.08 71.453 43.512 ;
     RECT  71.333 0.096 71.507 0.6 ;
     RECT  71.269 2.832 71.525 27.624 ;
     RECT  71.129 50.016 71.597 53.592 ;
     RECT  70.909 1.728 71.629 1.752 ;
     RECT  71.597 50.064 71.701 53.592 ;
     RECT  71.269 55.2 71.701 63.672 ;
     RECT  71.701 50.064 71.737 63.672 ;
     RECT  70.625 64.704 71.737 67.704 ;
     RECT  71.273 46.128 71.749 48.744 ;
     RECT  71.737 50.064 71.809 67.704 ;
     RECT  70.733 68.736 71.809 70.104 ;
     RECT  71.453 40.368 71.852 43.512 ;
     RECT  71.273 44.736 71.852 45 ;
     RECT  71.749 46.128 72.313 48.936 ;
     RECT  71.525 22.464 72.385 27.624 ;
     RECT  71.341 28.8 72.385 39.096 ;
     RECT  71.629 1.728 72.421 1.8 ;
     RECT  71.852 40.368 72.421 45 ;
     RECT  72.313 46.128 72.421 48.984 ;
     RECT  71.507 0.096 72.529 0.552 ;
     RECT  72.421 1.728 72.608 1.848 ;
     RECT  71.525 2.832 72.608 21.48 ;
     RECT  72.385 22.464 72.608 39.096 ;
     RECT  72.421 40.128 72.608 48.984 ;
     RECT  71.809 50.064 72.608 70.104 ;
     RECT  71.237 71.136 72.608 74.136 ;
     RECT  72.608 1.728 72.712 75.612 ;
     RECT  72.529 0.096 72.755 0.6 ;
     RECT  72.712 1.728 72.904 75.432 ;
     RECT  72.904 26.88 72.965 53.592 ;
     RECT  72.904 55.296 72.965 75.432 ;
     RECT  72.755 0.096 73.043 0.216 ;
     RECT  72.965 65.184 73.043 75.432 ;
     RECT  72.965 26.928 73.187 53.592 ;
     RECT  73.043 65.184 73.217 75 ;
     RECT  72.904 1.728 73.253 1.848 ;
     RECT  73.187 43.056 73.325 53.592 ;
     RECT  72.904 2.832 73.397 25.752 ;
     RECT  73.043 0.096 73.649 0.168 ;
     RECT  73.253 1.728 73.657 1.752 ;
     RECT  73.187 26.928 73.757 41.784 ;
     RECT  72.965 55.296 73.933 64.152 ;
     RECT  73.933 55.008 74.041 64.152 ;
     RECT  73.217 65.184 74.041 65.496 ;
     RECT  74.041 55.008 74.185 65.496 ;
     RECT  73.217 66.48 74.185 75 ;
     RECT  73.325 43.056 74.225 53.544 ;
     RECT  73.397 18.72 74.329 25.752 ;
     RECT  73.757 26.928 74.329 39.048 ;
     RECT  73.397 2.832 74.339 17.592 ;
     RECT  74.185 55.008 74.369 75 ;
     RECT  74.339 3.312 74.396 17.592 ;
     RECT  74.329 18.72 74.396 39.048 ;
     RECT  74.225 43.056 74.396 53.352 ;
     RECT  73.757 40.176 74.509 41.784 ;
     RECT  74.396 42.768 74.509 53.352 ;
     RECT  74.396 3.312 74.585 39.048 ;
     RECT  73.649 0.144 74.621 0.168 ;
     RECT  74.369 62.544 74.627 75 ;
     RECT  74.627 67.728 74.693 75 ;
     RECT  74.369 55.008 74.725 61.368 ;
     RECT  74.509 40.176 74.915 53.352 ;
     RECT  74.693 67.824 74.977 75 ;
     RECT  74.725 54.816 75.053 61.368 ;
     RECT  75.053 60.288 75.125 61.368 ;
     RECT  74.627 62.544 75.125 66.744 ;
     RECT  74.653 2.256 75.161 2.28 ;
     RECT  74.585 26.208 75.193 39.048 ;
     RECT  75.053 54.816 75.251 58.968 ;
     RECT  75.193 26.208 75.269 39.48 ;
     RECT  74.585 3.312 75.337 21.816 ;
     RECT  74.915 40.8 75.449 53.352 ;
     RECT  75.251 54.816 75.517 55.8 ;
     RECT  75.125 62.736 75.521 66.744 ;
     RECT  75.449 48.48 75.553 53.352 ;
     RECT  75.517 54.672 75.553 55.8 ;
     RECT  75.337 3.264 75.685 21.816 ;
     RECT  74.585 22.896 75.685 25.224 ;
     RECT  75.553 48.48 75.701 55.8 ;
     RECT  74.977 67.824 75.737 75.144 ;
     RECT  75.685 3.072 75.772 25.224 ;
     RECT  75.772 22.896 75.788 25.224 ;
     RECT  75.269 26.208 75.788 26.232 ;
     RECT  75.125 60.384 75.809 61.368 ;
     RECT  75.737 70.608 75.845 75.144 ;
     RECT  75.521 65.472 75.917 66.744 ;
     RECT  75.917 66.24 75.953 66.744 ;
     RECT  75.845 71.376 75.971 75.144 ;
     RECT  75.953 66.336 75.989 66.744 ;
     RECT  75.989 66.384 76.021 66.744 ;
     RECT  75.737 67.824 76.021 69.288 ;
     RECT  75.701 54.048 76.025 55.8 ;
     RECT  75.971 71.424 76.025 75.144 ;
     RECT  75.269 27.696 76.057 39.48 ;
     RECT  75.449 40.8 76.057 47.496 ;
     RECT  76.057 27.696 76.061 47.496 ;
     RECT  76.025 71.424 76.133 73.08 ;
     RECT  76.025 74.064 76.229 75.144 ;
     RECT  75.701 48.48 76.241 53.064 ;
     RECT  76.061 27.696 76.259 40.824 ;
     RECT  75.772 3.264 76.277 21.72 ;
     RECT  76.229 74.064 76.313 75.288 ;
     RECT  75.251 57.024 76.345 58.968 ;
     RECT  75.809 60.384 76.345 61.128 ;
     RECT  76.021 66.384 76.348 69.288 ;
     RECT  76.061 42.048 76.349 47.496 ;
     RECT  75.788 22.896 76.453 26.232 ;
     RECT  76.259 27.696 76.453 32.28 ;
     RECT  76.025 54.096 76.453 55.8 ;
     RECT  76.345 57.024 76.453 61.128 ;
     RECT  76.349 42.288 76.457 47.496 ;
     RECT  76.241 48.48 76.493 48.504 ;
     RECT  76.277 3.312 76.637 21.72 ;
     RECT  76.313 74.112 76.637 74.952 ;
     RECT  76.453 22.896 76.817 32.28 ;
     RECT  76.457 42.288 76.853 47.352 ;
     RECT  75.521 62.736 76.921 64.344 ;
     RECT  76.817 22.896 76.993 28.968 ;
     RECT  76.133 71.424 76.993 73.032 ;
     RECT  76.453 54.096 77.033 61.128 ;
     RECT  76.348 68.208 77.065 69.288 ;
     RECT  76.348 66.384 77.173 67.032 ;
     RECT  76.637 3.312 77.245 12.792 ;
     RECT  76.817 30.048 77.353 32.28 ;
     RECT  76.259 33.552 77.353 40.824 ;
     RECT  77.065 68.208 77.353 69.384 ;
     RECT  77.353 30.048 77.389 40.824 ;
     RECT  76.853 42.288 77.389 42.312 ;
     RECT  76.241 49.488 77.389 53.064 ;
     RECT  77.033 54.096 77.389 58.68 ;
     RECT  76.853 43.344 77.425 47.352 ;
     RECT  77.389 49.488 77.425 58.68 ;
     RECT  76.921 62.736 77.425 64.44 ;
     RECT  77.173 65.904 77.425 67.032 ;
     RECT  77.353 68.208 77.496 70.344 ;
     RECT  76.993 71.376 77.496 73.032 ;
     RECT  77.425 43.344 77.497 48.216 ;
     RECT  77.033 59.712 77.497 61.128 ;
     RECT  77.425 62.736 77.497 67.032 ;
     RECT  77.245 3.216 77.653 12.792 ;
     RECT  76.637 14.064 77.653 21.72 ;
     RECT  77.497 43.344 77.893 48.264 ;
     RECT  76.993 22.8 77.929 28.968 ;
     RECT  77.389 30.048 77.929 42.312 ;
     RECT  77.653 3.216 78.008 21.72 ;
     RECT  77.929 22.8 78.008 42.312 ;
     RECT  77.893 43.296 78.008 48.264 ;
     RECT  77.425 49.296 78.008 58.68 ;
     RECT  77.497 59.712 78.008 67.032 ;
     RECT  77.496 68.208 78.008 73.032 ;
     RECT  76.637 74.112 78.008 74.616 ;
     RECT  78.008 2.148 78.112 75.612 ;
     RECT  78.112 2.418 78.304 75.342 ;
     RECT  78.304 6 78.329 12.792 ;
     RECT  78.304 42.72 78.437 54.744 ;
     RECT  78.304 41.136 78.473 41.736 ;
     RECT  78.437 42.72 78.545 54.648 ;
     RECT  78.304 55.728 78.545 64.104 ;
     RECT  78.304 24.624 78.581 39.528 ;
     RECT  78.329 6.048 78.617 12.792 ;
     RECT  78.545 55.728 78.617 63.768 ;
     RECT  78.304 3.888 78.653 4.776 ;
     RECT  78.304 14.112 78.653 23.352 ;
     RECT  78.617 6.048 78.689 9.288 ;
     RECT  78.617 57.024 78.689 63.768 ;
     RECT  78.653 4.272 78.725 4.776 ;
     RECT  78.304 72.48 78.725 73.032 ;
     RECT  78.725 4.272 78.761 4.68 ;
     RECT  78.617 55.728 78.761 55.992 ;
     RECT  78.581 27.936 78.797 39.528 ;
     RECT  78.545 42.72 78.977 54.408 ;
     RECT  78.689 57.024 79.013 63.576 ;
     RECT  78.977 42.72 79.049 53.64 ;
     RECT  78.304 74.592 79.121 74.616 ;
     RECT  78.304 67.872 79.139 69.384 ;
     RECT  78.797 37.584 79.193 39.528 ;
     RECT  78.304 65.52 79.193 66.792 ;
     RECT  79.139 68.976 79.193 69.384 ;
     RECT  79.049 42.72 79.283 49.176 ;
     RECT  78.653 14.112 79.301 22.248 ;
     RECT  78.617 10.704 79.333 12.792 ;
     RECT  79.301 14.112 79.333 22.2 ;
     RECT  78.797 27.936 79.337 36.456 ;
     RECT  78.689 9.072 79.409 9.288 ;
     RECT  79.337 30.576 79.445 36.456 ;
     RECT  79.049 50.352 79.445 53.64 ;
     RECT  78.473 41.136 79.549 41.64 ;
     RECT  79.193 66.528 79.549 66.792 ;
     RECT  79.549 66.528 79.553 66.84 ;
     RECT  79.283 42.72 79.589 45.144 ;
     RECT  79.013 57.024 79.621 63.432 ;
     RECT  79.589 42.72 79.625 43.848 ;
     RECT  79.333 10.704 79.661 22.2 ;
     RECT  79.283 46.176 79.661 48.744 ;
     RECT  79.621 56.736 79.667 63.432 ;
     RECT  79.625 42.72 79.733 43.752 ;
     RECT  78.581 24.624 79.801 26.76 ;
     RECT  79.337 27.936 79.801 29.352 ;
     RECT  78.689 6.048 79.804 7.992 ;
     RECT  79.409 9.264 79.837 9.288 ;
     RECT  79.661 10.704 79.837 20.376 ;
     RECT  78.761 4.272 79.841 4.296 ;
     RECT  79.804 6.048 79.841 6.072 ;
     RECT  79.667 57.84 79.859 63.432 ;
     RECT  78.653 23.328 79.877 23.352 ;
     RECT  79.193 37.632 79.913 39.528 ;
     RECT  79.553 66.576 79.945 66.84 ;
     RECT  79.193 69.36 79.945 69.384 ;
     RECT  79.445 32.448 79.985 36.456 ;
     RECT  79.549 41.04 80.051 41.64 ;
     RECT  79.445 50.352 80.053 51.192 ;
     RECT  80.051 41.136 80.057 41.64 ;
     RECT  79.859 61.728 80.093 63.432 ;
     RECT  79.945 69.36 80.125 69.48 ;
     RECT  79.801 24.624 80.165 29.352 ;
     RECT  79.837 9.264 80.201 20.376 ;
     RECT  80.057 41.136 80.201 41.16 ;
     RECT  78.725 72.48 80.204 72.984 ;
     RECT  80.165 24.624 80.233 28.776 ;
     RECT  80.053 50.304 80.269 51.192 ;
     RECT  80.204 72.48 80.291 73.464 ;
     RECT  79.661 21.36 80.341 22.2 ;
     RECT  79.985 32.928 80.341 36.456 ;
     RECT  78.761 55.728 80.345 55.752 ;
     RECT  79.945 66.576 80.377 67.656 ;
     RECT  79.661 48.72 80.381 48.744 ;
     RECT  79.804 7.632 80.413 7.992 ;
     RECT  80.201 9.264 80.413 15.48 ;
     RECT  80.341 21.36 80.417 22.248 ;
     RECT  79.913 37.632 80.417 38.712 ;
     RECT  80.291 72.48 80.417 72.984 ;
     RECT  80.341 3.984 80.453 4.008 ;
     RECT  80.201 16.56 80.453 20.376 ;
     RECT  80.269 50.016 80.485 51.192 ;
     RECT  79.445 52.176 80.485 53.64 ;
     RECT  80.377 66.576 80.485 68.376 ;
     RECT  80.125 69.36 80.485 70.056 ;
     RECT  80.413 7.632 80.497 15.48 ;
     RECT  80.417 38.688 80.597 38.712 ;
     RECT  79.445 30.576 80.629 31.368 ;
     RECT  80.341 32.928 80.629 36.648 ;
     RECT  80.417 37.632 80.629 37.656 ;
     RECT  79.661 46.176 80.633 47.592 ;
     RECT  80.417 72.48 80.633 72.888 ;
     RECT  79.193 65.52 80.636 65.544 ;
     RECT  80.485 66.576 80.636 70.056 ;
     RECT  80.557 71.232 80.641 71.256 ;
     RECT  80.485 50.016 80.665 53.64 ;
     RECT  79.693 54.624 80.665 54.648 ;
     RECT  80.633 46.176 80.669 46.632 ;
     RECT  79.667 56.736 80.737 56.76 ;
     RECT  80.629 30.24 80.741 31.368 ;
     RECT  80.629 32.928 80.741 37.656 ;
     RECT  80.233 23.904 80.771 28.776 ;
     RECT  80.497 7.632 80.809 7.992 ;
     RECT  80.497 9.216 80.813 15.48 ;
     RECT  79.859 57.84 80.821 60.168 ;
     RECT  80.093 61.728 80.821 63.336 ;
     RECT  80.453 19.296 80.845 20.376 ;
     RECT  79.589 45.12 80.845 45.144 ;
     RECT  80.669 46.176 80.845 46.584 ;
     RECT  80.633 72.48 80.849 72.744 ;
     RECT  80.665 50.016 80.869 54.648 ;
     RECT  80.737 55.872 80.915 56.76 ;
     RECT  80.636 65.52 80.917 70.056 ;
     RECT  80.821 57.84 80.957 63.336 ;
     RECT  80.957 57.84 80.963 63.096 ;
     RECT  80.741 32.928 80.972 36.264 ;
     RECT  80.809 6.864 80.993 7.992 ;
     RECT  80.813 9.264 80.993 15.48 ;
     RECT  80.963 61.776 80.993 63.096 ;
     RECT  80.417 22.224 81.025 22.248 ;
     RECT  80.845 19.296 81.059 20.856 ;
     RECT  80.972 32.448 81.059 36.264 ;
     RECT  80.869 50.016 81.065 54.888 ;
     RECT  80.915 56.736 81.065 56.76 ;
     RECT  80.917 65.52 81.065 70.152 ;
     RECT  80.849 72.72 81.065 72.744 ;
     RECT  80.993 6.864 81.097 7.8 ;
     RECT  80.963 57.84 81.101 60.36 ;
     RECT  81.065 65.52 81.101 69.144 ;
     RECT  81.101 57.84 81.107 59.256 ;
     RECT  81.107 57.84 81.133 59.112 ;
     RECT  80.341 5.136 81.137 5.16 ;
     RECT  80.741 30.24 81.137 30.84 ;
     RECT  81.133 41.472 81.205 41.496 ;
     RECT  79.733 42.72 81.205 43.56 ;
     RECT  80.993 10.704 81.209 15.48 ;
     RECT  81.059 19.344 81.281 20.856 ;
     RECT  80.771 23.904 81.281 26.184 ;
     RECT  81.277 38.736 81.349 38.76 ;
     RECT  80.665 39.744 81.349 39.816 ;
     RECT  81.209 14.784 81.353 15.48 ;
     RECT  81.097 6.288 81.381 7.8 ;
     RECT  81.349 38.736 81.389 39.816 ;
     RECT  81.133 57.024 81.389 59.112 ;
     RECT  81.065 70.128 81.421 70.152 ;
     RECT  81.421 70.128 81.425 70.68 ;
     RECT  80.809 47.952 81.457 48.264 ;
     RECT  80.453 16.56 81.493 18.168 ;
     RECT  80.771 27.456 81.493 28.776 ;
     RECT  81.205 30.144 81.493 30.168 ;
     RECT  81.065 50.016 81.497 53.592 ;
     RECT  81.025 22.224 81.529 22.776 ;
     RECT  81.353 14.784 81.533 14.904 ;
     RECT  81.281 24.96 81.533 26.184 ;
     RECT  81.389 57.024 81.533 58.92 ;
     RECT  81.493 27.456 81.539 30.168 ;
     RECT  81.209 10.704 81.569 13.656 ;
     RECT  81.539 27.984 81.605 30.168 ;
     RECT  81.533 58.8 81.605 58.92 ;
     RECT  80.845 45.12 81.637 46.584 ;
     RECT  81.101 65.52 81.637 66.648 ;
     RECT  80.993 9.264 81.641 9.384 ;
     RECT  81.065 54.864 81.641 54.888 ;
     RECT  81.381 6.288 81.677 6.888 ;
     RECT  81.281 23.904 81.677 23.976 ;
     RECT  81.637 64.752 81.683 66.648 ;
     RECT  81.683 64.752 81.705 65.544 ;
     RECT  81.529 22.176 81.709 22.776 ;
     RECT  81.533 25.2 81.713 26.184 ;
     RECT  81.605 58.896 81.713 58.92 ;
     RECT  81.101 67.776 81.713 69.144 ;
     RECT  81.457 40.464 81.781 40.488 ;
     RECT  81.205 41.472 81.781 43.56 ;
     RECT  81.605 29.664 81.785 30.168 ;
     RECT  81.059 32.928 81.785 36.264 ;
     RECT  81.683 66.624 81.785 66.648 ;
     RECT  81.637 44.784 81.817 46.584 ;
     RECT  81.497 51.84 81.821 53.592 ;
     RECT  81.457 47.952 81.853 48.936 ;
     RECT  81.817 44.784 81.923 46.68 ;
     RECT  81.709 21.84 81.929 23.4 ;
     RECT  81.785 32.928 81.929 33.816 ;
     RECT  81.923 44.784 81.929 46.584 ;
     RECT  81.641 9.312 81.961 9.384 ;
     RECT  81.569 10.704 81.961 13.32 ;
     RECT  81.281 19.584 81.961 20.856 ;
     RECT  81.929 21.84 81.961 22.248 ;
     RECT  81.493 16.56 81.965 18.216 ;
     RECT  81.781 40.464 82.037 43.56 ;
     RECT  81.425 70.56 82.037 70.68 ;
     RECT  81.713 67.776 82.105 69 ;
     RECT  81.965 17.664 82.109 18.216 ;
     RECT  81.929 32.928 82.109 33.672 ;
     RECT  80.741 37.248 82.109 37.656 ;
     RECT  81.533 57.024 82.109 57.576 ;
     RECT  81.785 35.088 82.115 36.264 ;
     RECT  81.965 16.56 82.141 16.632 ;
     RECT  82.141 16.512 82.145 16.632 ;
     RECT  81.533 14.832 82.181 14.904 ;
     RECT  82.145 16.512 82.253 16.584 ;
     RECT  82.109 17.664 82.253 18.024 ;
     RECT  81.705 64.752 82.253 64.776 ;
     RECT  81.785 30.144 82.289 30.168 ;
     RECT  81.853 47.904 82.321 48.936 ;
     RECT  82.037 40.464 82.361 42.024 ;
     RECT  82.037 70.656 82.361 70.68 ;
     RECT  82.109 32.928 82.397 33.624 ;
     RECT  82.321 47.712 82.429 48.936 ;
     RECT  81.605 27.984 82.501 28.68 ;
     RECT  82.037 43.488 82.501 43.56 ;
     RECT  81.929 44.784 82.501 44.808 ;
     RECT  80.993 61.776 82.537 63.048 ;
     RECT  82.537 61.776 82.549 63.288 ;
     RECT  81.389 38.736 82.609 39.48 ;
     RECT  82.361 40.464 82.609 40.872 ;
     RECT  82.429 8.304 82.645 8.328 ;
     RECT  81.961 9.312 82.645 13.32 ;
     RECT  81.821 52.368 82.645 53.592 ;
     RECT  82.549 61.488 82.717 63.288 ;
     RECT  82.645 52.368 82.753 53.976 ;
     RECT  82.609 38.736 82.825 40.872 ;
     RECT  81.713 25.2 82.837 25.56 ;
     RECT  82.429 47.712 82.885 48.984 ;
     RECT  81.497 50.016 82.885 50.808 ;
     RECT  82.753 52.368 82.885 54.696 ;
     RECT  81.961 19.584 82.897 22.248 ;
     RECT  81.889 31.152 82.94 31.272 ;
     RECT  81.929 46.128 83.041 46.584 ;
     RECT  82.885 47.712 83.041 50.808 ;
     RECT  81.929 23.376 83.269 23.4 ;
     RECT  81.677 6.288 83.408 6.312 ;
     RECT  82.645 8.304 83.408 13.32 ;
     RECT  82.181 14.88 83.408 14.904 ;
     RECT  82.253 16.512 83.408 16.536 ;
     RECT  82.253 17.904 83.408 18.024 ;
     RECT  82.897 19.584 83.408 22.296 ;
     RECT  83.269 23.376 83.408 23.544 ;
     RECT  82.837 24.624 83.408 25.56 ;
     RECT  82.321 26.736 83.408 26.76 ;
     RECT  82.501 27.936 83.408 28.68 ;
     RECT  82.94 31.152 83.408 32.184 ;
     RECT  82.397 33.6 83.408 33.624 ;
     RECT  82.115 36.048 83.408 36.264 ;
     RECT  82.109 37.248 83.408 37.608 ;
     RECT  82.825 38.688 83.408 40.872 ;
     RECT  82.361 42 83.408 42.024 ;
     RECT  82.501 43.488 83.408 44.808 ;
     RECT  83.041 46.128 83.408 50.808 ;
     RECT  82.885 52.176 83.408 54.696 ;
     RECT  82.109 57.024 83.408 57.048 ;
     RECT  81.101 60.336 83.408 60.36 ;
     RECT  82.717 61.488 83.408 64.152 ;
     RECT  82.105 67.392 83.408 69 ;
     RECT  83.408 2.148 83.512 75.612 ;
     RECT  83.512 2.418 83.704 75.342 ;
     RECT  83.704 28.416 83.801 28.44 ;
    LAYER M5 ;
     RECT  51.408 0.016 51.912 0.131 ;
     RECT  70.608 0.016 73.608 0.563 ;
     RECT  9.936 0.016 16.008 0.611 ;
     RECT  42.192 0.016 45.192 0.611 ;
     RECT  70.8 0.563 73.608 0.611 ;
     RECT  10.032 0.611 16.008 0.659 ;
     RECT  10.416 0.659 16.008 1.763 ;
     RECT  71.088 0.611 73.608 1.763 ;
     RECT  10.704 1.763 16.008 1.811 ;
     RECT  42.192 0.611 45.096 1.811 ;
     RECT  10.704 1.811 15.816 1.859 ;
     RECT  42.192 1.811 42.6 1.859 ;
     RECT  43.632 1.811 45.096 1.859 ;
     RECT  71.28 1.763 73.224 1.859 ;
     RECT  11.184 1.859 15.816 1.907 ;
     RECT  51.408 0.131 51.816 1.907 ;
     RECT  51.408 1.907 51.432 2.137 ;
     RECT  2.4 2.137 2.52 2.151 ;
     RECT  7.8 2.137 7.92 2.151 ;
     RECT  18.6 2.137 18.72 2.151 ;
     RECT  24 2.137 24.12 2.151 ;
     RECT  29.4 2.137 29.52 2.151 ;
     RECT  34.8 2.137 34.92 2.151 ;
     RECT  40.2 2.137 40.32 2.151 ;
     RECT  45.6 2.137 45.72 2.151 ;
     RECT  56.4 2.137 56.52 2.151 ;
     RECT  67.2 2.137 67.32 2.151 ;
     RECT  78 2.137 78.12 2.151 ;
     RECT  83.4 2.137 83.52 2.151 ;
     RECT  58.32 0.016 64.392 2.197 ;
     RECT  7.8 2.151 8.112 2.245 ;
     RECT  40.2 2.151 40.512 2.245 ;
     RECT  51 2.137 51.432 2.245 ;
     RECT  67.2 2.151 67.512 2.245 ;
     RECT  11.184 1.907 15.336 2.291 ;
     RECT  42.192 1.859 42.216 2.339 ;
     RECT  67.2 2.245 68.28 2.485 ;
     RECT  50.544 2.245 51.432 2.677 ;
     RECT  24 2.151 24.312 2.725 ;
     RECT  40.2 2.245 40.824 2.821 ;
     RECT  43.728 1.859 44.136 2.821 ;
     RECT  66.24 2.485 68.28 2.821 ;
     RECT  58.32 2.197 64.488 2.869 ;
     RECT  65.52 2.821 68.28 3.059 ;
     RECT  56.4 2.151 56.712 3.205 ;
     RECT  58.224 2.869 64.488 3.253 ;
     RECT  78 2.151 78.312 3.253 ;
     RECT  7.296 2.245 8.112 3.299 ;
     RECT  74.304 2.821 74.328 3.301 ;
     RECT  75.696 3.061 75.72 3.301 ;
     RECT  36.864 2.245 36.888 3.347 ;
     RECT  2.4 2.151 2.712 3.349 ;
     RECT  52.8 2.629 52.824 3.349 ;
     RECT  56.4 3.205 57 3.349 ;
     RECT  58.128 3.253 64.488 3.349 ;
     RECT  65.52 3.059 67.608 3.349 ;
     RECT  71.28 1.859 72.912 3.349 ;
     RECT  47.28 2.821 47.304 3.397 ;
     RECT  49.968 2.677 51.432 3.397 ;
     RECT  52.8 3.349 53.448 3.397 ;
     RECT  45.6 2.151 45.912 3.445 ;
     RECT  18.6 2.151 18.912 3.541 ;
     RECT  54.432 2.821 54.456 3.541 ;
     RECT  77.904 3.253 78.312 3.541 ;
     RECT  54.432 3.541 54.696 3.587 ;
     RECT  74.304 3.301 75.72 3.685 ;
     RECT  77.664 3.541 78.312 3.685 ;
     RECT  49.968 3.397 53.448 3.875 ;
     RECT  45.6 3.445 46.152 3.923 ;
     RECT  34.8 2.151 35.112 3.925 ;
     RECT  47.28 3.397 47.832 3.925 ;
     RECT  55.68 3.349 57 3.925 ;
     RECT  58.128 3.349 67.608 3.925 ;
     RECT  40.2 2.821 41.496 4.115 ;
     RECT  50.208 3.875 53.448 4.115 ;
     RECT  17.712 3.541 18.912 4.117 ;
     RECT  43.728 2.821 44.568 4.117 ;
     RECT  45.6 3.923 45.912 4.117 ;
     RECT  54.672 3.587 54.696 4.259 ;
     RECT  55.68 3.925 67.608 4.261 ;
     RECT  11.376 2.291 15.336 4.309 ;
     RECT  17.136 4.117 18.912 4.403 ;
     RECT  55.344 4.261 67.608 4.453 ;
     RECT  24 2.725 25.128 4.501 ;
     RECT  74.304 3.685 78.312 4.547 ;
     RECT  43.728 4.117 45.912 4.595 ;
     RECT  31.872 2.245 31.896 4.643 ;
     RECT  34.8 3.925 35.928 4.643 ;
     RECT  11.136 4.309 15.336 4.645 ;
     RECT  23.472 4.501 25.128 4.645 ;
     RECT  23.472 4.645 25.608 4.691 ;
     RECT  9.12 4.501 9.144 4.693 ;
     RECT  10.896 4.645 15.336 4.789 ;
     RECT  16.32 4.501 16.344 4.789 ;
     RECT  29.4 2.151 29.712 4.837 ;
     RECT  29.232 4.837 29.712 4.933 ;
     RECT  44.544 4.595 45.912 4.981 ;
     RECT  47.232 3.925 47.832 4.981 ;
     RECT  71.088 3.349 72.912 5.029 ;
     RECT  74.304 4.547 76.584 5.029 ;
     RECT  2.4 3.349 2.856 5.125 ;
     RECT  52.464 4.115 53.448 5.125 ;
     RECT  55.344 4.453 68.04 5.125 ;
     RECT  55.344 5.125 68.952 5.173 ;
     RECT  44.544 4.981 47.832 5.219 ;
     RECT  52.416 5.125 53.448 5.219 ;
     RECT  36.384 5.269 36.408 5.411 ;
     RECT  19.968 2.773 19.992 5.459 ;
     RECT  10.896 4.789 16.344 5.461 ;
     RECT  17.712 4.403 18.912 5.461 ;
     RECT  38.16 5.029 38.184 5.509 ;
     RECT  29.088 4.933 29.712 5.557 ;
     RECT  9.12 4.693 9.576 5.603 ;
     RECT  10.896 5.461 19.224 5.603 ;
     RECT  21.12 4.261 21.144 5.701 ;
     RECT  23.472 4.691 24.312 5.747 ;
     RECT  55.344 5.173 69.144 5.747 ;
     RECT  69.12 5.747 69.144 5.797 ;
     RECT  55.344 5.747 68.04 5.843 ;
     RECT  20.976 5.701 21.144 5.891 ;
     RECT  29.04 5.557 29.712 5.893 ;
     RECT  71.088 5.029 76.584 5.893 ;
     RECT  10.896 5.603 18.912 5.939 ;
     RECT  70.848 5.893 76.584 6.181 ;
     RECT  77.664 4.547 78.312 6.181 ;
     RECT  23.712 5.747 24.312 6.277 ;
     RECT  25.584 4.691 25.608 6.277 ;
     RECT  22.464 5.413 22.488 6.323 ;
     RECT  37.2 5.509 38.184 6.323 ;
     RECT  70.848 6.181 78.312 6.419 ;
     RECT  21.072 5.891 21.144 6.421 ;
     RECT  45.456 5.219 47.304 6.467 ;
     RECT  2.4 5.125 3.672 6.515 ;
     RECT  42.624 5.269 42.648 6.517 ;
     RECT  69.12 5.797 69.336 6.517 ;
     RECT  70.848 6.419 74.952 6.517 ;
     RECT  33.216 6.325 33.24 6.659 ;
     RECT  55.68 5.843 68.04 6.757 ;
     RECT  69.12 6.517 74.952 6.757 ;
     RECT  50.208 4.115 51.312 6.805 ;
     RECT  52.416 5.219 53.256 6.805 ;
     RECT  45.456 6.467 47.256 6.851 ;
     RECT  21.072 6.421 21.864 6.853 ;
     RECT  55.68 6.757 74.952 6.899 ;
     RECT  2.4 6.515 3.528 7.283 ;
     RECT  11.424 5.939 18.912 7.331 ;
     RECT  21.024 6.853 21.864 7.333 ;
     RECT  50.208 6.805 53.256 7.379 ;
     RECT  29.04 5.893 30.552 7.381 ;
     RECT  42.192 6.517 42.648 7.381 ;
     RECT  52.464 7.379 53.256 7.381 ;
     RECT  29.04 7.381 31.08 7.427 ;
     RECT  9.12 5.603 9.432 7.619 ;
     RECT  42.192 7.381 42.84 7.619 ;
     RECT  7.8 3.299 8.112 7.669 ;
     RECT  79.728 6.805 79.752 7.763 ;
     RECT  81.312 6.805 81.336 7.811 ;
     RECT  52.464 7.381 54.168 7.861 ;
     RECT  52.464 7.861 54.6 7.909 ;
     RECT  45.456 6.851 45.912 7.955 ;
     RECT  34.8 4.643 35.304 7.957 ;
     RECT  45.504 7.955 45.912 7.957 ;
     RECT  12 7.331 18.912 8.003 ;
     RECT  69.312 6.899 74.328 8.051 ;
     RECT  5.808 3.877 5.832 8.053 ;
     RECT  9.408 7.619 9.432 8.101 ;
     RECT  76.272 6.419 78.312 8.147 ;
     RECT  9.408 8.101 9.768 8.243 ;
     RECT  55.68 6.899 68.04 8.291 ;
     RECT  20.88 7.333 21.864 8.293 ;
     RECT  77.664 8.147 78.312 8.293 ;
     RECT  5.76 8.053 5.832 8.339 ;
     RECT  40.2 4.115 40.728 8.435 ;
     RECT  29.04 7.427 30.024 8.485 ;
     RECT  49.152 7.429 49.176 8.485 ;
     RECT  50.208 7.379 51.312 8.485 ;
     RECT  52.464 7.909 54.696 8.579 ;
     RECT  54.576 8.579 54.696 8.627 ;
     RECT  54.576 8.627 54.6 8.723 ;
     RECT  12.48 8.003 18.912 8.725 ;
     RECT  37.2 6.323 37.224 8.725 ;
     RECT  36.912 8.725 37.224 8.773 ;
     RECT  70.848 8.051 74.328 8.821 ;
     RECT  83.4 2.151 83.712 8.821 ;
     RECT  12.48 8.725 19.848 8.867 ;
     RECT  45.504 7.957 46.008 8.869 ;
     RECT  52.464 8.579 53.256 8.869 ;
     RECT  45.504 8.869 46.2 8.917 ;
     RECT  70.848 8.821 74.664 8.963 ;
     RECT  23.712 6.277 25.608 9.013 ;
     RECT  44.976 8.917 46.2 9.061 ;
     RECT  12.48 8.867 18.912 9.109 ;
     RECT  67.2 8.291 68.04 9.109 ;
     RECT  69.312 8.051 69.576 9.203 ;
     RECT  10.656 9.109 10.68 9.205 ;
     RECT  12.384 9.109 18.912 9.251 ;
     RECT  23.712 9.013 25.944 9.251 ;
     RECT  29.04 8.485 30.072 9.253 ;
     RECT  31.056 7.427 31.08 9.253 ;
     RECT  44.208 9.061 46.248 9.253 ;
     RECT  20.88 8.293 22.056 9.395 ;
     RECT  29.04 9.253 31.08 9.395 ;
     RECT  21.84 9.395 22.056 9.445 ;
     RECT  48.528 8.485 51.312 9.539 ;
     RECT  80.448 7.957 80.664 9.539 ;
     RECT  70.848 8.963 74.328 9.541 ;
     RECT  55.68 8.291 66.12 9.589 ;
     RECT  67.2 9.109 68.136 9.589 ;
     RECT  55.68 9.589 68.136 9.637 ;
     RECT  69.312 9.203 69.336 9.637 ;
     RECT  2.4 7.283 3.48 9.685 ;
     RECT  4.608 8.293 4.632 9.685 ;
     RECT  5.808 8.339 5.832 9.685 ;
     RECT  44.208 9.253 46.728 9.731 ;
     RECT  10.656 9.205 10.776 9.733 ;
     RECT  44.64 9.731 46.728 9.779 ;
     RECT  2.4 9.685 5.832 9.875 ;
     RECT  49.344 9.539 51.312 9.875 ;
     RECT  34.08 7.957 35.304 9.925 ;
     RECT  36.912 8.773 37.8 9.925 ;
     RECT  34.08 9.925 37.8 9.971 ;
     RECT  52.416 8.869 53.256 9.971 ;
     RECT  38.784 7.957 38.808 10.117 ;
     RECT  40.2 8.435 40.512 10.117 ;
     RECT  2.4 9.875 4.632 10.307 ;
     RECT  38.784 10.117 40.512 10.307 ;
     RECT  23.712 9.251 25.464 10.309 ;
     RECT  29.04 9.395 29.712 10.309 ;
     RECT  12.48 9.251 18.912 10.357 ;
     RECT  9.408 8.243 9.432 10.405 ;
     RECT  10.656 9.733 11.448 10.405 ;
     RECT  55.68 9.637 69.336 10.451 ;
     RECT  80.64 9.539 80.664 10.453 ;
     RECT  55.68 10.451 65.784 10.499 ;
     RECT  26.496 9.541 26.52 10.643 ;
     RECT  21.84 9.445 22.488 10.739 ;
     RECT  31.056 9.395 31.08 10.741 ;
     RECT  46.896 10.021 46.92 10.741 ;
     RECT  46.896 10.741 47.256 10.787 ;
     RECT  67.2 10.451 69.336 10.835 ;
     RECT  31.056 10.741 31.32 10.883 ;
     RECT  34.08 9.971 35.976 10.883 ;
     RECT  47.232 10.787 47.256 10.883 ;
     RECT  70.8 9.541 74.328 10.885 ;
     RECT  77.664 8.293 78.504 11.027 ;
     RECT  70.656 10.885 74.328 11.075 ;
     RECT  44.64 9.779 45.912 11.077 ;
     RECT  23.712 10.309 25.512 11.123 ;
     RECT  39.264 10.307 40.512 11.171 ;
     RECT  49.584 9.875 51.312 11.219 ;
     RECT  12.48 10.357 19.032 11.365 ;
     RECT  28.512 10.309 29.712 11.411 ;
     RECT  7.632 7.669 8.112 11.413 ;
     RECT  31.296 10.883 31.32 11.459 ;
     RECT  37.2 9.971 37.8 11.557 ;
     RECT  76.272 8.147 76.296 11.653 ;
     RECT  77.664 11.027 78.408 11.653 ;
     RECT  42.624 7.619 42.84 11.797 ;
     RECT  82.656 8.821 83.712 11.797 ;
     RECT  9.408 10.405 11.448 11.845 ;
     RECT  9.408 11.845 11.496 11.941 ;
     RECT  12.48 11.365 19.368 11.941 ;
     RECT  44.64 11.077 46.008 11.941 ;
     RECT  80.64 10.453 80.712 11.987 ;
     RECT  27.504 11.365 27.528 12.035 ;
     RECT  61.8 10.499 65.784 12.277 ;
     RECT  67.2 10.835 68.136 12.277 ;
     RECT  9.408 11.941 19.368 12.419 ;
     RECT  6.816 11.413 8.112 12.469 ;
     RECT  40.2 11.171 40.512 12.517 ;
     RECT  50.208 11.219 51.312 12.517 ;
     RECT  9.408 12.419 17.4 12.613 ;
     RECT  76.272 11.653 78.408 12.755 ;
     RECT  34.08 10.883 35.88 12.757 ;
     RECT  37.2 11.557 38.856 12.757 ;
     RECT  55.68 10.499 60.792 12.757 ;
     RECT  61.8 12.277 68.136 12.757 ;
     RECT  34.08 12.757 38.856 12.803 ;
     RECT  2.4 10.307 3.48 12.949 ;
     RECT  9.216 12.613 17.4 12.995 ;
     RECT  18.6 12.419 19.368 12.997 ;
     RECT  69.408 11.365 69.432 12.997 ;
     RECT  9.36 12.995 17.4 13.043 ;
     RECT  70.8 11.075 74.328 13.043 ;
     RECT  23.712 11.123 25.416 13.045 ;
     RECT  10.848 13.043 17.4 13.091 ;
     RECT  55.68 12.757 68.136 13.093 ;
     RECT  2.304 12.949 3.48 13.139 ;
     RECT  40.08 12.517 40.512 13.139 ;
     RECT  69.408 12.997 69.816 13.139 ;
     RECT  6.816 12.469 8.232 13.189 ;
     RECT  49.584 12.517 51.312 13.283 ;
     RECT  77.664 12.755 78.408 13.283 ;
     RECT  82.608 11.797 83.712 13.331 ;
     RECT  70.848 13.043 74.328 13.333 ;
     RECT  6.816 13.189 8.376 13.427 ;
     RECT  18.6 12.997 19.56 13.427 ;
     RECT  10.848 13.091 14.856 13.475 ;
     RECT  52.464 9.971 53.256 13.477 ;
     RECT  54.528 13.333 54.552 13.477 ;
     RECT  32.448 13.333 32.472 13.523 ;
     RECT  10.848 13.475 14.568 13.571 ;
     RECT  36.576 12.803 38.856 13.571 ;
     RECT  43.968 11.941 46.008 13.619 ;
     RECT  80.64 11.987 80.664 13.621 ;
     RECT  44.64 13.619 46.008 13.715 ;
     RECT  69.792 13.139 69.816 13.715 ;
     RECT  42.576 11.797 42.84 14.101 ;
     RECT  36.72 13.571 38.856 14.147 ;
     RECT  70.848 13.333 74.664 14.243 ;
     RECT  18.6 13.427 19.176 14.245 ;
     RECT  80.352 13.621 80.664 14.245 ;
     RECT  36.72 14.147 38.232 14.291 ;
     RECT  80.064 14.245 80.664 14.387 ;
     RECT  55.68 13.093 68.376 14.435 ;
     RECT  77.904 13.283 78.408 14.483 ;
     RECT  5.808 9.875 5.832 14.627 ;
     RECT  60.768 14.435 68.376 14.627 ;
     RECT  6.816 13.427 8.232 14.675 ;
     RECT  15.984 13.091 17.4 14.725 ;
     RECT  47.808 14.101 47.832 14.725 ;
     RECT  70.848 14.243 74.328 14.773 ;
     RECT  11.472 13.571 14.568 14.819 ;
     RECT  37.2 14.291 38.232 14.867 ;
     RECT  21.84 10.739 22.056 14.869 ;
     RECT  23.04 13.045 25.416 14.869 ;
     RECT  21.84 14.869 25.416 14.915 ;
     RECT  41.616 14.101 42.84 14.963 ;
     RECT  32.64 14.869 32.664 15.011 ;
     RECT  29.04 11.411 29.712 15.013 ;
     RECT  31.2 14.821 31.224 15.059 ;
     RECT  2.4 13.139 3.48 15.061 ;
     RECT  4.608 10.307 4.632 15.061 ;
     RECT  40.2 13.139 40.512 15.061 ;
     RECT  18.48 14.245 19.176 15.299 ;
     RECT  80.352 14.387 80.664 15.395 ;
     RECT  47.808 14.725 48.12 15.443 ;
     RECT  18.6 15.299 19.176 15.491 ;
     RECT  37.2 14.867 37.8 15.491 ;
     RECT  30.96 15.349 30.984 15.539 ;
     RECT  32.448 15.445 32.472 15.589 ;
     RECT  60.768 14.627 68.136 15.637 ;
     RECT  70.128 14.773 74.328 15.683 ;
     RECT  60.768 15.637 68.712 15.779 ;
     RECT  29.04 15.013 29.832 15.829 ;
     RECT  71.088 15.683 74.328 15.877 ;
     RECT  29.04 15.829 30.744 15.971 ;
     RECT  52.464 13.477 54.552 16.019 ;
     RECT  50.208 13.283 51.312 16.021 ;
     RECT  52.464 16.019 53.784 16.021 ;
     RECT  50.208 16.021 53.784 16.163 ;
     RECT  20.304 15.445 20.328 16.259 ;
     RECT  32.256 15.589 32.472 16.259 ;
     RECT  61.8 15.779 68.712 16.307 ;
     RECT  11.712 14.819 14.568 16.309 ;
     RECT  15.936 14.725 17.4 16.309 ;
     RECT  11.712 16.309 17.4 16.357 ;
     RECT  18.6 15.491 19.032 16.357 ;
     RECT  9.408 13.043 9.768 16.405 ;
     RECT  29.04 15.971 29.832 16.405 ;
     RECT  6.816 14.675 8.112 16.453 ;
     RECT  6.288 16.453 8.112 16.499 ;
     RECT  34.08 12.803 35.112 16.549 ;
     RECT  36.096 15.445 36.12 16.549 ;
     RECT  39.36 15.061 40.512 16.595 ;
     RECT  61.8 16.307 68.184 16.595 ;
     RECT  22.032 14.915 25.416 16.789 ;
     RECT  11.712 16.357 19.032 16.883 ;
     RECT  7.584 16.499 8.112 16.885 ;
     RECT  37.584 15.491 37.8 16.933 ;
     RECT  55.68 14.435 59.016 16.981 ;
     RECT  21.168 16.789 25.416 17.027 ;
     RECT  60.768 15.779 60.792 17.029 ;
     RECT  61.8 16.595 65.784 17.029 ;
     RECT  71.088 15.877 74.664 17.029 ;
     RECT  15.84 16.883 19.032 17.077 ;
     RECT  20.112 16.549 20.136 17.077 ;
     RECT  22.032 17.027 25.416 17.077 ;
     RECT  54.864 16.981 59.016 17.077 ;
     RECT  27.12 17.077 27.432 17.125 ;
     RECT  28.992 16.405 29.832 17.125 ;
     RECT  50.208 16.163 51.432 17.125 ;
     RECT  52.464 16.163 53.784 17.125 ;
     RECT  34.08 16.549 36.12 17.171 ;
     RECT  15.84 17.077 20.136 17.219 ;
     RECT  66.96 16.595 68.184 17.219 ;
     RECT  76.272 12.755 76.296 17.221 ;
     RECT  78 14.483 78.408 17.221 ;
     RECT  41.616 14.963 41.64 17.269 ;
     RECT  27.12 17.125 29.832 17.315 ;
     RECT  41.616 17.269 41.832 17.315 ;
     RECT  6.288 16.499 6.312 17.363 ;
     RECT  27.552 17.315 29.832 17.363 ;
     RECT  22.032 17.077 25.896 17.459 ;
     RECT  27.552 17.363 27.912 17.459 ;
     RECT  54.864 17.077 59.544 17.555 ;
     RECT  11.712 16.883 14.568 17.603 ;
     RECT  18.6 17.219 20.136 17.603 ;
     RECT  32.256 16.259 32.28 17.605 ;
     RECT  54.864 17.555 59.016 17.651 ;
     RECT  71.088 17.029 75.24 17.651 ;
     RECT  81.792 16.549 81.816 17.651 ;
     RECT  36.096 17.171 36.12 17.653 ;
     RECT  37.536 16.933 37.8 17.653 ;
     RECT  76.272 17.221 78.408 17.653 ;
     RECT  79.632 15.589 79.656 17.653 ;
     RECT  27.552 17.459 27.576 17.699 ;
     RECT  29.04 17.363 29.832 17.699 ;
     RECT  22.08 17.459 25.896 17.795 ;
     RECT  50.208 17.125 53.784 17.891 ;
     RECT  36.096 17.653 37.8 17.987 ;
     RECT  9.408 16.405 9.816 17.989 ;
     RECT  60.768 17.029 65.784 18.133 ;
     RECT  66.96 17.219 68.136 18.133 ;
     RECT  80.64 15.395 80.664 18.133 ;
     RECT  60.768 18.133 68.136 18.179 ;
     RECT  9.408 17.989 10.248 18.275 ;
     RECT  29.4 17.699 29.832 18.275 ;
     RECT  36.096 17.987 36.12 18.275 ;
     RECT  7.584 16.885 8.232 18.371 ;
     RECT  22.8 17.795 25.896 18.371 ;
     RECT  7.8 18.371 8.232 18.419 ;
     RECT  15.936 17.219 17.4 18.565 ;
     RECT  47.808 15.443 47.832 18.661 ;
     RECT  69.648 17.029 69.672 18.707 ;
     RECT  47.472 18.661 47.832 18.757 ;
     RECT  34.08 17.171 35.112 18.805 ;
     RECT  13.056 17.603 14.568 18.851 ;
     RECT  61.8 18.179 68.136 18.899 ;
     RECT  44.928 13.715 46.008 18.901 ;
     RECT  15.936 18.565 17.496 18.949 ;
     RECT  22.8 18.371 25.416 18.995 ;
     RECT  76.272 17.653 79.656 18.995 ;
     RECT  9.408 18.275 9.432 19.043 ;
     RECT  15.792 18.949 17.496 19.091 ;
     RECT  71.088 17.651 74.952 19.235 ;
     RECT  26.448 18.709 26.472 19.333 ;
     RECT  47.472 18.757 47.88 19.381 ;
     RECT  20.112 17.603 20.136 19.427 ;
     RECT  44.928 18.901 46.056 19.427 ;
     RECT  47.328 19.381 47.88 19.427 ;
     RECT  80.64 18.133 81.048 19.427 ;
     RECT  31.824 17.605 32.28 19.523 ;
     RECT  79.632 18.995 79.656 19.523 ;
     RECT  40.2 16.595 40.512 19.525 ;
     RECT  71.088 19.235 74.904 19.763 ;
     RECT  41.808 17.315 41.832 19.859 ;
     RECT  7.8 18.419 8.112 19.909 ;
     RECT  13.104 18.851 14.568 19.957 ;
     RECT  42.816 14.963 42.84 20.003 ;
     RECT  43.872 18.181 43.896 20.051 ;
     RECT  67.2 18.899 68.136 20.101 ;
     RECT  12.768 19.957 14.568 20.149 ;
     RECT  34.08 18.805 35.208 20.197 ;
     RECT  47.328 19.427 47.496 20.291 ;
     RECT  16.176 19.091 17.496 20.341 ;
     RECT  18.6 17.603 18.912 20.341 ;
     RECT  29.4 18.275 29.712 20.341 ;
     RECT  11.712 17.603 11.736 20.485 ;
     RECT  12.72 20.149 14.568 20.485 ;
     RECT  52.464 17.891 53.784 20.485 ;
     RECT  77.664 18.995 78.504 20.485 ;
     RECT  16.176 20.341 18.912 20.533 ;
     RECT  80.88 19.427 81.048 20.579 ;
     RECT  81.024 20.579 81.048 20.627 ;
     RECT  33.264 20.197 35.208 20.677 ;
     RECT  15.552 20.533 18.912 20.723 ;
     RECT  29.4 20.341 29.832 20.821 ;
     RECT  49.2 19.909 49.224 20.963 ;
     RECT  61.8 18.899 65.784 20.963 ;
     RECT  39.936 19.525 40.512 20.965 ;
     RECT  44.928 19.427 45.912 20.965 ;
     RECT  11.712 20.485 14.568 21.013 ;
     RECT  15.552 20.723 17.496 21.013 ;
     RECT  7.632 19.909 8.112 21.061 ;
     RECT  22.944 18.995 25.416 21.061 ;
     RECT  26.4 19.333 26.472 21.061 ;
     RECT  50.208 17.891 51.312 21.061 ;
     RECT  52.464 20.485 53.976 21.061 ;
     RECT  18.6 20.723 18.912 21.109 ;
     RECT  37.776 17.987 37.8 21.109 ;
     RECT  11.712 21.013 17.496 21.155 ;
     RECT  37.776 21.109 37.896 21.155 ;
     RECT  7.632 21.061 8.232 21.203 ;
     RECT  71.088 19.763 74.328 21.203 ;
     RECT  67.2 20.101 68.376 21.205 ;
     RECT  29.4 20.821 30.6 21.347 ;
     RECT  32.256 19.523 32.28 21.349 ;
     RECT  33.264 20.677 35.352 21.349 ;
     RECT  77.376 20.485 78.504 21.395 ;
     RECT  61.8 20.963 64.488 21.443 ;
     RECT  32.256 21.349 35.352 21.491 ;
     RECT  29.4 21.347 30.264 21.493 ;
     RECT  50.208 21.061 53.976 21.637 ;
     RECT  67.2 21.205 68.664 21.637 ;
     RECT  76.272 18.995 76.296 21.637 ;
     RECT  47.472 20.291 47.496 21.683 ;
     RECT  83.4 13.331 83.712 21.685 ;
     RECT  33.264 21.491 35.352 21.875 ;
     RECT  7.632 21.203 8.112 21.925 ;
     RECT  21.12 21.925 21.144 21.973 ;
     RECT  22.944 21.061 26.472 22.115 ;
     RECT  77.616 21.395 78.504 22.115 ;
     RECT  79.824 21.973 79.848 22.115 ;
     RECT  39.456 20.965 40.512 22.211 ;
     RECT  55.68 17.651 59.016 22.261 ;
     RECT  28.656 21.493 30.264 22.307 ;
     RECT  75.696 21.637 76.296 22.451 ;
     RECT  23.04 22.115 26.472 22.453 ;
     RECT  32.256 21.491 32.28 22.453 ;
     RECT  44.208 20.965 45.912 22.499 ;
     RECT  32.256 22.453 32.712 22.595 ;
     RECT  55.68 22.261 59.112 22.645 ;
     RECT  21.12 21.973 21.432 22.691 ;
     RECT  7.104 21.925 8.112 22.739 ;
     RECT  63.84 21.443 64.488 22.835 ;
     RECT  9.456 21.637 9.48 22.933 ;
     RECT  34.08 21.875 35.352 23.027 ;
     RECT  71.088 21.203 73.08 23.029 ;
     RECT  74.304 21.203 74.328 23.029 ;
     RECT  12.72 21.155 17.496 23.125 ;
     RECT  18.6 21.109 19.752 23.125 ;
     RECT  11.712 21.155 11.736 23.173 ;
     RECT  12.72 23.125 19.752 23.173 ;
     RECT  39.936 22.211 40.512 23.269 ;
     RECT  60.768 18.179 60.792 23.365 ;
     RECT  61.8 21.443 62.112 23.365 ;
     RECT  83.28 21.685 83.712 23.365 ;
     RECT  44.832 22.499 45.912 23.459 ;
     RECT  50.208 21.637 54.024 23.507 ;
     RECT  23.04 22.453 27.384 23.555 ;
     RECT  28.656 22.307 29.712 23.603 ;
     RECT  10.656 22.789 10.68 23.651 ;
     RECT  60.768 23.365 62.112 23.653 ;
     RECT  64.08 22.835 64.488 23.653 ;
     RECT  65.472 20.963 65.784 23.653 ;
     RECT  76.272 22.451 76.296 23.797 ;
     RECT  39.6 23.269 40.512 23.845 ;
     RECT  11.712 23.173 19.752 23.891 ;
     RECT  60.768 23.653 62.664 23.891 ;
     RECT  37.872 21.155 37.896 23.893 ;
     RECT  46.944 22.741 46.968 23.939 ;
     RECT  7.8 22.739 8.112 23.941 ;
     RECT  9.12 22.933 9.48 23.941 ;
     RECT  39.12 23.845 40.512 23.987 ;
     RECT  67.2 21.637 69.528 23.987 ;
     RECT  11.712 23.891 11.784 24.133 ;
     RECT  42.144 23.221 42.168 24.275 ;
     RECT  7.8 23.941 9.48 24.371 ;
     RECT  52.464 23.507 54.024 24.373 ;
     RECT  55.68 22.645 59.496 24.373 ;
     RECT  75.84 23.797 76.296 24.515 ;
     RECT  37.776 23.893 37.896 24.611 ;
     RECT  60.768 23.891 62.112 24.659 ;
     RECT  82.848 23.365 83.712 24.659 ;
     RECT  32.256 22.595 32.52 24.661 ;
     RECT  21.12 22.691 21.144 24.709 ;
     RECT  11.52 24.133 11.784 24.851 ;
     RECT  23.04 23.555 26.472 24.851 ;
     RECT  29.04 23.603 29.712 24.899 ;
     RECT  77.616 22.115 78.456 24.899 ;
     RECT  32.256 24.661 32.856 24.947 ;
     RECT  71.088 23.029 74.328 24.997 ;
     RECT  21.12 24.709 21.336 25.091 ;
     RECT  52.464 24.373 59.496 25.091 ;
     RECT  44.928 23.459 45.912 25.093 ;
     RECT  5.664 24.661 5.688 25.139 ;
     RECT  13.104 23.891 19.752 25.187 ;
     RECT  71.088 24.997 74.664 25.189 ;
     RECT  70.656 25.189 74.664 25.235 ;
     RECT  70.656 25.235 74.328 25.283 ;
     RECT  36.672 25.093 36.696 25.331 ;
     RECT  67.2 23.987 68.28 25.573 ;
     RECT  69.504 23.987 69.528 25.573 ;
     RECT  80.736 23.893 80.76 25.573 ;
     RECT  76.272 24.515 76.296 25.621 ;
     RECT  32.256 24.947 32.52 25.667 ;
     RECT  44.928 25.093 46.776 25.667 ;
     RECT  70.656 25.283 73.032 25.715 ;
     RECT  55.68 25.091 59.496 25.763 ;
     RECT  11.712 24.851 11.784 26.053 ;
     RECT  80.736 25.573 80.856 26.149 ;
     RECT  80.4 26.149 80.856 26.195 ;
     RECT  7.8 24.371 8.712 26.197 ;
     RECT  74.304 25.283 74.328 26.197 ;
     RECT  2.4 15.061 4.632 26.243 ;
     RECT  67.2 25.573 69.528 26.243 ;
     RECT  75.84 25.621 76.296 26.243 ;
     RECT  21.12 25.091 21.144 26.291 ;
     RECT  50.208 23.507 51.432 26.291 ;
     RECT  70.656 25.715 72.912 26.387 ;
     RECT  13.2 25.187 19.752 26.389 ;
     RECT  11.712 26.053 11.976 26.533 ;
     RECT  11.712 26.533 12.216 26.629 ;
     RECT  13.2 26.389 19.848 26.629 ;
     RECT  29.28 24.899 29.712 26.629 ;
     RECT  32.256 25.667 32.28 26.677 ;
     RECT  61.8 24.659 62.112 26.677 ;
     RECT  32.256 26.677 32.472 26.723 ;
     RECT  52.464 25.091 53.976 26.725 ;
     RECT  67.2 26.243 68.904 26.725 ;
     RECT  11.712 26.629 19.848 26.771 ;
     RECT  64.08 23.653 65.784 26.771 ;
     RECT  80.4 26.195 80.76 26.771 ;
     RECT  67.104 26.725 68.904 26.819 ;
     RECT  24 24.851 26.472 26.821 ;
     RECT  39.6 23.987 40.512 26.821 ;
     RECT  74.304 26.197 74.712 26.915 ;
     RECT  39.312 26.821 40.512 26.963 ;
     RECT  7.392 26.197 8.712 27.059 ;
     RECT  67.104 26.819 68.472 27.157 ;
     RECT  66.768 27.157 68.472 27.205 ;
     RECT  2.4 26.243 3.912 27.301 ;
     RECT  71.088 26.387 72.912 27.301 ;
     RECT  74.304 26.915 74.328 27.301 ;
     RECT  11.712 26.771 19.752 27.347 ;
     RECT  80.736 26.771 80.76 27.445 ;
     RECT  52.464 26.725 54.168 27.587 ;
     RECT  2.4 27.301 4.536 27.877 ;
     RECT  28.416 26.629 29.712 27.877 ;
     RECT  32.448 26.723 32.472 27.877 ;
     RECT  11.712 27.347 12.216 27.923 ;
     RECT  27.456 27.877 29.712 27.923 ;
     RECT  11.712 27.923 11.832 27.925 ;
     RECT  39.504 26.963 40.512 27.925 ;
     RECT  48.48 27.589 48.504 28.069 ;
     RECT  11.328 27.925 11.832 28.115 ;
     RECT  48.48 28.069 48.744 28.115 ;
     RECT  39.024 27.925 40.512 28.117 ;
     RECT  22.032 28.021 22.056 28.213 ;
     RECT  32.448 27.877 33.096 28.213 ;
     RECT  34.08 23.027 35.112 28.213 ;
     RECT  77.616 24.899 78.408 28.213 ;
     RECT  37.776 24.611 37.8 28.261 ;
     RECT  39.024 28.117 40.632 28.261 ;
     RECT  50.208 26.291 51.312 28.261 ;
     RECT  52.464 27.587 53.976 28.261 ;
     RECT  64.08 26.771 65.496 28.261 ;
     RECT  66.672 27.205 68.472 28.261 ;
     RECT  64.08 28.261 68.472 28.307 ;
     RECT  36.576 28.213 36.6 28.405 ;
     RECT  29.28 27.923 29.712 28.501 ;
     RECT  13.2 27.347 19.752 28.643 ;
     RECT  71.088 27.301 74.328 28.643 ;
     RECT  21.168 28.213 22.056 28.645 ;
     RECT  23.712 26.821 26.472 28.693 ;
     RECT  27.456 27.923 27.48 28.693 ;
     RECT  44.928 25.667 46.536 28.693 ;
     RECT  37.776 28.261 40.632 28.739 ;
     RECT  11.712 28.115 11.832 28.787 ;
     RECT  32.448 28.213 35.112 28.787 ;
     RECT  36.576 28.405 36.648 28.787 ;
     RECT  23.712 28.693 27.48 28.835 ;
     RECT  36.624 28.787 36.648 28.837 ;
     RECT  37.776 28.739 38.184 28.837 ;
     RECT  21.12 28.645 22.056 28.883 ;
     RECT  23.712 28.835 26.472 28.933 ;
     RECT  36.624 28.837 38.184 28.979 ;
     RECT  77.616 28.213 78.456 28.981 ;
     RECT  21.12 28.883 21.144 29.027 ;
     RECT  36.768 28.979 38.184 29.027 ;
     RECT  13.2 28.643 19.128 29.029 ;
     RECT  44.352 28.693 46.536 29.029 ;
     RECT  61.8 26.677 62.808 29.029 ;
     RECT  64.08 28.307 64.488 29.029 ;
     RECT  42.576 27.733 42.6 29.123 ;
     RECT  22.8 28.933 26.472 29.171 ;
     RECT  50.208 28.261 53.976 29.219 ;
     RECT  2.304 27.877 4.536 29.267 ;
     RECT  33.072 28.787 35.112 29.267 ;
     RECT  33.84 29.267 35.112 29.507 ;
     RECT  44.352 29.029 46.824 29.507 ;
     RECT  39.504 28.739 40.632 29.555 ;
     RECT  55.68 25.763 59.016 29.605 ;
     RECT  69.936 28.501 69.96 29.699 ;
     RECT  80.736 27.445 81.528 29.699 ;
     RECT  29.28 28.501 29.88 29.749 ;
     RECT  37.776 29.027 38.184 29.795 ;
     RECT  34.08 29.507 35.112 29.845 ;
     RECT  39.504 29.555 40.512 29.893 ;
     RECT  77.616 28.981 78.648 30.083 ;
     RECT  22.752 29.893 22.776 30.181 ;
     RECT  24 29.171 26.472 30.181 ;
     RECT  80.736 29.699 80.76 30.229 ;
     RECT  80.64 30.229 80.76 30.275 ;
     RECT  36.768 29.027 36.792 30.325 ;
     RECT  29.184 29.749 29.88 30.371 ;
     RECT  7.8 27.059 8.712 30.613 ;
     RECT  55.68 29.605 59.496 30.709 ;
     RECT  60.768 24.659 60.792 30.709 ;
     RECT  76.272 26.243 76.296 30.757 ;
     RECT  77.616 30.083 78.456 30.757 ;
     RECT  29.184 30.371 29.832 30.803 ;
     RECT  50.208 29.219 51.312 30.853 ;
     RECT  36.72 30.325 36.792 31.139 ;
     RECT  34.08 29.845 35.208 31.187 ;
     RECT  83.4 24.659 83.712 31.237 ;
     RECT  48.72 28.115 48.744 31.285 ;
     RECT  50.064 30.853 51.312 31.285 ;
     RECT  74.304 28.643 74.328 31.285 ;
     RECT  44.928 29.507 46.824 31.331 ;
     RECT  76.272 30.757 78.456 31.331 ;
     RECT  61.8 29.029 64.488 31.333 ;
     RECT  65.472 28.307 68.472 31.333 ;
     RECT  39.36 29.893 40.512 31.379 ;
     RECT  7.2 30.613 8.712 31.475 ;
     RECT  48.72 31.285 51.312 31.571 ;
     RECT  52.464 29.219 53.976 31.861 ;
     RECT  76.272 31.331 76.296 31.861 ;
     RECT  77.856 31.331 78.456 31.907 ;
     RECT  29.184 30.803 29.712 32.149 ;
     RECT  82.992 31.237 83.712 32.195 ;
     RECT  44.928 31.331 46.728 32.339 ;
     RECT  39.504 31.379 40.512 32.341 ;
     RECT  41.616 31.381 41.64 32.341 ;
     RECT  2.4 29.267 4.536 32.437 ;
     RECT  80.64 30.275 80.664 32.437 ;
     RECT  9.792 29.845 9.816 32.485 ;
     RECT  61.8 31.333 68.472 32.531 ;
     RECT  11.712 28.787 11.736 32.725 ;
     RECT  13.104 29.029 19.128 32.725 ;
     RECT  71.088 28.643 72.912 32.725 ;
     RECT  74.256 31.285 74.328 32.725 ;
     RECT  22.752 30.181 26.472 33.011 ;
     RECT  79.824 32.437 81.048 33.011 ;
     RECT  39.504 32.341 41.64 33.155 ;
     RECT  33.024 30.997 33.048 33.157 ;
     RECT  34.08 31.187 35.112 33.157 ;
     RECT  33.024 33.157 35.112 33.395 ;
     RECT  79.824 33.011 80.952 33.443 ;
     RECT  48.96 31.571 51.312 33.445 ;
     RECT  52.416 31.861 53.976 33.445 ;
     RECT  33.024 33.395 33.048 33.541 ;
     RECT  48.96 33.445 53.976 33.541 ;
     RECT  48.528 33.541 53.976 33.587 ;
     RECT  67.2 32.531 68.472 33.587 ;
     RECT  29.088 32.149 29.712 33.589 ;
     RECT  2.304 32.437 4.536 33.635 ;
     RECT  32.64 33.541 33.048 33.683 ;
     RECT  79.824 33.443 80.664 33.683 ;
     RECT  7.8 31.475 8.712 34.021 ;
     RECT  9.792 32.485 9.864 34.021 ;
     RECT  2.304 33.635 3.528 34.115 ;
     RECT  5.952 33.013 5.976 34.115 ;
     RECT  41.616 33.155 41.64 34.115 ;
     RECT  79.824 33.683 79.848 34.115 ;
     RECT  76.224 31.861 76.296 34.165 ;
     RECT  71.088 32.725 74.328 34.213 ;
     RECT  7.8 34.021 9.864 34.259 ;
     RECT  43.68 30.133 43.704 34.355 ;
     RECT  27.456 28.835 27.48 34.501 ;
     RECT  36.72 31.139 36.744 34.741 ;
     RECT  37.776 29.795 37.8 34.741 ;
     RECT  49.632 33.587 53.976 34.741 ;
     RECT  27.456 34.501 27.816 34.789 ;
     RECT  29.088 33.589 29.832 34.789 ;
     RECT  4.512 33.635 4.536 34.883 ;
     RECT  27.456 34.789 29.832 34.931 ;
     RECT  31.008 29.221 31.032 34.981 ;
     RECT  32.64 33.683 32.664 34.981 ;
     RECT  61.8 32.531 66.168 35.027 ;
     RECT  31.008 34.981 32.664 35.171 ;
     RECT  31.008 35.171 31.032 35.267 ;
     RECT  67.2 33.587 68.04 35.269 ;
     RECT  44.928 32.339 45.912 35.317 ;
     RECT  2.304 34.115 3.48 35.411 ;
     RECT  2.304 35.411 2.712 35.459 ;
     RECT  29.088 34.931 29.832 35.459 ;
     RECT  70.656 34.213 74.328 35.459 ;
     RECT  71.088 35.459 74.328 35.507 ;
     RECT  78 31.907 78.456 35.555 ;
     RECT  23.616 33.011 26.472 35.557 ;
     RECT  27.456 34.931 27.816 35.557 ;
     RECT  29.232 35.459 29.832 35.699 ;
     RECT  74.304 35.507 74.328 35.701 ;
     RECT  49.632 34.741 54.12 35.747 ;
     RECT  7.8 34.259 9.24 35.989 ;
     RECT  61.8 35.027 64.488 35.989 ;
     RECT  65.472 35.027 65.832 35.989 ;
     RECT  67.2 35.269 68.424 35.989 ;
     RECT  61.8 35.989 68.424 36.131 ;
     RECT  76.08 34.165 76.296 36.133 ;
     RECT  76.08 36.133 76.392 36.179 ;
     RECT  21.216 33.877 21.24 36.181 ;
     RECT  6.24 34.261 6.264 36.227 ;
     RECT  32.64 35.171 32.664 36.229 ;
     RECT  32.496 36.229 32.664 36.275 ;
     RECT  82.08 35.077 82.104 36.275 ;
     RECT  44.448 35.317 45.912 36.277 ;
     RECT  23.616 35.557 27.816 36.371 ;
     RECT  23.616 36.371 27.48 36.373 ;
     RECT  7.8 35.989 9.528 36.419 ;
     RECT  11.712 32.725 19.128 36.421 ;
     RECT  66.816 36.131 68.424 36.467 ;
     RECT  44.448 36.277 46.392 36.469 ;
     RECT  48.528 33.587 48.552 36.515 ;
     RECT  74.304 35.701 74.76 36.611 ;
     RECT  21.216 36.181 21.432 36.661 ;
     RECT  7.8 36.419 9.336 36.755 ;
     RECT  78 35.555 78.312 36.757 ;
     RECT  7.8 36.755 9.24 36.803 ;
     RECT  11.712 36.421 19.848 36.853 ;
     RECT  20.928 36.661 21.432 36.853 ;
     RECT  29.232 35.699 29.712 36.901 ;
     RECT  11.712 36.853 21.432 36.947 ;
     RECT  11.712 36.947 14.568 36.949 ;
     RECT  36.72 34.741 37.8 36.995 ;
     RECT  78 36.757 78.456 36.995 ;
     RECT  15.696 36.947 21.432 37.043 ;
     RECT  28.464 36.901 29.712 37.043 ;
     RECT  76.272 36.179 76.392 37.043 ;
     RECT  11.04 36.949 14.568 37.091 ;
     RECT  32.496 36.275 32.52 37.091 ;
     RECT  44.448 36.469 46.44 37.093 ;
     RECT  61.8 36.131 65.832 37.093 ;
     RECT  66.816 36.467 68.04 37.093 ;
     RECT  44.448 37.093 46.584 37.139 ;
     RECT  71.088 35.507 73.128 37.139 ;
     RECT  44.928 37.139 46.584 37.235 ;
     RECT  7.8 36.803 9.144 37.283 ;
     RECT  37.776 36.995 37.8 37.429 ;
     RECT  39.504 33.155 40.512 37.429 ;
     RECT  42.144 35.317 42.168 37.571 ;
     RECT  61.8 37.093 68.04 37.571 ;
     RECT  21.216 37.043 21.432 37.573 ;
     RECT  78 36.995 78.312 37.573 ;
     RECT  37.776 37.429 40.512 37.667 ;
     RECT  61.8 37.571 65.976 37.859 ;
     RECT  69.696 37.429 69.72 37.861 ;
     RECT  15.696 37.043 19.848 37.955 ;
     RECT  23.136 36.373 27.48 38.003 ;
     RECT  15.696 37.955 19.8 38.099 ;
     RECT  23.136 38.003 26.472 38.147 ;
     RECT  69.696 37.861 69.96 38.387 ;
     RECT  55.68 30.709 60.792 38.389 ;
     RECT  61.8 37.859 64.488 38.389 ;
     RECT  21.216 37.573 21.768 38.435 ;
     RECT  47.76 36.949 47.784 38.435 ;
     RECT  44.928 37.235 45.912 38.533 ;
     RECT  16.032 38.099 19.8 38.675 ;
     RECT  65.472 37.859 65.976 38.675 ;
     RECT  40.032 37.667 40.512 38.677 ;
     RECT  37.776 37.667 38.616 38.771 ;
     RECT  11.712 37.091 14.568 38.773 ;
     RECT  44.928 38.533 46.248 38.773 ;
     RECT  16.032 38.675 19.128 38.819 ;
     RECT  39.648 38.677 40.512 38.819 ;
     RECT  81.456 37.621 81.48 38.819 ;
     RECT  11.712 38.773 14.856 38.963 ;
     RECT  21.312 38.435 21.768 39.011 ;
     RECT  44.928 38.773 46.728 39.059 ;
     RECT  69.936 38.387 69.96 39.061 ;
     RECT  71.088 37.139 72.912 39.061 ;
     RECT  69.936 39.061 72.912 39.109 ;
     RECT  74.304 36.611 74.328 39.109 ;
     RECT  27.456 38.003 27.48 39.157 ;
     RECT  29.232 37.043 29.712 39.157 ;
     RECT  7.8 37.283 8.856 39.203 ;
     RECT  2.4 35.459 2.712 39.301 ;
     RECT  7.8 39.203 8.712 39.301 ;
     RECT  83.4 32.195 83.712 39.301 ;
     RECT  27.456 39.157 29.712 39.587 ;
     RECT  52.464 35.747 54.12 39.589 ;
     RECT  4.992 39.061 5.016 39.685 ;
     RECT  39.984 38.819 40.512 39.781 ;
     RECT  28.368 39.587 29.712 39.827 ;
     RECT  4.032 39.685 5.016 39.923 ;
     RECT  55.68 38.389 64.488 39.923 ;
     RECT  82.656 39.301 83.712 39.923 ;
     RECT  28.368 39.827 28.392 40.019 ;
     RECT  31.152 39.157 31.176 40.019 ;
     RECT  69.936 39.109 74.328 40.165 ;
     RECT  52.464 39.589 54.168 40.259 ;
     RECT  55.68 39.923 62.952 40.259 ;
     RECT  11.712 38.963 14.712 40.355 ;
     RECT  69.936 40.165 74.904 40.355 ;
     RECT  20.64 40.117 20.664 40.403 ;
     RECT  21.744 39.011 21.768 40.453 ;
     RECT  36.72 36.995 36.744 40.499 ;
     RECT  2.4 39.301 2.808 40.547 ;
     RECT  16.704 38.819 19.128 40.549 ;
     RECT  21.744 40.453 21.816 40.789 ;
     RECT  43.44 39.733 43.464 40.789 ;
     RECT  16.704 40.549 19.896 40.835 ;
     RECT  43.344 40.789 43.464 40.835 ;
     RECT  70.128 40.355 74.904 40.835 ;
     RECT  77.472 37.573 78.312 40.835 ;
     RECT  21.552 40.789 21.816 40.979 ;
     RECT  53.232 40.259 54.168 41.075 ;
     RECT  39.888 39.781 40.512 41.171 ;
     RECT  70.128 40.835 73.176 41.267 ;
     RECT  37.776 38.771 37.8 41.269 ;
     RECT  74.304 40.835 74.904 41.365 ;
     RECT  37.008 41.269 37.8 41.411 ;
     RECT  55.68 40.259 60.792 41.461 ;
     RECT  61.8 40.259 62.952 41.461 ;
     RECT  74.304 41.365 75.24 41.557 ;
     RECT  76.272 37.043 76.296 41.557 ;
     RECT  34.08 33.395 35.112 41.605 ;
     RECT  77.52 40.835 78.312 41.605 ;
     RECT  31.056 40.981 31.08 41.651 ;
     RECT  34.08 41.605 35.592 41.651 ;
     RECT  80.016 41.029 80.04 41.651 ;
     RECT  82.08 40.837 82.104 41.651 ;
     RECT  77.52 41.605 78.792 41.747 ;
     RECT  41.616 40.693 41.64 41.795 ;
     RECT  11.712 40.355 13.512 41.893 ;
     RECT  14.544 40.355 14.712 41.893 ;
     RECT  11.712 41.893 14.712 41.941 ;
     RECT  47.376 39.733 47.4 42.133 ;
     RECT  16.704 40.835 19.128 42.229 ;
     RECT  7.68 39.301 8.712 42.467 ;
     RECT  40.032 41.171 40.512 42.467 ;
     RECT  21.744 40.979 21.768 42.469 ;
     RECT  23.376 38.147 26.472 42.469 ;
     RECT  22.896 42.469 26.472 42.565 ;
     RECT  55.68 41.461 62.952 42.659 ;
     RECT  43.344 40.835 43.368 42.707 ;
     RECT  9.936 40.165 9.96 42.709 ;
     RECT  47.376 42.133 47.928 42.709 ;
     RECT  22.896 42.565 26.616 42.755 ;
     RECT  71.088 41.267 73.176 42.755 ;
     RECT  9.936 42.709 10.248 42.803 ;
     RECT  47.136 42.709 47.928 42.803 ;
     RECT  4.032 39.923 4.056 42.899 ;
     RECT  64.464 39.923 64.488 42.899 ;
     RECT  16.704 42.229 20.04 42.947 ;
     RECT  11.712 41.941 14.856 42.995 ;
     RECT  34.56 41.651 35.592 42.997 ;
     RECT  37.776 41.411 37.8 43.093 ;
     RECT  38.784 41.749 38.808 43.093 ;
     RECT  33.504 42.325 33.528 43.141 ;
     RECT  65.472 38.675 65.88 43.141 ;
     RECT  21.744 42.469 21.816 43.237 ;
     RECT  29.4 39.827 29.712 43.237 ;
     RECT  74.304 41.557 76.296 43.283 ;
     RECT  44.928 39.059 45.912 43.285 ;
     RECT  67.2 37.571 68.04 43.285 ;
     RECT  78 41.747 78.792 43.285 ;
     RECT  37.776 43.093 38.808 43.427 ;
     RECT  77.904 43.285 78.792 43.525 ;
     RECT  74.304 43.283 75.24 43.571 ;
     RECT  74.304 43.571 74.712 43.619 ;
     RECT  7.8 42.467 8.712 43.717 ;
     RECT  53.232 41.075 54.12 43.861 ;
     RECT  21.744 43.237 21.864 43.907 ;
     RECT  77.904 43.525 79.272 43.907 ;
     RECT  49.632 35.747 51.312 43.955 ;
     RECT  10.224 42.803 10.248 44.051 ;
     RECT  23.376 42.755 26.616 44.051 ;
     RECT  74.304 43.619 74.664 44.099 ;
     RECT  7.44 43.717 8.712 44.195 ;
     RECT  29.4 43.237 30.264 44.197 ;
     RECT  4.32 43.477 4.344 44.243 ;
     RECT  47.136 42.803 47.4 44.339 ;
     RECT  47.376 44.339 47.4 44.389 ;
     RECT  74.64 44.099 74.664 44.531 ;
     RECT  34.56 42.997 36.216 44.579 ;
     RECT  28.656 44.197 30.264 44.627 ;
     RECT  44.448 43.285 45.912 44.627 ;
     RECT  11.712 42.995 14.568 44.629 ;
     RECT  34.8 44.579 36.216 44.629 ;
     RECT  20.256 43.861 20.28 44.677 ;
     RECT  21.744 43.907 21.768 44.677 ;
     RECT  42.336 42.325 42.36 44.677 ;
     RECT  42.336 44.677 42.744 44.723 ;
     RECT  64.896 43.141 65.88 44.771 ;
     RECT  83.4 39.923 83.712 44.773 ;
     RECT  20.256 44.677 21.768 44.867 ;
     RECT  31.536 44.581 31.56 44.869 ;
     RECT  32.592 43.141 33.528 44.869 ;
     RECT  53.232 43.861 54.216 44.869 ;
     RECT  55.68 42.659 60.792 44.869 ;
     RECT  47.376 44.389 47.592 44.917 ;
     RECT  28.656 44.627 29.712 44.965 ;
     RECT  37.776 43.427 38.76 44.965 ;
     RECT  21.216 44.867 21.768 45.011 ;
     RECT  31.536 44.869 33.528 45.011 ;
     RECT  34.8 44.629 36.456 45.011 ;
     RECT  23.376 44.051 26.472 45.059 ;
     RECT  67.2 43.285 68.28 45.299 ;
     RECT  16.704 42.947 19.128 45.301 ;
     RECT  5.904 40.741 5.928 45.347 ;
     RECT  21.312 45.011 21.768 45.347 ;
     RECT  42.72 44.723 42.744 45.491 ;
     RECT  50.448 43.955 51.312 45.539 ;
     RECT  37.776 44.965 38.808 45.541 ;
     RECT  10.8 44.629 14.568 45.587 ;
     RECT  53.232 44.869 60.792 45.587 ;
     RECT  21.312 45.347 21.336 45.635 ;
     RECT  44.88 44.627 45.912 45.685 ;
     RECT  32.592 45.011 33.528 45.731 ;
     RECT  64.368 45.493 64.392 45.733 ;
     RECT  31.536 45.011 31.56 45.779 ;
     RECT  40.2 42.467 40.512 45.781 ;
     RECT  44.88 45.685 46.056 45.829 ;
     RECT  32.592 45.731 33.24 45.875 ;
     RECT  37.632 45.541 38.808 46.021 ;
     RECT  40.2 45.781 40.824 46.021 ;
     RECT  78 43.907 79.272 46.165 ;
     RECT  82.752 44.773 83.712 46.165 ;
     RECT  7.44 44.195 8.112 46.211 ;
     RECT  15.792 45.301 19.128 46.211 ;
     RECT  34.8 45.011 35.592 46.213 ;
     RECT  47.376 44.917 48.072 46.259 ;
     RECT  69.696 43.669 69.72 46.259 ;
     RECT  7.68 46.211 8.112 46.309 ;
     RECT  11.712 45.587 14.568 46.499 ;
     RECT  61.8 42.659 62.952 46.499 ;
     RECT  81.888 46.165 83.712 46.499 ;
     RECT  12.912 46.499 14.568 46.547 ;
     RECT  4.752 46.117 4.776 46.645 ;
     RECT  5.952 45.637 5.976 46.645 ;
     RECT  65.472 44.771 65.88 46.645 ;
     RECT  21.12 46.165 21.144 46.741 ;
     RECT  7.68 46.309 8.568 46.835 ;
     RECT  20.304 46.741 21.144 46.883 ;
     RECT  32.592 45.875 32.616 46.885 ;
     RECT  31.92 46.885 32.616 46.931 ;
     RECT  11.712 46.499 11.736 46.933 ;
     RECT  54.72 45.587 60.792 46.933 ;
     RECT  61.8 46.499 62.112 46.933 ;
     RECT  64.32 45.733 64.392 46.933 ;
     RECT  63.888 46.933 64.392 46.979 ;
     RECT  37.632 46.021 40.824 47.027 ;
     RECT  17.376 46.211 19.128 47.029 ;
     RECT  23.376 45.059 24.408 47.075 ;
     RECT  37.632 47.027 38.088 47.075 ;
     RECT  4.752 46.645 5.976 47.173 ;
     RECT  17.376 47.029 19.416 47.219 ;
     RECT  15.792 46.211 15.816 47.315 ;
     RECT  4.56 47.173 5.976 47.363 ;
     RECT  39.264 47.027 40.824 47.363 ;
     RECT  44.88 45.829 46.104 47.363 ;
     RECT  54.72 46.933 62.112 47.459 ;
     RECT  45.6 47.363 46.104 47.461 ;
     RECT  63.888 46.979 64.344 47.507 ;
     RECT  64.32 47.507 64.344 47.603 ;
     RECT  78 46.165 80.232 47.603 ;
     RECT  10.08 47.557 10.104 47.747 ;
     RECT  25.584 45.059 26.472 47.891 ;
     RECT  53.232 45.587 53.592 47.891 ;
     RECT  81.888 46.499 81.912 47.939 ;
     RECT  23.376 47.075 24.312 48.181 ;
     RECT  47.376 46.259 47.4 48.181 ;
     RECT  45.6 47.461 46.296 48.275 ;
     RECT  5.952 47.363 5.976 48.421 ;
     RECT  23.28 48.181 24.312 48.421 ;
     RECT  51 45.539 51.312 48.421 ;
     RECT  65.472 46.645 65.976 48.421 ;
     RECT  74.64 47.845 74.664 48.421 ;
     RECT  13.2 46.547 14.568 48.467 ;
     RECT  33.408 48.133 33.432 48.467 ;
     RECT  26.688 48.421 26.712 48.563 ;
     RECT  11.376 46.933 11.736 48.659 ;
     RECT  7.8 46.835 8.568 48.661 ;
     RECT  22.848 48.421 24.312 48.707 ;
     RECT  37.776 47.075 38.088 48.707 ;
     RECT  76.272 43.283 76.296 48.805 ;
     RECT  31.92 46.931 31.944 48.853 ;
     RECT  67.2 45.299 68.04 48.853 ;
     RECT  27.888 44.965 29.712 48.901 ;
     RECT  45.6 48.275 46.056 48.901 ;
     RECT  17.376 47.219 18.912 48.995 ;
     RECT  37.776 48.707 37.8 48.995 ;
     RECT  4.56 47.363 4.776 48.997 ;
     RECT  5.76 48.421 5.976 48.997 ;
     RECT  64.368 48.901 64.392 48.997 ;
     RECT  65.472 48.421 66.216 48.997 ;
     RECT  67.2 48.853 68.328 48.997 ;
     RECT  69.504 48.949 69.528 48.997 ;
     RECT  27.12 48.901 29.712 49.043 ;
     RECT  31.92 48.853 33.096 49.043 ;
     RECT  44.928 48.901 46.056 49.043 ;
     RECT  54.72 47.459 60.792 49.045 ;
     RECT  61.8 47.459 62.112 49.045 ;
     RECT  64.368 48.997 66.216 49.091 ;
     RECT  4.032 48.997 5.976 49.093 ;
     RECT  4.032 49.093 6.504 49.139 ;
     RECT  11.712 48.659 11.736 49.139 ;
     RECT  64.368 49.091 65.976 49.139 ;
     RECT  67.2 48.997 69.528 49.139 ;
     RECT  74.64 48.421 74.76 49.283 ;
     RECT  45.6 49.043 46.056 49.333 ;
     RECT  47.376 48.181 47.688 49.333 ;
     RECT  21.12 46.883 21.144 49.379 ;
     RECT  47.376 49.333 47.928 49.475 ;
     RECT  54.72 49.045 62.112 49.523 ;
     RECT  13.2 48.467 14.232 49.525 ;
     RECT  50.736 48.421 51.312 49.525 ;
     RECT  83.4 46.499 83.712 49.525 ;
     RECT  50.448 49.525 51.312 49.573 ;
     RECT  47.664 49.475 47.928 49.619 ;
     RECT  76.032 48.805 76.296 49.619 ;
     RECT  43.344 48.421 43.368 49.763 ;
     RECT  69.504 49.139 69.528 49.811 ;
     RECT  53.232 47.891 53.256 49.909 ;
     RECT  64.368 49.139 64.392 50.051 ;
     RECT  4.032 49.139 4.776 50.099 ;
     RECT  31.92 49.043 32.472 50.147 ;
     RECT  45.6 49.333 46.2 50.147 ;
     RECT  4.56 50.099 4.776 50.149 ;
     RECT  5.76 49.139 6.504 50.149 ;
     RECT  7.8 48.661 8.808 50.195 ;
     RECT  37.056 49.573 37.08 50.291 ;
     RECT  34.8 46.213 35.88 50.435 ;
     RECT  47.904 49.619 47.928 50.435 ;
     RECT  54.864 49.523 62.112 50.435 ;
     RECT  18.48 48.995 18.912 50.579 ;
     RECT  67.2 49.139 68.328 50.579 ;
     RECT  54.864 50.435 60.792 50.627 ;
     RECT  27.408 49.043 29.712 50.675 ;
     RECT  27.84 50.675 29.712 50.771 ;
     RECT  49.68 49.573 51.312 50.771 ;
     RECT  60.432 50.627 60.792 50.771 ;
     RECT  23.232 48.707 24.312 51.011 ;
     RECT  39.264 47.363 40.512 51.013 ;
     RECT  4.56 50.149 6.504 51.107 ;
     RECT  71.088 42.755 72.912 51.205 ;
     RECT  12.864 49.525 14.232 51.395 ;
     RECT  32.4 50.147 32.472 51.443 ;
     RECT  74.736 49.283 74.76 51.635 ;
     RECT  7.8 50.195 8.112 51.733 ;
     RECT  9.12 51.589 9.144 51.779 ;
     RECT  27.888 50.771 29.712 51.829 ;
     RECT  53.232 49.909 53.784 51.829 ;
     RECT  34.8 50.435 35.208 51.877 ;
     RECT  4.752 51.107 6.504 51.923 ;
     RECT  10.32 50.101 10.344 51.923 ;
     RECT  21.312 50.917 21.336 51.971 ;
     RECT  50.304 50.771 51.312 51.971 ;
     RECT  75.264 51.637 75.288 51.973 ;
     RECT  76.272 49.619 76.296 51.973 ;
     RECT  32.4 51.443 32.424 52.021 ;
     RECT  39.168 51.013 40.512 52.021 ;
     RECT  4.752 51.923 5.688 52.115 ;
     RECT  75.264 51.973 76.296 52.115 ;
     RECT  2.4 40.547 2.712 52.117 ;
     RECT  23.376 51.011 24.312 52.163 ;
     RECT  38.4 52.021 40.512 52.163 ;
     RECT  78 47.603 79.272 52.165 ;
     RECT  70.176 51.205 72.912 52.211 ;
     RECT  75.264 52.115 75.288 52.211 ;
     RECT  78 52.165 79.8 52.211 ;
     RECT  54.864 50.627 59.016 52.307 ;
     RECT  2.4 52.117 3.144 52.309 ;
     RECT  26.784 51.877 26.808 52.403 ;
     RECT  60.768 50.771 60.792 52.403 ;
     RECT  61.8 50.435 62.112 52.405 ;
     RECT  7.68 51.733 8.112 52.451 ;
     RECT  13.104 51.395 14.232 52.453 ;
     RECT  39.456 52.163 40.512 52.549 ;
     RECT  34.8 51.877 35.88 52.741 ;
     RECT  33.552 51.253 33.576 52.789 ;
     RECT  34.704 52.741 36.168 52.789 ;
     RECT  67.2 50.579 68.04 52.885 ;
     RECT  13.056 52.453 14.232 52.931 ;
     RECT  33.552 52.789 36.168 52.931 ;
     RECT  67.2 52.885 68.088 52.981 ;
     RECT  79.776 52.211 79.8 52.981 ;
     RECT  82.896 49.525 83.712 52.981 ;
     RECT  76.272 52.115 76.296 53.029 ;
     RECT  65.472 49.139 65.976 53.075 ;
     RECT  76.272 53.029 76.392 53.075 ;
     RECT  32.016 52.021 32.424 53.077 ;
     RECT  39.456 52.549 41.064 53.123 ;
     RECT  52.752 51.829 53.784 53.125 ;
     RECT  25.584 47.891 25.608 53.267 ;
     RECT  32.016 53.077 33.528 53.363 ;
     RECT  45.6 50.147 45.912 53.365 ;
     RECT  79.776 52.981 80.424 53.411 ;
     RECT  23.616 52.163 24.312 53.461 ;
     RECT  2.4 52.309 3.288 53.509 ;
     RECT  61.8 52.405 63.048 53.509 ;
     RECT  17.376 48.995 17.496 53.557 ;
     RECT  23.616 53.461 25.128 53.557 ;
     RECT  38.4 52.163 38.424 53.557 ;
     RECT  45.456 53.365 45.912 53.557 ;
     RECT  33.504 53.363 33.528 53.603 ;
     RECT  79.776 53.411 79.8 53.603 ;
     RECT  23.088 53.557 25.128 53.699 ;
     RECT  45.456 53.557 46.008 53.749 ;
     RECT  34.8 52.931 36.168 53.795 ;
     RECT  13.056 52.931 13.896 53.843 ;
     RECT  17.04 53.557 17.496 53.941 ;
     RECT  82.656 52.981 83.712 53.987 ;
     RECT  61.8 53.509 63.384 54.037 ;
     RECT  13.056 53.843 13.608 54.085 ;
     RECT  21.072 53.557 21.096 54.179 ;
     RECT  39.984 53.123 41.064 54.179 ;
     RECT  45.456 53.749 46.152 54.179 ;
     RECT  76.368 53.075 76.392 54.181 ;
     RECT  78 52.211 78.648 54.323 ;
     RECT  50.448 51.971 51.312 54.371 ;
     RECT  16.896 53.941 17.496 54.421 ;
     RECT  18.6 50.579 18.912 54.421 ;
     RECT  27.792 51.829 29.712 54.517 ;
     RECT  32.016 53.363 32.424 54.563 ;
     RECT  2.4 53.509 4.68 54.611 ;
     RECT  37.968 53.557 38.424 54.661 ;
     RECT  39.984 54.179 40.512 54.661 ;
     RECT  61.8 54.037 64.104 54.661 ;
     RECT  65.472 53.075 65.496 54.661 ;
     RECT  61.8 54.661 65.496 54.755 ;
     RECT  23.328 53.699 25.128 54.901 ;
     RECT  65.616 54.757 65.64 54.947 ;
     RECT  45.456 54.179 46.008 55.091 ;
     RECT  16.896 54.421 18.912 55.141 ;
     RECT  34.8 53.795 35.208 55.189 ;
     RECT  67.2 52.981 68.376 55.237 ;
     RECT  75.648 54.181 76.392 55.283 ;
     RECT  45.6 55.091 46.008 55.331 ;
     RECT  65.952 55.237 69.24 55.331 ;
     RECT  5.664 52.115 5.688 55.379 ;
     RECT  10.272 53.941 10.296 55.379 ;
     RECT  27.792 54.517 29.832 55.429 ;
     RECT  34.8 55.189 35.304 55.429 ;
     RECT  34.704 55.429 35.304 55.477 ;
     RECT  16.56 55.141 18.912 55.667 ;
     RECT  23.184 54.901 25.128 55.715 ;
     RECT  34.608 55.477 35.304 55.717 ;
     RECT  43.92 52.357 43.944 55.907 ;
     RECT  80.88 54.613 80.904 55.907 ;
     RECT  16.56 55.667 17.4 55.955 ;
     RECT  6.768 53.365 6.792 56.003 ;
     RECT  49.536 55.525 49.56 56.243 ;
     RECT  2.4 54.611 3.912 56.389 ;
     RECT  27.792 55.429 29.976 56.389 ;
     RECT  12.672 54.085 13.608 56.483 ;
     RECT  27.312 56.389 29.976 56.483 ;
     RECT  52.752 53.125 54.12 56.483 ;
     RECT  45.6 55.331 45.912 56.485 ;
     RECT  32.4 54.563 32.424 56.581 ;
     RECT  17.376 55.955 17.4 56.627 ;
     RECT  61.8 54.755 64.584 56.771 ;
     RECT  45.024 56.485 45.912 56.867 ;
     RECT  78 54.323 78.312 56.917 ;
     RECT  52.752 56.483 53.256 56.963 ;
     RECT  18.6 55.667 18.912 56.965 ;
     RECT  27.312 56.483 27.336 57.011 ;
     RECT  34.608 55.717 35.64 57.011 ;
     RECT  52.896 56.963 53.256 57.011 ;
     RECT  76.368 55.283 76.392 57.013 ;
     RECT  14.832 56.389 14.856 57.059 ;
     RECT  37.968 54.661 40.512 57.059 ;
     RECT  41.616 54.661 41.64 57.059 ;
     RECT  43.824 56.437 43.848 57.059 ;
     RECT  65.952 55.331 68.04 57.059 ;
     RECT  75.216 56.437 75.24 57.059 ;
     RECT  79.632 56.725 79.656 57.059 ;
     RECT  20.544 56.677 20.568 57.061 ;
     RECT  60.624 52.405 60.648 57.061 ;
     RECT  61.8 56.771 63.048 57.061 ;
     RECT  60.624 57.061 63.048 57.203 ;
     RECT  2.4 56.389 4.776 57.299 ;
     RECT  18.48 56.965 18.912 57.299 ;
     RECT  32.4 56.581 32.664 57.395 ;
     RECT  55.68 52.307 59.016 57.445 ;
     RECT  34.608 57.011 35.544 57.493 ;
     RECT  13.2 56.483 13.608 57.541 ;
     RECT  2.4 57.299 3.912 57.635 ;
     RECT  55.68 57.445 59.496 57.635 ;
     RECT  76.272 57.013 76.392 57.635 ;
     RECT  39.984 57.059 40.512 57.637 ;
     RECT  24 55.715 25.128 57.779 ;
     RECT  51 54.371 51.312 57.781 ;
     RECT  32.4 57.395 32.472 57.829 ;
     RECT  33.888 57.493 35.544 57.875 ;
     RECT  39.984 57.637 41.016 57.875 ;
     RECT  33.888 57.875 35.4 57.923 ;
     RECT  20.544 57.061 21.096 57.925 ;
     RECT  78 56.917 78.504 57.973 ;
     RECT  32.304 57.829 32.472 58.067 ;
     RECT  20.544 57.925 21.144 58.115 ;
     RECT  71.088 52.211 72.912 58.115 ;
     RECT  7.8 52.451 8.112 58.117 ;
     RECT  37.968 57.059 38.904 58.117 ;
     RECT  67.2 57.059 68.04 58.117 ;
     RECT  69.216 55.331 69.24 58.117 ;
     RECT  34.608 57.923 35.4 58.163 ;
     RECT  50.832 57.781 51.312 58.163 ;
     RECT  6.288 57.541 6.312 58.211 ;
     RECT  21.168 58.165 21.192 58.307 ;
     RECT  32.4 58.067 32.472 58.499 ;
     RECT  18.6 57.299 18.912 58.549 ;
     RECT  13.104 57.541 13.608 58.691 ;
     RECT  78 57.973 78.984 58.691 ;
     RECT  28.656 56.483 29.976 58.741 ;
     RECT  7.68 58.117 8.112 59.173 ;
     RECT  71.088 58.115 71.112 59.173 ;
     RECT  72.24 58.115 72.912 59.173 ;
     RECT  51 58.163 51.312 59.221 ;
     RECT  18.336 58.549 18.912 59.317 ;
     RECT  37.056 58.117 38.904 59.365 ;
     RECT  39.984 57.875 40.512 59.365 ;
     RECT  37.056 59.365 40.512 59.461 ;
     RECT  18.336 59.317 19.128 59.507 ;
     RECT  36.336 59.461 40.512 59.507 ;
     RECT  36.336 59.507 38.712 59.603 ;
     RECT  53.232 57.011 53.256 59.605 ;
     RECT  55.68 57.635 57.72 59.651 ;
     RECT  13.2 58.691 13.608 59.701 ;
     RECT  34.608 58.163 35.256 59.701 ;
     RECT  45.6 56.867 45.912 59.701 ;
     RECT  67.2 58.117 70.008 59.795 ;
     RECT  44.688 59.701 45.912 59.797 ;
     RECT  81.072 59.221 81.096 59.797 ;
     RECT  18.336 59.507 18.912 59.845 ;
     RECT  2.4 57.635 3.288 59.891 ;
     RECT  16.464 58.933 16.488 59.891 ;
     RECT  55.872 59.651 57.72 59.891 ;
     RECT  67.2 59.795 69.24 60.035 ;
     RECT  39.984 59.507 40.512 60.229 ;
     RECT  39.984 60.229 40.632 60.371 ;
     RECT  80.832 59.797 81.096 60.371 ;
     RECT  34.608 59.701 35.304 60.419 ;
     RECT  37.056 59.603 38.712 60.419 ;
     RECT  42.768 57.445 42.792 60.419 ;
     RECT  69.216 60.035 69.24 60.467 ;
     RECT  22.176 54.373 22.2 60.515 ;
     RECT  39.984 60.371 40.512 60.515 ;
     RECT  53.232 59.605 53.928 60.563 ;
     RECT  44.448 59.797 45.912 60.613 ;
     RECT  78 58.691 78.504 60.613 ;
     RECT  17.904 59.845 18.912 60.661 ;
     RECT  28.656 58.741 30.6 60.757 ;
     RECT  79.824 59.701 79.848 60.803 ;
     RECT  0.144 60.613 0.168 60.899 ;
     RECT  17.04 60.661 18.912 60.899 ;
     RECT  71.088 59.173 72.912 60.901 ;
     RECT  76.368 57.635 76.392 60.901 ;
     RECT  74.784 59.797 74.808 60.947 ;
     RECT  76.272 60.901 76.392 60.947 ;
     RECT  77.472 60.613 78.504 60.947 ;
     RECT  20.688 60.277 20.712 60.949 ;
     RECT  28.656 60.757 30.696 60.995 ;
     RECT  80.832 60.371 80.952 60.995 ;
     RECT  37.584 60.419 38.712 61.043 ;
     RECT  34.8 60.419 35.304 61.093 ;
     RECT  44.448 60.613 46.056 61.141 ;
     RECT  44.448 61.141 46.104 61.187 ;
     RECT  28.656 60.995 30.6 61.235 ;
     RECT  34.8 61.093 35.352 61.237 ;
     RECT  58.992 57.635 59.496 61.333 ;
     RECT  60.624 57.203 60.648 61.333 ;
     RECT  24 57.779 24.312 61.381 ;
     RECT  70.224 60.901 72.912 61.427 ;
     RECT  40.2 60.515 40.512 61.429 ;
     RECT  32.4 58.499 32.424 61.477 ;
     RECT  83.4 53.987 83.712 61.477 ;
     RECT  20.112 60.949 20.712 61.523 ;
     RECT  23.904 61.381 24.312 61.523 ;
     RECT  10.512 57.685 10.536 61.571 ;
     RECT  58.992 61.333 60.648 61.573 ;
     RECT  34.8 61.237 36.024 61.619 ;
     RECT  38.4 61.043 38.712 61.619 ;
     RECT  71.088 61.427 72.912 61.715 ;
     RECT  80.928 60.995 80.952 61.763 ;
     RECT  20.112 61.523 20.136 61.907 ;
     RECT  44.448 61.187 44.472 61.907 ;
     RECT  65.952 57.059 65.976 62.053 ;
     RECT  67.2 60.035 68.04 62.053 ;
     RECT  43.296 60.709 43.32 62.099 ;
     RECT  17.856 60.899 18.912 62.149 ;
     RECT  55.872 59.891 57.384 62.149 ;
     RECT  4.992 60.997 5.016 62.195 ;
     RECT  28.656 61.235 29.712 62.243 ;
     RECT  55.776 62.149 57.384 62.291 ;
     RECT  53.232 60.563 53.256 62.293 ;
     RECT  40.2 61.429 41.304 62.435 ;
     RECT  45.6 61.187 46.104 62.437 ;
     RECT  48.96 60.949 48.984 62.483 ;
     RECT  6.816 59.173 8.112 62.533 ;
     RECT  6.816 62.533 8.808 62.579 ;
     RECT  58.992 61.573 60.792 62.581 ;
     RECT  58.752 62.581 60.792 62.677 ;
     RECT  71.088 61.715 71.592 62.723 ;
     RECT  53.232 62.293 54.12 62.771 ;
     RECT  55.92 62.291 57.384 62.771 ;
     RECT  38.448 61.619 38.712 62.773 ;
     RECT  82.56 61.477 83.712 62.915 ;
     RECT  56.4 62.771 57.384 62.963 ;
     RECT  13.2 59.701 14.52 62.965 ;
     RECT  33.744 62.341 33.768 63.013 ;
     RECT  58.656 62.677 60.792 63.061 ;
     RECT  61.8 57.203 63.048 63.061 ;
     RECT  76.272 60.947 76.296 63.205 ;
     RECT  77.472 60.947 78.312 63.205 ;
     RECT  38.448 62.773 39 63.301 ;
     RECT  40.2 62.435 41.112 63.301 ;
     RECT  13.104 62.965 14.52 63.347 ;
     RECT  17.76 62.149 18.912 63.541 ;
     RECT  51 59.221 51.912 63.589 ;
     RECT  38.448 63.301 41.112 63.637 ;
     RECT  43.2 62.677 43.224 63.781 ;
     RECT  11.376 62.821 11.4 63.827 ;
     RECT  49.248 62.869 49.272 63.827 ;
     RECT  32.4 61.477 32.472 63.829 ;
     RECT  28.704 62.243 29.712 63.875 ;
     RECT  33.648 63.013 33.768 63.875 ;
     RECT  26.4 63.589 26.424 63.923 ;
     RECT  51 63.589 52.872 63.923 ;
     RECT  13.2 63.347 14.52 64.019 ;
     RECT  32.016 63.829 32.472 64.019 ;
     RECT  33.648 63.875 33.672 64.019 ;
     RECT  24 61.523 24.312 64.069 ;
     RECT  13.2 64.019 13.656 64.115 ;
     RECT  58.656 63.061 63.048 64.213 ;
     RECT  17.04 63.541 18.912 64.259 ;
     RECT  17.76 64.259 18.912 64.309 ;
     RECT  34.8 61.619 35.256 64.309 ;
     RECT  58.656 64.213 63.096 64.355 ;
     RECT  52.848 63.923 52.872 64.357 ;
     RECT  71.088 62.723 71.544 64.357 ;
     RECT  72.6 61.715 72.912 64.357 ;
     RECT  23.424 64.069 24.312 64.403 ;
     RECT  45.6 62.437 46.632 64.405 ;
     RECT  54.096 62.771 54.12 64.451 ;
     RECT  74.784 63.205 74.808 64.451 ;
     RECT  33.072 64.405 33.192 64.547 ;
     RECT  58.8 64.355 63.096 64.547 ;
     RECT  33.168 64.547 33.192 64.595 ;
     RECT  38.4 63.637 41.112 64.595 ;
     RECT  69.552 62.677 69.576 64.595 ;
     RECT  34.8 64.309 35.304 64.739 ;
     RECT  45.024 64.405 46.632 64.739 ;
     RECT  24 64.403 24.312 64.789 ;
     RECT  43.2 63.781 43.896 64.789 ;
     RECT  32.016 64.019 32.04 64.835 ;
     RECT  24 64.789 25.128 64.931 ;
     RECT  43.2 64.789 44.04 64.931 ;
     RECT  15.888 63.973 15.912 64.933 ;
     RECT  71.088 64.357 72.912 64.981 ;
     RECT  52.848 64.357 53.064 65.027 ;
     RECT  70.608 64.981 72.912 65.027 ;
     RECT  38.4 64.595 38.808 65.077 ;
     RECT  51 63.923 51.312 65.077 ;
     RECT  17.76 64.309 19.56 65.171 ;
     RECT  6.768 64.885 6.792 65.267 ;
     RECT  40.2 64.595 41.112 65.269 ;
     RECT  76.272 63.205 78.312 65.317 ;
     RECT  58.8 64.547 63.048 65.509 ;
     RECT  64.08 56.771 64.584 65.509 ;
     RECT  70.608 65.027 71.544 65.555 ;
     RECT  58.8 65.509 64.584 65.557 ;
     RECT  65.952 62.053 68.04 65.557 ;
     RECT  45.504 64.739 46.632 65.603 ;
     RECT  27.792 64.645 27.816 65.651 ;
     RECT  43.2 64.931 43.8 65.651 ;
     RECT  11.232 65.557 11.256 65.795 ;
     RECT  81.648 64.741 81.672 65.845 ;
     RECT  37.872 65.077 38.808 65.939 ;
     RECT  56.4 62.963 56.712 65.941 ;
     RECT  0.144 65.173 0.168 65.989 ;
     RECT  48.336 63.829 48.36 66.083 ;
     RECT  0.144 65.989 0.264 66.131 ;
     RECT  15.408 64.933 15.912 66.179 ;
     RECT  71.088 65.555 71.544 66.179 ;
     RECT  80.688 65.845 81.672 66.179 ;
     RECT  40.2 65.269 41.304 66.275 ;
     RECT  58.8 65.557 68.04 66.323 ;
     RECT  75.408 65.317 78.312 66.661 ;
     RECT  48.096 66.085 48.12 66.755 ;
     RECT  56.4 65.941 56.904 66.755 ;
     RECT  75.408 66.661 79.128 66.755 ;
     RECT  7.8 62.579 8.808 66.853 ;
     RECT  58.8 66.323 58.92 67.091 ;
     RECT  59.952 66.323 68.04 67.091 ;
     RECT  34.8 64.739 35.256 67.093 ;
     RECT  13.2 64.115 13.512 67.189 ;
     RECT  6.864 66.853 8.808 67.237 ;
     RECT  10.656 66.661 10.68 67.237 ;
     RECT  45.6 65.603 46.632 67.237 ;
     RECT  15.888 66.179 15.912 67.283 ;
     RECT  28.896 63.875 29.712 67.283 ;
     RECT  6.864 67.237 10.68 67.331 ;
     RECT  51 65.077 51.432 67.427 ;
     RECT  58.8 67.091 58.824 67.477 ;
     RECT  71.088 66.179 71.112 67.571 ;
     RECT  6.864 67.331 9.96 67.715 ;
     RECT  28.992 67.283 29.712 67.715 ;
     RECT  6.912 67.715 9.96 67.859 ;
     RECT  76.272 66.755 79.128 67.859 ;
     RECT  49.776 67.189 49.8 67.907 ;
     RECT  61.8 67.091 68.04 67.907 ;
     RECT  59.952 67.091 60.792 67.955 ;
     RECT  5.136 66.085 5.16 68.099 ;
     RECT  34.8 67.093 35.88 68.099 ;
     RECT  45.6 67.237 46.872 68.197 ;
     RECT  0.144 66.131 0.168 68.291 ;
     RECT  80.688 66.179 80.712 68.341 ;
     RECT  38.928 66.613 38.952 68.387 ;
     RECT  80.688 68.341 80.952 68.387 ;
     RECT  60.624 67.955 60.792 68.389 ;
     RECT  61.8 67.907 67.608 68.389 ;
     RECT  2.4 59.891 2.712 68.533 ;
     RECT  43.776 65.651 43.8 68.675 ;
     RECT  6.912 67.859 9.096 68.723 ;
     RECT  26.64 68.581 26.664 68.723 ;
     RECT  74.592 67.669 74.616 68.819 ;
     RECT  17.184 67.717 17.208 68.821 ;
     RECT  58.656 67.477 58.824 68.869 ;
     RECT  2.4 68.533 2.808 68.917 ;
     RECT  24 64.931 24.312 68.917 ;
     RECT  52.848 65.027 52.872 68.963 ;
     RECT  4.608 68.917 4.632 68.965 ;
     RECT  17.088 68.821 17.208 68.965 ;
     RECT  18.6 65.171 19.56 68.965 ;
     RECT  17.088 68.965 17.304 69.011 ;
     RECT  77.184 67.859 79.128 69.011 ;
     RECT  51 67.427 51.312 69.013 ;
     RECT  68.688 68.917 68.712 69.155 ;
     RECT  44.976 68.197 46.968 69.395 ;
     RECT  27.936 68.965 27.96 69.445 ;
     RECT  41.808 67.237 41.832 69.491 ;
     RECT  44.976 69.395 46.632 69.491 ;
     RECT  60.624 68.389 67.608 69.491 ;
     RECT  13.056 67.189 13.512 69.587 ;
     RECT  21.168 68.965 21.192 69.587 ;
     RECT  58.656 68.869 59.256 69.587 ;
     RECT  29.4 67.715 29.712 69.637 ;
     RECT  27.936 69.445 28.2 69.731 ;
     RECT  27.936 69.731 27.96 69.779 ;
     RECT  0.144 69.301 0.168 69.923 ;
     RECT  56.4 66.755 56.712 69.973 ;
     RECT  29.4 69.637 30.168 70.021 ;
     RECT  5.664 68.917 5.688 70.067 ;
     RECT  80.832 68.387 80.952 70.067 ;
     RECT  80.928 70.067 80.952 70.163 ;
     RECT  40.2 66.275 40.512 70.213 ;
     RECT  17.28 69.011 17.304 70.259 ;
     RECT  39.984 70.213 40.512 70.355 ;
     RECT  61.632 69.491 67.608 70.405 ;
     RECT  54.048 69.493 54.072 70.549 ;
     RECT  54.048 70.549 54.888 70.595 ;
     RECT  70.128 69.493 70.152 70.739 ;
     RECT  29.088 70.021 30.168 70.787 ;
     RECT  36.432 69.973 36.456 70.835 ;
     RECT  18.6 68.965 19.656 70.933 ;
     RECT  34.8 68.099 35.112 71.221 ;
     RECT  56.4 69.973 56.808 71.267 ;
     RECT  21.504 70.021 21.528 71.315 ;
     RECT  24 68.917 24.408 71.315 ;
     RECT  31.44 70.117 31.464 71.315 ;
     RECT  68.928 70.741 68.952 71.317 ;
     RECT  7.8 68.723 9.096 71.651 ;
     RECT  51 69.013 51.432 71.651 ;
     RECT  60.624 69.491 60.648 71.701 ;
     RECT  61.632 70.405 67.8 71.701 ;
     RECT  3.984 68.965 4.632 71.843 ;
     RECT  60.624 71.701 67.8 71.891 ;
     RECT  75.936 71.365 75.96 72.035 ;
     RECT  65.472 71.891 67.8 72.131 ;
     RECT  45.6 69.491 46.632 72.133 ;
     RECT  68.88 71.317 68.952 72.181 ;
     RECT  27.216 71.221 27.24 72.325 ;
     RECT  58.656 69.587 58.824 72.325 ;
     RECT  68.688 72.181 68.952 72.371 ;
     RECT  3.984 71.843 4.008 72.419 ;
     RECT  18.6 70.933 20.52 72.419 ;
     RECT  54.864 70.595 54.888 72.419 ;
     RECT  68.928 72.371 68.952 72.419 ;
     RECT  58.656 72.325 59.256 72.467 ;
     RECT  58.704 72.467 59.256 72.515 ;
     RECT  80.592 71.221 80.616 72.661 ;
     RECT  80.256 72.661 80.616 72.707 ;
     RECT  13.2 69.587 13.512 72.805 ;
     RECT  29.088 70.787 29.712 72.851 ;
     RECT  37.872 65.939 37.896 72.853 ;
     RECT  37.536 72.853 37.896 72.899 ;
     RECT  18.6 72.419 19.656 72.901 ;
     RECT  27.216 72.325 27.672 72.947 ;
     RECT  58.704 72.515 58.824 72.947 ;
     RECT  7.8 71.651 9.048 72.949 ;
     RECT  34.512 71.221 35.112 72.995 ;
     RECT  70.752 71.221 70.776 73.043 ;
     RECT  45.6 72.133 47.112 73.235 ;
     RECT  7.584 72.949 9.048 73.283 ;
     RECT  22.8 72.325 22.824 73.283 ;
     RECT  65.472 72.131 67.512 73.285 ;
     RECT  80.256 72.707 80.28 73.475 ;
     RECT  51 71.651 51.312 73.477 ;
     RECT  12.528 72.805 13.512 73.571 ;
     RECT  45.6 73.235 46.632 73.571 ;
     RECT  60.624 71.891 64.296 73.571 ;
     RECT  18.48 72.901 19.656 73.621 ;
     RECT  65.472 73.285 67.608 73.669 ;
     RECT  58.704 72.947 58.728 73.765 ;
     RECT  27.216 72.947 27.24 74.053 ;
     RECT  51 73.477 51.432 74.053 ;
     RECT  72.6 65.027 72.912 74.053 ;
     RECT  37.536 72.899 37.56 74.147 ;
     RECT  65.424 73.669 67.608 74.147 ;
     RECT  77.184 69.011 78.312 74.147 ;
     RECT  7.584 73.283 8.112 74.339 ;
     RECT  18.288 73.621 19.656 74.339 ;
     RECT  61.2 73.571 64.296 74.389 ;
     RECT  65.424 74.147 66.024 74.389 ;
     RECT  44.448 73.093 44.472 74.435 ;
     RECT  27.216 74.053 27.48 74.483 ;
     RECT  67.2 74.147 67.608 74.485 ;
     RECT  74.496 72.901 74.52 74.579 ;
     RECT  50.16 74.053 51.432 74.627 ;
     RECT  67.2 74.485 68.28 74.675 ;
     RECT  2.4 68.917 2.904 74.723 ;
     RECT  11.376 73.621 11.4 74.723 ;
     RECT  50.16 74.627 51.312 74.723 ;
     RECT  58.128 73.765 58.728 74.723 ;
     RECT  61.2 74.389 66.024 74.723 ;
     RECT  64.224 74.723 64.776 74.771 ;
     RECT  27.456 74.483 27.48 74.915 ;
     RECT  53.328 72.805 53.352 74.915 ;
     RECT  55.008 74.629 55.032 74.915 ;
     RECT  58.704 74.723 58.728 74.915 ;
     RECT  18.336 74.339 19.656 75.299 ;
     RECT  76.272 74.629 76.296 75.299 ;
     RECT  18.336 75.299 18.912 75.443 ;
     RECT  72.6 74.053 73.032 75.443 ;
     RECT  2.4 74.723 2.712 75.609 ;
     RECT  7.8 74.339 8.112 75.609 ;
     RECT  13.2 73.571 13.512 75.609 ;
     RECT  18.6 75.443 18.912 75.609 ;
     RECT  24 71.315 24.312 75.609 ;
     RECT  29.4 72.851 29.712 75.609 ;
     RECT  34.8 72.995 35.112 75.609 ;
     RECT  40.2 70.355 40.512 75.609 ;
     RECT  45.6 73.571 45.912 75.609 ;
     RECT  51 74.723 51.312 75.609 ;
     RECT  56.4 71.267 56.712 75.609 ;
     RECT  67.2 74.675 67.512 75.609 ;
     RECT  72.6 75.443 72.912 75.609 ;
     RECT  78 74.147 78.312 75.609 ;
     RECT  83.4 62.915 83.712 75.609 ;
     RECT  2.4 75.609 2.52 75.623 ;
     RECT  7.8 75.609 7.92 75.623 ;
     RECT  13.2 75.609 13.32 75.623 ;
     RECT  18.6 75.609 18.72 75.623 ;
     RECT  24 75.609 24.12 75.623 ;
     RECT  29.4 75.609 29.52 75.623 ;
     RECT  34.8 75.609 34.92 75.623 ;
     RECT  40.2 75.609 40.32 75.623 ;
     RECT  45.6 75.609 45.72 75.623 ;
     RECT  51 75.609 51.12 75.623 ;
     RECT  56.4 75.609 56.52 75.623 ;
     RECT  67.2 75.609 67.32 75.623 ;
     RECT  72.6 75.609 72.72 75.623 ;
     RECT  78 75.609 78.12 75.623 ;
     RECT  83.4 75.609 83.52 75.623 ;
     RECT  64.272 74.771 64.776 75.781 ;
     RECT  66 74.723 66.024 75.781 ;
     RECT  61.2 74.723 63.24 76.357 ;
     RECT  64.272 75.781 66.024 76.357 ;
     RECT  61.2 76.357 66.024 76.597 ;
     RECT  61.2 76.597 66.216 77.413 ;
     RECT  61.2 77.413 66.312 77.461 ;
     RECT  61.2 77.461 66.408 77.557 ;
     RECT  61.104 77.557 66.408 77.605 ;
     RECT  61.008 77.605 66.408 77.712 ;
     RECT  45.096 0.611 45.192 1.859 ;
     RECT  73.224 1.763 73.608 1.859 ;
     RECT  42.6 1.811 43.632 1.859 ;
     RECT  42.216 1.859 43.728 2.339 ;
     RECT  44.136 1.859 45.192 2.137 ;
     RECT  72.912 1.859 73.608 2.821 ;
     RECT  51.432 1.907 51.816 2.629 ;
     RECT  44.136 2.137 45.6 2.821 ;
     RECT  40.824 2.245 42.192 2.339 ;
     RECT  40.824 2.339 41.496 2.821 ;
     RECT  51.432 2.629 52.8 3.397 ;
     RECT  18.912 2.773 19.968 5.459 ;
     RECT  44.568 2.821 45.6 4.117 ;
     RECT  45.912 2.821 47.28 3.445 ;
     RECT  64.488 2.821 65.52 3.349 ;
     RECT  72.912 2.821 74.304 5.029 ;
     RECT  56.712 2.869 58.224 3.205 ;
     RECT  67.608 3.059 68.04 4.453 ;
     RECT  74.328 3.061 75.696 3.301 ;
     RECT  57 3.205 58.224 3.253 ;
     RECT  57 3.253 58.128 3.925 ;
     RECT  53.448 3.349 54.432 3.587 ;
     RECT  54.456 3.349 55.68 3.541 ;
     RECT  46.152 3.445 47.28 3.923 ;
     RECT  54.696 3.541 55.68 4.259 ;
     RECT  53.448 3.587 54.672 4.259 ;
     RECT  45.912 3.923 47.28 3.925 ;
     RECT  45.912 3.925 47.232 4.981 ;
     RECT  51.312 4.115 52.464 5.125 ;
     RECT  55.344 4.259 55.68 4.261 ;
     RECT  19.992 4.261 21.12 5.459 ;
     RECT  17.136 4.403 17.712 4.501 ;
     RECT  8.112 4.501 9.12 7.619 ;
     RECT  15.336 4.501 16.32 4.789 ;
     RECT  16.344 4.501 17.712 5.461 ;
     RECT  76.584 4.547 77.664 6.181 ;
     RECT  35.304 4.643 35.928 5.269 ;
     RECT  24.312 4.691 25.584 6.277 ;
     RECT  9.576 4.693 10.896 5.603 ;
     RECT  51.312 5.125 52.416 6.805 ;
     RECT  35.304 5.269 36.384 5.411 ;
     RECT  21.144 5.413 22.464 6.323 ;
     RECT  22.488 5.413 23.472 5.747 ;
     RECT  18.912 5.459 19.224 5.461 ;
     RECT  20.976 5.459 21.12 5.701 ;
     RECT  9.432 5.603 10.896 5.939 ;
     RECT  22.488 5.747 23.712 6.323 ;
     RECT  68.04 5.747 69.12 6.757 ;
     RECT  20.976 5.891 21.072 6.853 ;
     RECT  69.336 5.893 70.848 6.517 ;
     RECT  21.144 6.323 21.864 6.421 ;
     RECT  74.952 6.419 76.272 6.899 ;
     RECT  40.728 6.517 42.192 7.619 ;
     RECT  78.312 6.805 79.728 7.763 ;
     RECT  45.912 6.851 46.008 7.957 ;
     RECT  20.976 6.853 21.024 7.333 ;
     RECT  68.04 6.899 69.312 9.109 ;
     RECT  3.48 7.283 3.528 8.293 ;
     RECT  51.312 7.379 52.464 8.869 ;
     RECT  54.168 7.381 55.68 7.861 ;
     RECT  30.024 7.427 31.056 8.485 ;
     RECT  49.176 7.429 50.208 8.485 ;
     RECT  8.112 7.619 9.408 12.469 ;
     RECT  78.312 7.763 78.504 8.293 ;
     RECT  54.6 7.861 55.68 7.909 ;
     RECT  54.696 7.909 55.68 8.627 ;
     RECT  45.456 7.955 45.504 8.917 ;
     RECT  38.808 7.957 40.2 10.117 ;
     RECT  12.384 8.003 12.48 9.109 ;
     RECT  69.576 8.051 70.848 9.203 ;
     RECT  76.296 8.147 77.664 11.653 ;
     RECT  9.432 8.243 9.768 9.109 ;
     RECT  66.12 8.291 67.2 9.589 ;
     RECT  3.48 8.293 4.608 9.685 ;
     RECT  4.632 8.293 5.76 8.339 ;
     RECT  4.632 8.339 5.808 9.685 ;
     RECT  30.072 8.485 31.056 9.253 ;
     RECT  53.256 8.579 54.576 8.723 ;
     RECT  54.6 8.627 55.68 8.723 ;
     RECT  19.848 8.725 20.88 8.867 ;
     RECT  37.8 8.773 38.784 10.307 ;
     RECT  18.912 8.867 19.032 10.357 ;
     RECT  51.312 8.869 52.416 9.971 ;
     RECT  42.84 9.061 44.208 9.731 ;
     RECT  9.432 9.109 10.656 10.405 ;
     RECT  68.136 9.109 69.312 9.637 ;
     RECT  69.336 9.203 70.848 9.541 ;
     RECT  12.384 9.251 12.48 9.733 ;
     RECT  25.464 9.251 25.944 9.541 ;
     RECT  29.712 9.395 31.056 10.883 ;
     RECT  22.488 9.445 23.712 10.739 ;
     RECT  25.464 9.541 26.496 10.309 ;
     RECT  69.336 9.541 70.8 10.835 ;
     RECT  11.448 9.733 12.48 11.845 ;
     RECT  45.912 9.779 46.728 10.021 ;
     RECT  4.632 9.875 5.808 14.627 ;
     RECT  35.976 9.971 37.2 10.883 ;
     RECT  51.312 9.971 52.464 16.021 ;
     RECT  45.912 10.021 46.896 10.787 ;
     RECT  3.48 10.307 4.608 15.061 ;
     RECT  37.8 10.307 39.264 11.171 ;
     RECT  25.512 10.309 26.496 10.643 ;
     RECT  65.784 10.451 67.2 12.277 ;
     RECT  60.792 10.499 61.8 12.757 ;
     RECT  45.912 10.787 47.232 10.883 ;
     RECT  68.136 10.835 70.8 10.885 ;
     RECT  35.88 10.883 37.2 12.757 ;
     RECT  45.912 10.883 46.008 11.077 ;
     RECT  68.136 10.885 70.656 11.075 ;
     RECT  68.136 11.075 70.8 11.365 ;
     RECT  37.8 11.171 40.2 11.557 ;
     RECT  49.584 11.219 50.208 12.517 ;
     RECT  27.528 11.365 28.512 11.411 ;
     RECT  68.136 11.365 69.408 13.093 ;
     RECT  69.432 11.365 70.8 12.997 ;
     RECT  27.528 11.411 29.04 12.035 ;
     RECT  5.832 11.413 6.816 14.627 ;
     RECT  38.856 11.557 40.2 12.517 ;
     RECT  11.496 11.845 12.48 11.941 ;
     RECT  42.84 11.941 43.968 13.619 ;
     RECT  17.4 12.419 18.6 14.245 ;
     RECT  8.232 12.469 9.408 12.613 ;
     RECT  38.856 12.517 40.08 13.139 ;
     RECT  8.232 12.613 9.216 12.995 ;
     RECT  76.296 12.755 77.664 13.283 ;
     RECT  35.112 12.803 36.576 13.571 ;
     RECT  8.232 12.995 9.36 13.043 ;
     RECT  69.816 12.997 70.8 13.043 ;
     RECT  8.232 13.043 9.408 13.189 ;
     RECT  9.768 13.043 10.848 13.571 ;
     RECT  69.816 13.043 70.848 13.715 ;
     RECT  22.056 13.045 23.04 14.869 ;
     RECT  14.856 13.091 15.984 13.475 ;
     RECT  68.376 13.093 69.408 13.139 ;
     RECT  38.856 13.139 40.2 14.147 ;
     RECT  68.376 13.139 69.792 13.715 ;
     RECT  8.376 13.189 9.408 13.427 ;
     RECT  53.256 13.333 54.528 13.477 ;
     RECT  54.552 13.333 55.68 16.019 ;
     RECT  8.232 13.427 9.408 14.675 ;
     RECT  14.568 13.475 15.984 14.725 ;
     RECT  32.448 13.523 32.472 14.821 ;
     RECT  70.128 13.715 70.848 14.773 ;
     RECT  40.512 14.101 41.616 17.315 ;
     RECT  38.232 14.147 40.2 14.867 ;
     RECT  17.4 14.245 18.48 15.299 ;
     RECT  36.72 14.291 37.2 15.445 ;
     RECT  80.064 14.387 80.352 15.395 ;
     RECT  68.136 14.627 68.376 15.637 ;
     RECT  8.112 14.675 9.408 16.885 ;
     RECT  14.568 14.725 15.936 16.309 ;
     RECT  29.712 14.821 31.2 15.013 ;
     RECT  31.224 14.821 32.472 14.869 ;
     RECT  39.36 14.867 40.2 15.061 ;
     RECT  31.224 14.869 32.64 15.011 ;
     RECT  32.664 14.869 34.08 15.011 ;
     RECT  41.64 14.963 42.816 17.269 ;
     RECT  31.224 15.011 32.472 15.059 ;
     RECT  29.832 15.013 31.2 15.059 ;
     RECT  29.832 15.059 32.472 15.349 ;
     RECT  17.4 15.299 18.6 16.357 ;
     RECT  29.832 15.349 30.96 15.539 ;
     RECT  30.984 15.349 32.472 15.445 ;
     RECT  80.064 15.395 80.64 15.589 ;
     RECT  19.176 15.445 20.304 15.491 ;
     RECT  30.984 15.445 32.448 15.539 ;
     RECT  35.112 15.445 36.096 16.549 ;
     RECT  36.12 15.445 37.2 15.491 ;
     RECT  19.032 15.491 20.304 16.259 ;
     RECT  36.12 15.491 37.584 16.933 ;
     RECT  29.832 15.539 32.448 15.589 ;
     RECT  29.832 15.589 32.256 15.829 ;
     RECT  78.408 15.589 79.632 17.653 ;
     RECT  79.656 15.589 80.64 19.427 ;
     RECT  68.712 15.637 70.128 15.683 ;
     RECT  68.712 15.683 71.088 16.307 ;
     RECT  60.792 15.779 61.8 17.029 ;
     RECT  30.744 15.829 32.256 15.971 ;
     RECT  53.784 16.019 55.68 16.981 ;
     RECT  51.432 16.163 52.464 17.125 ;
     RECT  19.032 16.259 20.328 16.549 ;
     RECT  68.184 16.307 71.088 17.029 ;
     RECT  6.312 16.499 7.584 17.363 ;
     RECT  19.032 16.549 20.112 17.077 ;
     RECT  20.136 16.549 20.328 16.789 ;
     RECT  80.664 16.549 81.792 17.651 ;
     RECT  65.784 16.595 66.96 18.133 ;
     RECT  20.136 16.789 21.168 17.027 ;
     RECT  14.568 16.883 15.84 17.219 ;
     RECT  8.232 16.885 9.408 18.419 ;
     RECT  36.12 16.933 37.536 17.653 ;
     RECT  53.784 16.981 54.864 17.651 ;
     RECT  68.184 17.029 69.648 17.219 ;
     RECT  69.672 17.029 71.088 18.707 ;
     RECT  75.24 17.029 76.272 17.651 ;
     RECT  25.896 17.077 27.12 17.315 ;
     RECT  59.544 17.077 60.768 17.555 ;
     RECT  35.112 17.171 36.096 18.275 ;
     RECT  14.568 17.219 15.936 18.949 ;
     RECT  17.4 17.219 18.6 18.565 ;
     RECT  68.136 17.219 69.648 18.707 ;
     RECT  41.832 17.269 42.816 19.859 ;
     RECT  25.896 17.315 27.552 17.699 ;
     RECT  40.512 17.315 41.808 19.859 ;
     RECT  27.912 17.363 29.04 17.459 ;
     RECT  27.576 17.459 29.04 17.699 ;
     RECT  11.736 17.603 13.056 18.851 ;
     RECT  18.912 17.603 20.112 19.427 ;
     RECT  74.952 17.651 76.272 19.235 ;
     RECT  80.664 17.651 81.048 18.133 ;
     RECT  25.896 17.699 26.472 18.371 ;
     RECT  51.312 17.891 52.464 21.061 ;
     RECT  10.248 17.989 11.712 18.275 ;
     RECT  60.792 18.179 61.8 23.365 ;
     RECT  42.84 18.181 43.872 20.003 ;
     RECT  43.896 18.181 44.928 20.051 ;
     RECT  35.112 18.275 35.208 18.805 ;
     RECT  25.416 18.371 26.472 18.709 ;
     RECT  8.112 18.419 9.408 19.043 ;
     RECT  17.496 18.565 18.6 20.341 ;
     RECT  46.008 18.661 47.472 18.901 ;
     RECT  68.136 18.707 68.376 20.101 ;
     RECT  25.416 18.709 26.448 19.333 ;
     RECT  11.736 18.851 13.104 19.957 ;
     RECT  65.784 18.899 67.2 26.725 ;
     RECT  46.056 18.901 47.472 19.381 ;
     RECT  14.568 18.949 15.792 19.091 ;
     RECT  76.296 18.995 77.664 20.485 ;
     RECT  78.504 18.995 79.632 19.523 ;
     RECT  14.568 19.091 16.176 20.533 ;
     RECT  74.904 19.235 76.272 19.763 ;
     RECT  25.416 19.333 26.4 21.061 ;
     RECT  46.056 19.381 47.328 19.427 ;
     RECT  45.912 19.427 47.328 20.291 ;
     RECT  79.656 19.427 80.88 19.523 ;
     RECT  49.224 19.909 50.208 20.963 ;
     RECT  11.736 19.957 12.768 20.149 ;
     RECT  44.208 20.051 44.928 20.965 ;
     RECT  11.736 20.149 12.72 20.485 ;
     RECT  32.28 20.197 33.264 21.349 ;
     RECT  76.296 20.485 77.376 21.395 ;
     RECT  14.568 20.533 15.552 21.013 ;
     RECT  17.496 20.723 18.6 23.125 ;
     RECT  64.488 20.963 65.472 23.653 ;
     RECT  11.736 21.155 12.72 23.173 ;
     RECT  8.112 21.203 8.232 21.637 ;
     RECT  73.08 21.203 74.304 23.029 ;
     RECT  76.296 21.395 77.616 30.757 ;
     RECT  32.28 21.491 33.264 21.875 ;
     RECT  8.112 21.637 9.456 22.933 ;
     RECT  74.328 21.637 75.696 22.451 ;
     RECT  32.28 21.875 34.08 22.453 ;
     RECT  19.752 21.925 21.12 26.291 ;
     RECT  21.432 21.973 22.944 22.115 ;
     RECT  78.504 21.973 79.824 22.115 ;
     RECT  39.6 22.211 39.936 23.269 ;
     RECT  74.328 22.451 76.272 23.797 ;
     RECT  27.384 22.453 28.656 23.555 ;
     RECT  32.712 22.453 34.08 22.595 ;
     RECT  59.496 22.645 60.768 25.763 ;
     RECT  45.912 22.741 46.944 23.939 ;
     RECT  9.48 22.789 10.656 23.651 ;
     RECT  10.68 22.789 11.712 23.651 ;
     RECT  63.84 22.835 64.08 23.653 ;
     RECT  8.112 22.933 9.12 23.941 ;
     RECT  51.432 23.507 52.464 26.291 ;
     RECT  11.52 23.651 11.712 24.133 ;
     RECT  62.664 23.653 64.08 23.891 ;
     RECT  74.328 23.797 75.84 24.515 ;
     RECT  37.896 23.845 39.12 23.987 ;
     RECT  11.784 23.891 13.104 25.187 ;
     RECT  45.912 23.939 46.776 25.093 ;
     RECT  68.28 23.987 69.504 25.573 ;
     RECT  74.328 24.515 76.272 24.997 ;
     RECT  60.792 24.659 61.8 38.389 ;
     RECT  4.632 24.661 5.664 25.139 ;
     RECT  32.856 24.661 34.08 24.947 ;
     RECT  74.664 24.997 76.272 25.235 ;
     RECT  36.696 25.093 37.776 25.331 ;
     RECT  11.784 25.187 13.2 26.053 ;
     RECT  69.528 25.189 70.656 26.243 ;
     RECT  74.328 25.235 76.272 25.621 ;
     RECT  73.032 25.283 74.304 25.715 ;
     RECT  74.328 25.621 75.84 26.197 ;
     RECT  32.28 25.667 32.472 26.677 ;
     RECT  72.912 25.715 74.304 27.301 ;
     RECT  11.976 26.053 13.2 26.533 ;
     RECT  80.76 26.195 80.856 27.445 ;
     RECT  74.712 26.197 75.84 26.243 ;
     RECT  3.912 26.243 4.536 27.301 ;
     RECT  19.752 26.291 19.848 26.389 ;
     RECT  51.312 26.291 52.464 28.261 ;
     RECT  12.216 26.533 13.2 26.629 ;
     RECT  62.808 26.677 64.08 29.029 ;
     RECT  54.168 26.725 55.68 27.587 ;
     RECT  65.784 26.725 67.104 26.771 ;
     RECT  19.752 26.771 19.848 28.213 ;
     RECT  65.496 26.771 67.104 27.157 ;
     RECT  37.8 26.821 39.312 26.963 ;
     RECT  37.8 26.963 39.504 27.925 ;
     RECT  65.496 27.157 66.768 27.205 ;
     RECT  65.496 27.205 66.672 28.261 ;
     RECT  12.216 27.347 13.2 27.923 ;
     RECT  26.472 27.877 27.456 28.693 ;
     RECT  33.096 27.877 34.08 28.213 ;
     RECT  11.832 27.923 13.2 28.787 ;
     RECT  37.8 27.925 39.024 28.261 ;
     RECT  48.744 28.069 50.208 30.853 ;
     RECT  19.752 28.213 21.168 28.643 ;
     RECT  35.112 28.213 36.576 28.787 ;
     RECT  36.6 28.213 37.776 28.405 ;
     RECT  64.488 28.307 65.472 31.333 ;
     RECT  36.648 28.405 37.776 28.837 ;
     RECT  68.472 28.501 69.936 29.699 ;
     RECT  69.96 28.501 71.088 29.699 ;
     RECT  21.12 28.643 21.168 28.645 ;
     RECT  72.912 28.643 74.304 31.285 ;
     RECT  38.184 28.739 39.504 29.795 ;
     RECT  11.736 28.787 13.2 29.029 ;
     RECT  35.112 28.787 36.624 28.979 ;
     RECT  26.472 28.835 27.456 35.557 ;
     RECT  35.112 28.979 36.768 29.845 ;
     RECT  36.792 29.027 37.776 31.139 ;
     RECT  11.736 29.029 13.104 32.725 ;
     RECT  22.8 29.171 24 29.893 ;
     RECT  51.312 29.219 52.464 31.861 ;
     RECT  29.88 29.221 31.008 30.371 ;
     RECT  33.84 29.507 34.08 30.997 ;
     RECT  44.352 29.507 44.928 30.133 ;
     RECT  59.496 29.605 60.768 30.709 ;
     RECT  39.36 29.795 39.504 29.893 ;
     RECT  8.712 29.845 9.792 34.021 ;
     RECT  35.208 29.845 36.768 30.325 ;
     RECT  22.776 29.893 24 30.181 ;
     RECT  43.704 30.133 44.928 34.355 ;
     RECT  35.208 30.325 36.72 31.187 ;
     RECT  29.832 30.371 31.008 30.803 ;
     RECT  29.712 30.803 31.008 33.589 ;
     RECT  48.744 30.853 50.064 31.285 ;
     RECT  33.048 30.997 34.08 33.157 ;
     RECT  36.744 31.139 37.776 34.741 ;
     RECT  72.912 31.285 74.256 32.725 ;
     RECT  40.512 31.381 41.616 32.341 ;
     RECT  51.312 31.861 52.416 33.445 ;
     RECT  78.456 32.437 79.824 34.115 ;
     RECT  66.168 32.531 67.2 35.027 ;
     RECT  4.536 33.013 5.952 34.115 ;
     RECT  40.512 33.155 41.616 34.115 ;
     RECT  33.048 33.395 34.08 33.683 ;
     RECT  48.552 33.587 49.632 36.515 ;
     RECT  29.832 33.589 31.008 35.267 ;
     RECT  3.528 33.635 4.512 34.115 ;
     RECT  32.664 33.683 34.08 36.275 ;
     RECT  3.48 34.115 4.512 34.883 ;
     RECT  44.448 34.355 44.928 35.317 ;
     RECT  27.816 34.501 29.088 34.789 ;
     RECT  27.816 34.931 29.088 35.459 ;
     RECT  64.488 35.027 65.472 35.989 ;
     RECT  65.832 35.027 67.2 35.989 ;
     RECT  82.104 35.077 83.4 36.275 ;
     RECT  31.032 35.171 32.64 35.267 ;
     RECT  32.496 35.267 32.64 36.229 ;
     RECT  27.816 35.459 29.232 36.371 ;
     RECT  73.128 35.507 74.304 37.139 ;
     RECT  78.312 35.555 78.456 36.757 ;
     RECT  74.76 35.701 76.08 36.179 ;
     RECT  51.312 35.747 52.464 40.259 ;
     RECT  65.832 36.131 66.816 37.093 ;
     RECT  74.76 36.179 76.272 36.611 ;
     RECT  27.48 36.371 29.232 36.901 ;
     RECT  19.848 36.421 21.216 36.661 ;
     RECT  19.848 36.661 20.928 36.853 ;
     RECT  27.48 36.901 28.464 37.043 ;
     RECT  14.568 36.947 15.696 38.099 ;
     RECT  46.44 36.949 47.76 37.093 ;
     RECT  36.744 36.995 37.776 40.499 ;
     RECT  19.848 37.043 21.216 37.955 ;
     RECT  76.296 37.043 76.392 37.573 ;
     RECT  46.584 37.093 47.76 37.235 ;
     RECT  72.912 37.139 74.304 39.109 ;
     RECT  45.912 37.235 47.76 38.435 ;
     RECT  69.72 37.429 71.088 37.861 ;
     RECT  65.976 37.571 67.2 38.675 ;
     RECT  21.768 37.573 23.136 38.147 ;
     RECT  76.296 37.573 77.472 40.835 ;
     RECT  38.616 37.667 40.032 38.677 ;
     RECT  64.488 37.859 65.472 42.899 ;
     RECT  69.96 37.861 71.088 39.061 ;
     RECT  19.8 37.955 21.216 38.435 ;
     RECT  26.472 38.003 27.456 39.587 ;
     RECT  14.568 38.099 16.032 38.773 ;
     RECT  19.8 38.435 21.312 38.675 ;
     RECT  45.912 38.435 47.4 38.533 ;
     RECT  46.248 38.533 47.4 38.773 ;
     RECT  19.128 38.675 21.312 39.011 ;
     RECT  65.88 38.675 67.2 46.645 ;
     RECT  38.616 38.677 39.648 38.771 ;
     RECT  14.856 38.773 16.032 38.819 ;
     RECT  46.728 38.773 47.4 39.059 ;
     RECT  39.888 38.819 39.984 39.781 ;
     RECT  19.128 39.011 21.744 40.117 ;
     RECT  45.912 39.059 47.4 39.733 ;
     RECT  29.712 39.157 31.152 40.019 ;
     RECT  8.712 39.203 8.856 40.165 ;
     RECT  54.168 39.589 55.68 41.075 ;
     RECT  2.808 39.685 4.032 40.547 ;
     RECT  43.464 39.733 44.928 40.835 ;
     RECT  45.912 39.733 47.376 42.709 ;
     RECT  28.392 39.827 29.4 40.019 ;
     RECT  62.952 39.923 64.464 42.899 ;
     RECT  82.656 39.923 83.4 40.837 ;
     RECT  29.712 40.019 31.08 40.981 ;
     RECT  19.128 40.117 20.64 40.403 ;
     RECT  20.664 40.117 21.744 40.403 ;
     RECT  8.712 40.165 9.936 42.803 ;
     RECT  74.904 40.165 76.272 41.365 ;
     RECT  60.792 40.259 61.8 41.461 ;
     RECT  13.512 40.355 14.544 41.893 ;
     RECT  19.128 40.403 19.896 40.549 ;
     RECT  21.552 40.403 21.744 40.789 ;
     RECT  37.008 40.499 37.776 41.269 ;
     RECT  2.712 40.547 4.032 42.899 ;
     RECT  40.512 40.693 41.616 41.795 ;
     RECT  19.128 40.835 19.896 42.229 ;
     RECT  73.176 40.835 74.304 42.755 ;
     RECT  76.296 40.835 77.52 41.747 ;
     RECT  82.104 40.837 83.4 41.651 ;
     RECT  21.768 40.979 21.816 42.469 ;
     RECT  29.712 40.981 31.056 41.651 ;
     RECT  39.888 41.171 40.032 41.749 ;
     RECT  75.24 41.365 76.272 41.557 ;
     RECT  78.792 41.605 80.016 41.651 ;
     RECT  34.08 41.651 34.56 42.325 ;
     RECT  37.8 41.749 38.784 43.093 ;
     RECT  38.808 41.749 40.032 42.467 ;
     RECT  33.528 42.325 34.56 44.579 ;
     RECT  42.36 42.325 43.344 42.707 ;
     RECT  7.68 42.467 7.8 43.717 ;
     RECT  38.808 42.467 40.2 43.427 ;
     RECT  21.816 42.469 22.896 42.755 ;
     RECT  60.792 42.659 61.8 46.933 ;
     RECT  10.248 42.709 11.712 44.051 ;
     RECT  45.912 42.709 47.136 44.339 ;
     RECT  21.816 42.755 23.376 43.237 ;
     RECT  72.912 42.755 74.304 44.099 ;
     RECT  8.712 42.803 10.224 44.051 ;
     RECT  64.896 42.899 65.472 43.141 ;
     RECT  19.128 42.947 20.04 43.861 ;
     RECT  21.864 43.237 23.376 43.907 ;
     RECT  75.24 43.283 76.272 43.571 ;
     RECT  38.76 43.427 40.2 44.965 ;
     RECT  68.28 43.669 69.696 45.299 ;
     RECT  69.72 43.669 71.088 46.259 ;
     RECT  5.928 43.717 7.44 45.347 ;
     RECT  19.128 43.861 20.256 44.867 ;
     RECT  20.28 43.861 21.744 44.677 ;
     RECT  54.216 43.861 55.68 44.869 ;
     RECT  10.8 44.051 11.712 44.629 ;
     RECT  26.472 44.051 26.616 44.965 ;
     RECT  45.912 44.339 47.376 45.685 ;
     RECT  33.528 44.579 34.8 45.731 ;
     RECT  30.264 44.581 31.536 44.627 ;
     RECT  31.56 44.581 32.592 44.869 ;
     RECT  36.456 44.629 37.776 45.011 ;
     RECT  64.896 44.771 65.472 45.493 ;
     RECT  21.12 44.867 21.216 45.011 ;
     RECT  26.472 44.965 27.888 47.891 ;
     RECT  38.808 44.965 40.2 46.021 ;
     RECT  21.12 45.011 21.312 45.635 ;
     RECT  31.56 45.011 32.592 45.779 ;
     RECT  35.592 45.011 35.88 46.213 ;
     RECT  37.632 45.011 37.776 45.541 ;
     RECT  24.408 45.059 25.584 47.075 ;
     RECT  14.568 45.301 15.792 47.315 ;
     RECT  5.904 45.347 7.44 45.637 ;
     RECT  62.952 45.493 64.368 45.733 ;
     RECT  64.392 45.493 65.472 46.979 ;
     RECT  11.376 45.587 11.712 46.933 ;
     RECT  53.592 45.587 54.72 47.891 ;
     RECT  21.12 45.635 21.144 46.165 ;
     RECT  5.904 45.637 5.952 46.117 ;
     RECT  5.976 45.637 7.44 46.211 ;
     RECT  46.056 45.685 47.376 45.829 ;
     RECT  62.952 45.733 64.32 46.499 ;
     RECT  31.92 45.779 32.592 46.885 ;
     RECT  46.104 45.829 47.376 47.461 ;
     RECT  4.776 46.117 5.952 46.645 ;
     RECT  11.736 46.499 12.912 46.547 ;
     RECT  63.888 46.499 64.32 46.933 ;
     RECT  81.912 46.499 83.4 47.939 ;
     RECT  11.736 46.547 13.2 49.139 ;
     RECT  65.976 46.645 67.2 48.421 ;
     RECT  19.128 46.741 20.304 46.883 ;
     RECT  19.128 46.883 19.416 47.029 ;
     RECT  31.944 46.931 32.616 48.133 ;
     RECT  64.344 46.979 65.472 47.603 ;
     RECT  38.088 47.027 39.264 48.707 ;
     RECT  24.312 47.075 25.584 53.267 ;
     RECT  4.776 47.363 5.952 48.421 ;
     RECT  60.792 47.459 61.8 49.045 ;
     RECT  46.296 47.461 47.376 48.275 ;
     RECT  8.568 47.557 10.08 47.747 ;
     RECT  10.104 47.557 11.376 47.747 ;
     RECT  64.368 47.603 65.472 48.901 ;
     RECT  8.568 47.747 8.808 48.661 ;
     RECT  25.608 47.891 27.888 48.421 ;
     RECT  53.256 47.891 54.72 49.523 ;
     RECT  31.944 48.133 33.408 48.467 ;
     RECT  33.432 48.133 34.8 48.467 ;
     RECT  46.056 48.275 47.376 49.333 ;
     RECT  4.776 48.421 5.76 48.997 ;
     RECT  25.608 48.421 26.688 48.563 ;
     RECT  26.712 48.421 27.888 48.563 ;
     RECT  66.216 48.421 67.2 49.091 ;
     RECT  74.76 48.421 76.272 48.805 ;
     RECT  31.944 48.467 33.096 48.853 ;
     RECT  25.608 48.563 27.888 48.901 ;
     RECT  37.8 48.707 39.264 48.995 ;
     RECT  74.76 48.805 76.032 49.619 ;
     RECT  25.608 48.901 27.12 49.043 ;
     RECT  64.392 48.901 65.472 48.997 ;
     RECT  68.328 48.949 69.504 48.997 ;
     RECT  17.496 48.995 18.48 50.579 ;
     RECT  2.712 48.997 4.032 50.099 ;
     RECT  65.976 49.091 67.2 53.075 ;
     RECT  6.504 49.093 7.8 51.733 ;
     RECT  4.776 49.139 5.76 50.149 ;
     RECT  12.864 49.139 13.2 49.525 ;
     RECT  64.392 49.139 65.472 50.051 ;
     RECT  68.328 49.139 69.504 49.811 ;
     RECT  46.2 49.333 47.376 49.475 ;
     RECT  46.2 49.475 47.664 49.619 ;
     RECT  53.256 49.523 54.864 49.909 ;
     RECT  35.88 49.573 37.056 50.291 ;
     RECT  74.76 49.619 76.272 51.635 ;
     RECT  53.784 49.909 54.864 52.307 ;
     RECT  8.808 50.101 10.32 50.195 ;
     RECT  8.112 50.195 10.32 51.589 ;
     RECT  35.208 50.435 35.88 51.877 ;
     RECT  60.792 50.435 61.8 52.403 ;
     RECT  17.496 50.579 18.6 54.421 ;
     RECT  59.016 50.627 60.432 50.771 ;
     RECT  27.408 50.675 27.84 50.771 ;
     RECT  27.408 50.771 27.888 51.829 ;
     RECT  4.56 51.107 4.752 52.115 ;
     RECT  32.472 51.253 33.552 51.443 ;
     RECT  33.576 51.253 34.8 52.741 ;
     RECT  13.056 51.395 13.104 52.453 ;
     RECT  32.424 51.443 33.552 52.931 ;
     RECT  8.112 51.589 9.12 51.779 ;
     RECT  9.144 51.589 10.32 51.779 ;
     RECT  75.264 51.635 76.272 51.637 ;
     RECT  75.288 51.637 76.272 51.973 ;
     RECT  6.504 51.733 7.68 51.923 ;
     RECT  27.408 51.829 27.792 51.877 ;
     RECT  51.312 51.829 52.752 56.963 ;
     RECT  25.608 51.877 26.784 52.403 ;
     RECT  26.808 51.877 27.792 52.403 ;
     RECT  5.688 51.923 7.68 52.451 ;
     RECT  4.56 52.115 5.664 52.117 ;
     RECT  75.288 52.115 76.272 52.211 ;
     RECT  3.144 52.117 5.664 52.309 ;
     RECT  23.376 52.163 23.616 53.557 ;
     RECT  38.424 52.163 39.456 53.123 ;
     RECT  78.648 52.211 79.776 53.603 ;
     RECT  53.784 52.307 54.12 53.125 ;
     RECT  3.288 52.309 5.664 53.509 ;
     RECT  60.768 52.403 61.8 52.405 ;
     RECT  60.648 52.405 61.8 57.061 ;
     RECT  5.688 52.451 7.8 53.365 ;
     RECT  33.576 52.741 34.704 52.789 ;
     RECT  32.424 52.931 34.8 53.077 ;
     RECT  76.272 53.075 76.368 54.181 ;
     RECT  33.528 53.077 34.8 53.603 ;
     RECT  24.312 53.267 25.128 53.461 ;
     RECT  32.424 53.363 33.504 53.603 ;
     RECT  5.688 53.365 6.768 55.379 ;
     RECT  6.792 53.365 7.8 56.003 ;
     RECT  43.944 53.365 45.456 55.091 ;
     RECT  4.68 53.509 5.664 54.611 ;
     RECT  23.088 53.699 23.328 54.373 ;
     RECT  35.208 53.795 35.304 55.189 ;
     RECT  64.104 54.037 65.472 54.661 ;
     RECT  40.512 54.179 41.064 54.661 ;
     RECT  50.448 54.371 51 55.525 ;
     RECT  22.2 54.373 23.328 54.901 ;
     RECT  40.512 54.661 41.616 57.059 ;
     RECT  64.584 54.755 65.496 54.757 ;
     RECT  64.584 54.757 65.616 54.947 ;
     RECT  22.2 54.901 23.184 55.715 ;
     RECT  64.584 54.947 65.64 55.237 ;
     RECT  43.944 55.091 45.6 55.907 ;
     RECT  64.584 55.237 65.952 65.557 ;
     RECT  75.648 55.283 76.368 56.437 ;
     RECT  68.04 55.331 69.216 58.117 ;
     RECT  49.56 55.525 51 56.243 ;
     RECT  17.4 55.667 18.6 56.627 ;
     RECT  43.92 55.907 45.6 56.437 ;
     RECT  13.608 56.389 14.832 57.059 ;
     RECT  43.848 56.437 45.6 56.485 ;
     RECT  75.24 56.437 76.368 57.013 ;
     RECT  13.104 56.483 13.2 57.541 ;
     RECT  27.336 56.483 28.656 57.011 ;
     RECT  43.848 56.485 45.024 56.867 ;
     RECT  18.48 56.627 18.6 56.965 ;
     RECT  78.312 56.725 79.632 56.917 ;
     RECT  63.048 56.771 64.08 64.213 ;
     RECT  78.504 56.917 79.632 57.059 ;
     RECT  75.24 57.013 76.272 57.059 ;
     RECT  38.904 57.059 39.984 59.365 ;
     RECT  40.512 57.059 41.016 57.637 ;
     RECT  65.976 57.059 67.2 62.053 ;
     RECT  78.504 57.059 78.984 57.973 ;
     RECT  21.096 57.061 22.176 57.925 ;
     RECT  60.648 57.203 61.8 61.573 ;
     RECT  18.48 57.299 18.6 58.549 ;
     RECT  32.472 57.395 32.664 57.493 ;
     RECT  59.496 57.445 60.624 61.333 ;
     RECT  32.472 57.493 33.888 57.923 ;
     RECT  6.312 57.541 7.8 58.117 ;
     RECT  57.72 57.635 58.992 59.891 ;
     RECT  21.144 57.925 22.176 58.115 ;
     RECT  21.168 58.115 22.176 58.165 ;
     RECT  71.112 58.115 72.24 59.173 ;
     RECT  6.312 58.117 7.68 58.211 ;
     RECT  70.008 58.117 71.088 59.795 ;
     RECT  35.256 58.163 35.4 59.461 ;
     RECT  21.192 58.165 22.176 58.307 ;
     RECT  6.816 58.211 7.68 59.173 ;
     RECT  78.504 58.691 78.984 59.701 ;
     RECT  51.912 59.221 53.232 62.771 ;
     RECT  35.256 59.461 36.336 59.603 ;
     RECT  18.912 59.507 19.128 60.949 ;
     RECT  38.712 59.507 39.984 60.515 ;
     RECT  35.256 59.603 35.352 59.701 ;
     RECT  35.304 59.701 35.352 61.093 ;
     RECT  78.504 59.701 79.824 60.803 ;
     RECT  79.848 59.701 81.072 59.797 ;
     RECT  69.24 59.795 71.088 60.467 ;
     RECT  79.848 59.797 80.832 60.803 ;
     RECT  16.488 59.845 17.904 59.891 ;
     RECT  17.04 59.891 17.904 60.661 ;
     RECT  68.04 60.035 69.216 60.467 ;
     RECT  20.712 60.277 22.176 60.515 ;
     RECT  40.512 60.371 40.632 61.429 ;
     RECT  70.224 60.467 71.088 60.901 ;
     RECT  38.712 60.515 40.2 62.773 ;
     RECT  76.392 60.613 77.472 60.947 ;
     RECT  43.32 60.709 44.448 61.907 ;
     RECT  17.76 60.899 17.856 62.149 ;
     RECT  74.808 60.901 76.272 60.947 ;
     RECT  76.296 60.947 77.472 63.205 ;
     RECT  18.912 60.949 20.112 61.907 ;
     RECT  44.472 61.187 45.6 61.907 ;
     RECT  70.224 61.427 71.088 62.677 ;
     RECT  60.792 61.573 61.8 63.061 ;
     RECT  71.592 61.715 72.6 62.723 ;
     RECT  32.472 62.341 33.744 63.013 ;
     RECT  33.768 62.341 34.8 63.875 ;
     RECT  57.384 62.581 58.752 62.677 ;
     RECT  57.384 62.677 58.656 62.963 ;
     RECT  68.04 62.677 69.552 64.595 ;
     RECT  69.576 62.677 71.088 64.595 ;
     RECT  71.544 62.723 72.6 64.357 ;
     RECT  51.912 62.771 54.096 63.589 ;
     RECT  39 62.773 40.2 63.301 ;
     RECT  32.472 63.013 33.648 64.019 ;
     RECT  74.808 63.205 76.272 64.451 ;
     RECT  52.872 63.589 54.096 64.357 ;
     RECT  28.704 63.875 28.896 64.645 ;
     RECT  33.672 63.875 34.8 64.019 ;
     RECT  51.312 63.923 52.848 65.077 ;
     RECT  14.52 63.973 15.888 64.019 ;
     RECT  15.912 63.973 17.04 64.259 ;
     RECT  15.408 64.019 15.888 64.933 ;
     RECT  32.04 64.019 33.192 64.405 ;
     RECT  63.096 64.213 64.08 64.547 ;
     RECT  53.064 64.357 54.096 64.451 ;
     RECT  32.04 64.405 33.072 64.547 ;
     RECT  43.896 64.405 45.024 64.739 ;
     RECT  75.408 64.451 76.272 65.317 ;
     RECT  32.04 64.547 33.168 64.595 ;
     RECT  63.048 64.547 64.08 65.509 ;
     RECT  38.808 64.595 40.2 65.939 ;
     RECT  70.608 64.595 71.088 64.981 ;
     RECT  27.816 64.645 28.896 65.651 ;
     RECT  43.896 64.739 45.504 64.789 ;
     RECT  44.04 64.789 45.504 64.931 ;
     RECT  6.792 64.885 7.8 65.267 ;
     RECT  71.544 65.027 72.6 66.179 ;
     RECT  51.432 65.077 52.848 67.427 ;
     RECT  37.896 65.939 40.2 66.613 ;
     RECT  46.632 66.085 48.096 66.755 ;
     RECT  71.112 66.179 72.6 67.571 ;
     RECT  40.512 66.275 41.304 67.237 ;
     RECT  58.92 66.323 59.952 67.091 ;
     RECT  37.896 66.613 38.928 68.387 ;
     RECT  38.952 66.613 40.2 68.387 ;
     RECT  46.632 66.755 46.968 67.237 ;
     RECT  58.824 67.091 59.952 67.955 ;
     RECT  60.792 67.091 61.8 68.389 ;
     RECT  49.8 67.189 51 67.907 ;
     RECT  40.512 67.237 41.808 69.491 ;
     RECT  46.872 67.237 46.968 68.197 ;
     RECT  28.992 67.715 29.4 68.965 ;
     RECT  17.208 67.717 18.6 68.965 ;
     RECT  67.608 67.907 68.04 68.917 ;
     RECT  58.824 67.955 60.624 68.869 ;
     RECT  5.136 68.099 5.16 68.917 ;
     RECT  43.8 68.197 44.976 68.675 ;
     RECT  0.144 68.291 0.168 69.301 ;
     RECT  59.256 68.869 60.624 69.587 ;
     RECT  4.632 68.917 5.664 70.067 ;
     RECT  67.608 68.917 68.688 69.155 ;
     RECT  2.904 68.965 3.984 72.419 ;
     RECT  17.304 68.965 18.6 70.259 ;
     RECT  19.656 68.965 21.168 69.587 ;
     RECT  27.96 68.965 29.4 69.445 ;
     RECT  67.608 69.155 67.8 70.405 ;
     RECT  28.2 69.445 29.4 69.731 ;
     RECT  60.648 69.491 61.632 71.701 ;
     RECT  19.656 69.587 21.192 70.021 ;
     RECT  27.96 69.731 29.4 69.779 ;
     RECT  29.088 69.779 29.4 70.021 ;
     RECT  35.112 69.973 36.432 70.835 ;
     RECT  36.456 69.973 37.872 70.835 ;
     RECT  19.656 70.021 21.504 70.933 ;
     RECT  30.168 70.117 31.44 70.787 ;
     RECT  54.888 70.549 56.4 72.419 ;
     RECT  67.8 70.741 68.928 71.317 ;
     RECT  20.52 70.933 21.504 71.315 ;
     RECT  67.8 71.317 68.88 72.131 ;
     RECT  75.96 71.365 77.184 72.035 ;
     RECT  64.296 71.891 65.472 73.669 ;
     RECT  67.512 72.131 68.88 72.181 ;
     RECT  67.512 72.181 68.688 72.371 ;
     RECT  22.824 72.325 24 73.283 ;
     RECT  27.672 72.325 29.088 72.851 ;
     RECT  59.256 72.325 60.624 72.515 ;
     RECT  67.512 72.371 68.928 72.419 ;
     RECT  67.512 72.419 67.608 73.285 ;
     RECT  58.656 72.467 58.704 73.765 ;
     RECT  27.24 72.947 27.48 74.053 ;
     RECT  44.472 73.093 45.6 74.435 ;
     RECT  64.296 73.669 65.424 74.389 ;
     RECT  56.712 73.765 58.128 74.723 ;
     RECT  73.032 74.053 74.496 74.579 ;
     RECT  66.024 74.147 67.2 75.623 ;
     RECT  55.032 74.629 56.4 74.915 ;
     RECT  63.24 74.723 64.224 74.771 ;
     RECT  64.776 74.723 66 75.781 ;
     RECT  63.24 74.771 64.272 76.357 ;
     RECT  66.024 75.623 66.216 76.597 ;
  END
END ot_hgi_qdq_core_fin2
END LIBRARY
